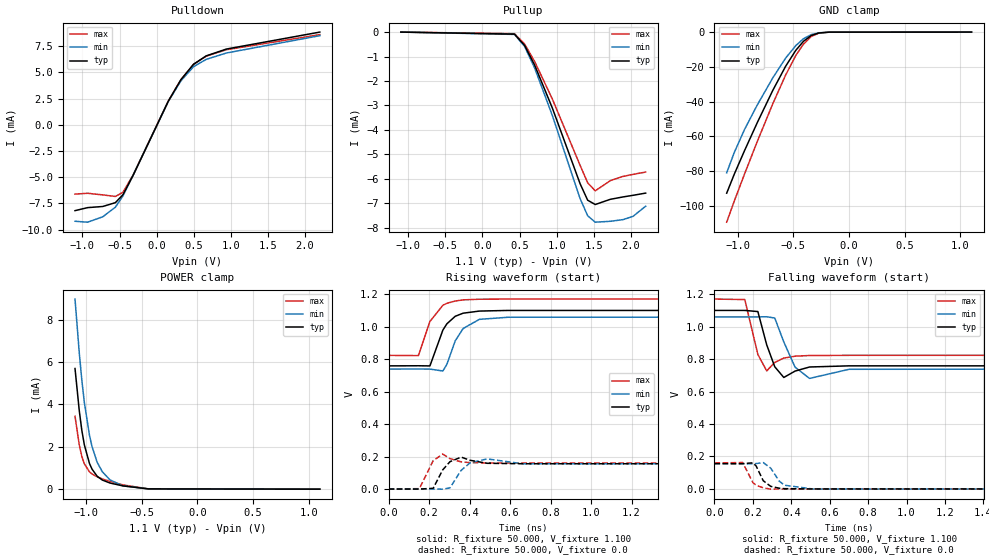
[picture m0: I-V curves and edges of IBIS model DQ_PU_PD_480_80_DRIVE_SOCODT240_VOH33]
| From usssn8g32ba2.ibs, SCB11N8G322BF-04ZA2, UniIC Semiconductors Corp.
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|   Model DQ_PU_PD_480_80_DRIVE_SOCODT240_VOH33
[Model] DQ_PU_PD_480_80_DRIVE_SOCODT240_VOH33
Model_type I/O
Polarity   Inverting
Vinl =  98.000mV
Vinh =  0.268V
Vmeas =  0.183V
Rref =  50.000
Vref =  0.183V
C_comp   1.020pF   1.010pF   1.030pF
[Model Spec]
Vinh   0.268V   0.262V   0.280V
Vinl   98.000mV   92.000mV   0.110V
Vmeas   0.183V   0.177V   0.195V
Vref   0.183V   0.177V   0.195V
Rref   50.000   NA   NA
[Temperature Range]   25.000   0.105k   -40.000
[Voltage Range]   1.100V   1.060V   1.170V
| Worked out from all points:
|   slope of the pulldown table from 0 to 0.165 V, typ, clamps not added: 70.2 ohm
|   GND clamp passes 1 mA (typ) near -0.30 V on its own axis
|   POWER clamp passes 1 mA (typ) near -0.95 V on its own axis
|   rising waveform, R_fixture 50.000, V_fixture 1.100: 20-80 % time 72.7ps typ, 76.2ps min, 70.1ps max; typ from 0.759 V to 1.1 V
|   rising waveform, R_fixture 50.000, V_fixture 0.0: 20-80 % time 36.6ps typ, 46.1ps min, 30.1ps max; typ from 0 V to 0.156 V
|   falling waveform, R_fixture 50.000, V_fixture 1.100: 20-80 % time 44.4ps typ, 57.6ps min, 35.3ps max; typ from 1.1 V to 0.759 V
|   falling waveform, R_fixture 50.000, V_fixture 0.0: 20-80 % time 45.9ps typ, 57.9ps min, 42.8ps max; typ from 0.156 V to 0 V
[Pulldown]
|Voltage   I(typ)   I(min)   I(max)
-1.1V     -8.193mA   -9.206mA   -6.618mA
-930mV    -7.906mA   -9.295mA   -6.537mA
-726mV    -7.797mA   -8.78mA    -6.691mA
-556mV    -7.432mA   -7.863mA   -6.841mA
-454mV    -6.673mA   -6.794mA   -6.44mA
-318mV    -4.841mA   -4.838mA   -4.804mA
158mV     2.257mA    2.219mA    2.267mA
328mV     4.302mA    4.194mA    4.305mA
498mV     5.77mA     5.539mA    5.759mA
668mV     6.567mA    6.233mA    6.54mA
940mV     7.217mA    6.841mA    7.152mA
2.2V      8.836mA    8.496mA    8.595mA
[Pullup]
|Voltage   I(typ)   I(min)   I(max)
-1.1V     500pA      5.412nA    0A
432mV     -84.42uA   -95.4uA    -65.89uA
568mV     -546.4uA   -585.3uA   -487.9uA
704mV     -1.354mA   -1.473mA   -1.207mA
942mV     -3.104mA   -3.412mA   -2.737mA
1.316V    -6.198mA   -6.807mA   -5.446mA
1.418V    -6.872mA   -7.507mA   -6.161mA
1.52V     -7.049mA   -7.771mA   -6.489mA
1.724V    -6.835mA   -7.734mA   -6.072mA
1.894V    -6.739mA   -7.667mA   -5.9mA
2.03V     -6.672mA   -7.532mA   -5.816mA
2.2V      -6.582mA   -7.117mA   -5.721mA
[GND_clamp]
|Voltage   I(typ)   I(min)   I(max)
-1.1V     -92.78mA   -81.05mA   -109.5mA
-1.031V   -81.73mA   -69.22mA   -97.17mA
-939mV    -68.18mA   -56.02mA   -81.64mA
-824mV    -52mA      -41.83mA   -62.83mA
-686mV    -33.62mA   -26.41mA   -41.32mA
-571mV    -19.76mA   -15.06mA   -24.85mA
-479mV    -10.5mA    -7.76mA    -13.5mA
-410mV    -5.313mA   -3.84mA    -6.916mA
-341mV    -2.007mA   -1.45mA    -2.59mA
-272mV    -506.9uA   -403.5uA   -609.8uA
-180mV    -45.65uA   -51.35uA   -43.55uA
1.1V      0A         0A         0A
[POWER_clamp]
|Voltage   I(typ)   I(min)   I(max)
-1.1V     5.691mA    8.967mA    3.44mA
-1.062V   3.709mA    6.444mA    2.092mA
-1.039V   2.781mA    5.152mA    1.546mA
-1.016V   2.086mA    4.085mA    1.193mA
-970mV    1.21mA     2.539mA    818.5uA
-947mV    943.7uA    2.005mA    716.7uA
-901mV    610.1uA    1.27mA     581.3uA
-855mV    430.7uA    824.1uA    484.6uA
-786mV    289.9uA    439.4uA    366uA
-671mV    155.9uA    155.9uA    203.6uA
-441mV    13.2uA     12.79uA    15.03uA
1.1V      0A         0A         0A
[Ramp]
| variable   typ   min   max
dV/dt_r   93.600m/36.664p   92.826m/46.242p   96.210m/30.186p
dV/dt_f   0.205/44.503p   0.193/57.728p   0.208/35.422p
R_load = 50.000
[Rising Waveform]
R_fixture= 50.000
V_fixture= 1.100
V_fixture_min= 1.060
V_fixture_max= 1.170
|time   V(typ)   V(min)   V(max)
0s        758.6mV    738.8mV    823.3mV
147ps     759.3mV    739.2mV    821.7mV
204ps     758.3mV    738.7mV    1.032V
268ps     978.9mV    727.2mV    1.132V
288ps     1.018V     769mV      1.144V
329ps     1.064V     912.8mV    1.158V
368ps     1.083V     988.6mV    1.165V
448ps     1.096V     1.045V     1.169V
590ps     1.1V       1.058V     1.17V
3ns       1.1V       1.06V      1.17V
[Rising Waveform]
R_fixture= 50.000
V_fixture= 0.0
V_fixture_min= 0.0
V_fixture_max= 0.0
|time   V(typ)   V(min)   V(max)
0s        3.732uV    13.63uV    882.6nV
152ps     103.7uV    19.99uV    2.587mV
220ps     4.697mV    261.8uV    174.6mV
267ps     117.8mV    -621.2uV   215.5mV
303ps     168.6mV    7.26mV     187.6mV
358ps     196.8mV    115.1mV    167.5mV
403ps     177.2mV    162.1mV    162.8mV
487ps     158.7mV    185.8mV    160.7mV
665ps     156mV      155.4mV    160.4mV
3ns       156mV      154.7mV    160.3mV
[Falling Waveform]
R_fixture= 50.000
V_fixture= 1.100
V_fixture_min= 1.060
V_fixture_max= 1.170
|time   V(typ)   V(min)   V(max)
0s        1.1V       1.06V      1.17V
158ps     1.1V       1.06V      1.167V
226ps     1.093V     1.06V      828.9mV
272ps     888.3mV    1.061V     727.4mV
314ps     752.8mV    1.053V     779.2mV
361ps     686.9mV    905.8mV    806.4mV
420ps     726.3mV    749.9mV    818.1mV
495ps     751.4mV    681mV      822.1mV
701ps     758.5mV    737.3mV    823.3mV
3ns       758.6mV    738.8mV    823.3mV
[Falling Waveform]
R_fixture= 50.000
V_fixture= 0.0
V_fixture_min= 0.0
V_fixture_max= 0.0
|time   V(typ)   V(min)   V(max)
0s        156mV      154.7mV    160.3mV
147ps     155.8mV    154.5mV    162.6mV
200ps     161mV      154.7mV    39.31mV
217ps     141.6mV    156.3mV    22.47mV
254ps     50.63mV    162.4mV    6.835mV
293ps     15.74mV    128.2mV    -1.397mV
337ps     4.558mV    48.58mV    -411.5uV
364ps     1.649mV    23.14mV    -171.8uV
516ps     -57.88uV   -831.8uV   -679.2nV
3ns       2.958uV    13.59uV    500.8nV
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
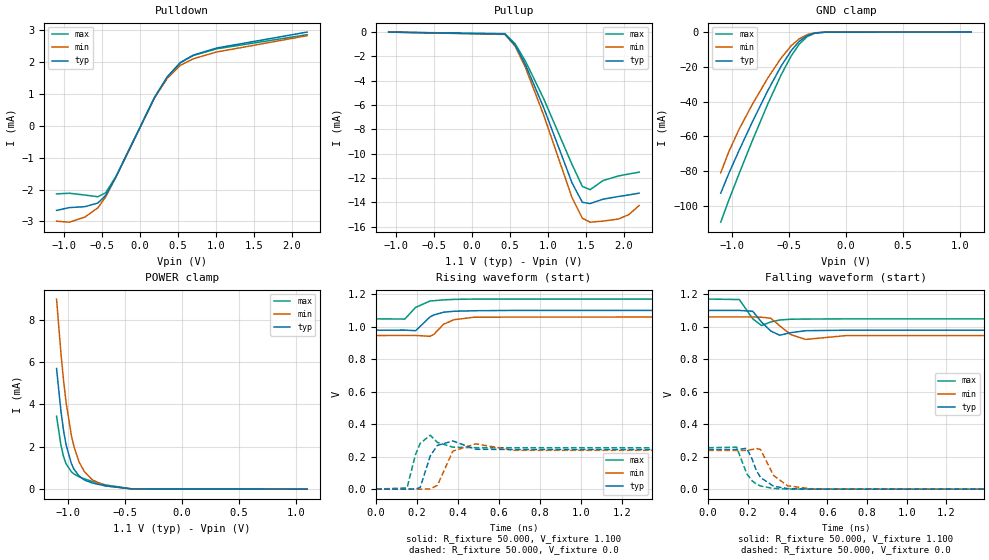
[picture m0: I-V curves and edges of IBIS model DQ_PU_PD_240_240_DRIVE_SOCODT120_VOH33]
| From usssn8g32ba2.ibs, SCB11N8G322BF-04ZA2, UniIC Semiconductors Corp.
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|   Model DQ_PU_PD_240_240_DRIVE_SOCODT120_VOH33
[Model] DQ_PU_PD_240_240_DRIVE_SOCODT120_VOH33
Model_type I/O
Polarity   Inverting
Vinl =  98.000mV
Vinh =  0.268V
Vmeas =  0.183V
Rref =  50.000
Vref =  0.183V
C_comp   1.020pF   1.010pF   1.030pF
[Model Spec]
Vinh   0.268V   0.262V   0.280V
Vinl   98.000mV   92.000mV   0.110V
Vmeas   0.183V   0.177V   0.195V
Vref   0.183V   0.177V   0.195V
Rref   50.000   NA   NA
[Temperature Range]   25.000   0.105k   -40.000
[Voltage Range]   1.100V   1.060V   1.170V
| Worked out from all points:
|   slope of the pulldown table from 0 to 0.165 V, typ, clamps not added: 211 ohm
|   GND clamp passes 1 mA (typ) near -0.30 V on its own axis
|   POWER clamp passes 1 mA (typ) near -0.95 V on its own axis
|   rising waveform, R_fixture 50.000, V_fixture 1.100: 20-80 % time 68.4ps typ, 69.4ps min, 67.2ps max; typ from 0.978 V to 1.1 V
|   rising waveform, R_fixture 50.000, V_fixture 0.0: 20-80 % time 33.2ps typ, 42.6ps min, 27.1ps max; typ from 0 V to 0.244 V
|   falling waveform, R_fixture 50.000, V_fixture 1.100: 20-80 % time 46.2ps typ, 60.6ps min, 36ps max; typ from 1.1 V to 0.978 V
|   falling waveform, R_fixture 50.000, V_fixture 0.0: 20-80 % time 63.3ps typ, 70.6ps min, 60.2ps max; typ from 0.244 V to 0 V
[Pulldown]
|Voltage   I(typ)   I(min)   I(max)
-1.1V     -2.652mA   -2.992mA   -2.134mA
-930mV    -2.565mA   -3.023mA   -2.114mA
-726mV    -2.535mA   -2.862mA   -2.171mA
-556mV    -2.422mA   -2.572mA   -2.223mA
-454mV    -2.185mA   -2.234mA   -2.101mA
-318mV    -1.604mA   -1.606mA   -1.589mA
192mV     900.6uA    884.3uA    903.8uA
362mV     1.549mA    1.507mA    1.549mA
532mV     1.993mA    1.907mA    1.988mA
702mV     2.225mA    2.111mA    2.215mA
1.008V    2.447mA    2.322mA    2.422mA
2.2V      2.948mA    2.835mA    2.866mA
[Pullup]
|Voltage   I(typ)   I(min)   I(max)
-1.1V     1nA        10.92nA    0A
432mV     -168.8uA   -190.8uA   -131.8uA
568mV     -1.092mA   -1.17mA    -975.3uA
704mV     -2.706mA   -2.942mA   -2.412mA
942mV     -6.202mA   -6.816mA   -5.469mA
1.316V    -12.39mA   -13.6mA    -10.88mA
1.452V    -13.99mA   -15.3mA    -12.68mA
1.554V    -14.09mA   -15.62mA   -12.95mA
1.724V    -13.73mA   -15.53mA   -12.2mA
1.928V    -13.51mA   -15.36mA   -11.82mA
2.064V    -13.38mA   -15mA      -11.66mA
2.2V      -13.23mA   -14.25mA   -11.51mA
[GND_clamp]
|Voltage   I(typ)   I(min)   I(max)
-1.1V     -92.78mA   -81.05mA   -109.5mA
-1.031V   -81.73mA   -69.22mA   -97.17mA
-939mV    -68.18mA   -56.02mA   -81.64mA
-824mV    -52mA      -41.83mA   -62.83mA
-686mV    -33.62mA   -26.41mA   -41.32mA
-571mV    -19.76mA   -15.06mA   -24.85mA
-479mV    -10.5mA    -7.76mA    -13.5mA
-410mV    -5.313mA   -3.84mA    -6.916mA
-341mV    -2.007mA   -1.45mA    -2.59mA
-272mV    -506.9uA   -403.5uA   -609.8uA
-180mV    -45.65uA   -51.35uA   -43.55uA
1.1V      0A         0A         0A
[POWER_clamp]
|Voltage   I(typ)   I(min)   I(max)
-1.1V     5.691mA    8.967mA    3.44mA
-1.062V   3.709mA    6.444mA    2.092mA
-1.039V   2.781mA    5.152mA    1.546mA
-1.016V   2.086mA    4.085mA    1.193mA
-970mV    1.21mA     2.539mA    818.5uA
-947mV    943.7uA    2.005mA    716.7uA
-901mV    610.1uA    1.27mA     581.3uA
-855mV    430.7uA    824.1uA    484.6uA
-786mV    289.9uA    439.4uA    366uA
-671mV    155.9uA    155.9uA    203.6uA
-441mV    13.2uA     12.79uA    15.03uA
1.1V      0A         0A         0A
[Ramp]
| variable   typ   min   max
dV/dt_r   0.146/33.433p   0.143/42.829p   0.153/27.195p
dV/dt_f   72.903m/46.226p   68.572m/60.684p   73.268m/36.035p
R_load = 50.000
[Rising Waveform]
R_fixture= 50.000
V_fixture= 1.100
V_fixture_min= 1.060
V_fixture_max= 1.170
|time   V(typ)   V(min)   V(max)
0s        978.5mV    945.7mV    1.048V
140ps     978.8mV    945.9mV    1.047V
193ps     975.5mV    946mV      1.119V
263ps     1.06V      940.7mV    1.158V
281ps     1.072V     951.9mV    1.16V
329ps     1.089V     1.015V     1.165V
380ps     1.095V     1.043V     1.168V
476ps     1.098V     1.058V     1.17V
657ps     1.1V       1.059V     1.17V
3ns       1.1V       1.06V      1.17V
[Rising Waveform]
R_fixture= 50.000
V_fixture= 0.0
V_fixture_min= 0.0
V_fixture_max= 0.0
|time   V(typ)   V(min)   V(max)
0s        5.235uV    19.06uV    1.24uV
151ps     -127.8uV   55.87uV    7.711mV
192ps     848.9uV    -48.02uV   212.6mV
215ps     10.21mV    -154.5uV   281.6mV
264ps     204.2mV    1.24mV     331.9mV
299ps     269.3mV    23.32mV    287.7mV
374ps     296.6mV    233.6mV    258.3mV
486ps     245.4mV    278.9mV    255.2mV
672ps     243.9mV    238.9mV    255mV
3ns       243.9mV    238.7mV    255mV
[Falling Waveform]
R_fixture= 50.000
V_fixture= 1.100
V_fixture_min= 1.060
V_fixture_max= 1.170
|time   V(typ)   V(min)   V(max)
0s        1.1V       1.06V      1.17V
157ps     1.1V       1.06V      1.167V
224ps     1.095V     1.06V      1.049V
269ps     1.028V     1.058V     1.007V
315ps     973.5mV    1.052V     1.029V
360ps     947.5mV    1.006V     1.041V
417ps     963.5mV    950.8mV    1.046V
491ps     975.2mV    921.6mV    1.047V
694ps     978.4mV    945.1mV    1.048V
3ns       978.5mV    945.7mV    1.048V
[Falling Waveform]
R_fixture= 50.000
V_fixture= 0.0
V_fixture_min= 0.0
V_fixture_max= 0.0
|time   V(typ)   V(min)   V(max)
0s        243.9mV    238.7mV    255mV
143ps     243.7mV    238.4mV    258.3mV
194ps     251.5mV    238.7mV    95.54mV
222ps     183mV      244.4mV    50.66mV
242ps     116.4mV    251.1mV    32.33mV
264ps     71.49mV    243.8mV    19.47mV
329ps     18.12mV    85.28mV    4.209mV
400ps     3.231mV    20.64mV    922.4uV
524ps     270.3uV    1.317mV    64.67uV
3ns       5.289uV    19.12uV    1.062uV
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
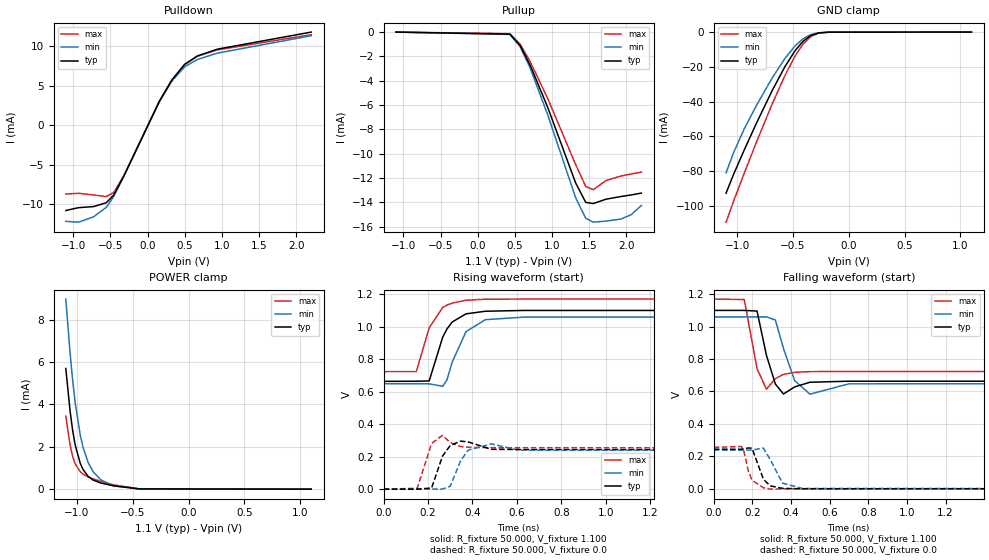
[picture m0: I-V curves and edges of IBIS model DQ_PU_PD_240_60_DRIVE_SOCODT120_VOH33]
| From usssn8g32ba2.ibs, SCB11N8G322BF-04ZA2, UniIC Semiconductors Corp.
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|   Model DQ_PU_PD_240_60_DRIVE_SOCODT120_VOH33
[Model] DQ_PU_PD_240_60_DRIVE_SOCODT120_VOH33
Model_type I/O
Polarity   Inverting
Vinl =  98.000mV
Vinh =  0.268V
Vmeas =  0.183V
Rref =  50.000
Vref =  0.183V
C_comp   1.020pF   1.010pF   1.030pF
[Model Spec]
Vinh   0.268V   0.262V   0.280V
Vinl   98.000mV   92.000mV   0.110V
Vmeas   0.183V   0.177V   0.195V
Vref   0.183V   0.177V   0.195V
Rref   50.000   NA   NA
[Temperature Range]   25.000   0.105k   -40.000
[Voltage Range]   1.100V   1.060V   1.170V
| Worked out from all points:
|   slope of the pulldown table from 0 to 0.165 V, typ, clamps not added: 52.7 ohm
|   GND clamp passes 1 mA (typ) near -0.30 V on its own axis
|   POWER clamp passes 1 mA (typ) near -0.95 V on its own axis
|   rising waveform, R_fixture 50.000, V_fixture 1.100: 20-80 % time 74.1ps typ, 77.7ps min, 71.4ps max; typ from 0.663 V to 1.1 V
|   rising waveform, R_fixture 50.000, V_fixture 0.0: 20-80 % time 33ps typ, 42ps min, 27.1ps max; typ from 0 V to 0.244 V
|   falling waveform, R_fixture 50.000, V_fixture 1.100: 20-80 % time 43.8ps typ, 57.2ps min, 35.1ps max; typ from 1.1 V to 0.663 V
|   falling waveform, R_fixture 50.000, V_fixture 0.0: 20-80 % time 41.9ps typ, 57.5ps min, 37.5ps max; typ from 0.244 V to 0 V
[Pulldown]
|Voltage   I(typ)   I(min)   I(max)
-1.1V     -10.83mA   -12.2mA    -8.746mA
-930mV    -10.47mA   -12.31mA   -8.649mA
-726mV    -10.33mA   -11.63mA   -8.863mA
-556mV    -9.849mA   -10.43mA   -9.063mA
-454mV    -8.849mA   -9.016mA   -8.534mA
-318mV    -6.436mA   -6.433mA   -6.383mA
158mV     3.005mA    2.954mA    3.019mA
328mV     5.729mA    5.586mA    5.734mA
498mV     7.686mA    7.379mA    7.672mA
668mV     8.751mA    8.306mA    8.715mA
940mV     9.618mA    9.116mA    9.532mA
2.2V      11.78mA    11.32mA    11.45mA
[Pullup]
|Voltage   I(typ)   I(min)   I(max)
-1.1V     1nA        10.92nA    0A
432mV     -168.8uA   -190.8uA   -131.8uA
568mV     -1.092mA   -1.17mA    -975.3uA
704mV     -2.706mA   -2.942mA   -2.412mA
942mV     -6.202mA   -6.816mA   -5.469mA
1.316V    -12.39mA   -13.6mA    -10.88mA
1.452V    -13.99mA   -15.3mA    -12.68mA
1.554V    -14.09mA   -15.62mA   -12.95mA
1.724V    -13.73mA   -15.53mA   -12.2mA
1.928V    -13.51mA   -15.36mA   -11.82mA
2.064V    -13.38mA   -15mA      -11.66mA
2.2V      -13.23mA   -14.25mA   -11.51mA
[GND_clamp]
|Voltage   I(typ)   I(min)   I(max)
-1.1V     -92.78mA   -81.05mA   -109.5mA
-1.031V   -81.73mA   -69.22mA   -97.17mA
-939mV    -68.18mA   -56.02mA   -81.64mA
-824mV    -52mA      -41.83mA   -62.83mA
-686mV    -33.62mA   -26.41mA   -41.32mA
-571mV    -19.76mA   -15.06mA   -24.85mA
-479mV    -10.5mA    -7.76mA    -13.5mA
-410mV    -5.313mA   -3.84mA    -6.916mA
-341mV    -2.007mA   -1.45mA    -2.59mA
-272mV    -506.9uA   -403.5uA   -609.8uA
-180mV    -45.65uA   -51.35uA   -43.55uA
1.1V      0A         0A         0A
[POWER_clamp]
|Voltage   I(typ)   I(min)   I(max)
-1.1V     5.691mA    8.967mA    3.44mA
-1.062V   3.709mA    6.444mA    2.092mA
-1.039V   2.781mA    5.152mA    1.546mA
-1.016V   2.086mA    4.085mA    1.193mA
-970mV    1.21mA     2.539mA    818.5uA
-947mV    943.7uA    2.005mA    716.7uA
-901mV    610.1uA    1.27mA     581.3uA
-855mV    430.7uA    824.1uA    484.6uA
-786mV    289.9uA    439.4uA    366uA
-671mV    155.9uA    155.9uA    203.6uA
-441mV    13.2uA     12.79uA    15.03uA
1.1V      0A         0A         0A
[Ramp]
| variable   typ   min   max
dV/dt_r   0.146/33.122p   0.143/42.094p   0.153/27.213p
dV/dt_f   0.262/43.898p   0.247/57.215p   0.268/35.061p
R_load = 50.000
[Rising Waveform]
R_fixture= 50.000
V_fixture= 1.100
V_fixture_min= 1.060
V_fixture_max= 1.170
|time   V(typ)   V(min)   V(max)
0s        663.5mV    648.6mV    723.5mV
147ps     664.3mV    649.2mV    723.2mV
205ps     665.9mV    648.4mV    993mV
266ps     935.4mV    633.2mV    1.118V
285ps     985.6mV    672.4mV    1.133V
309ps     1.029V     783.3mV    1.145V
371ps     1.079V     969.6mV    1.163V
458ps     1.095V     1.043V     1.169V
632ps     1.1V       1.059V     1.17V
3ns       1.1V       1.06V      1.17V
[Rising Waveform]
R_fixture= 50.000
V_fixture= 0.0
V_fixture_min= 0.0
V_fixture_max= 0.0
|time   V(typ)   V(min)   V(max)
0s        3.262uV    11.92uV    771.1nV
151ps     63.3uV     27.96uV    5.378mV
216ps     7.193mV    209.4uV    281.4mV
265ps     203.2mV    363.8uV    331.7mV
300ps     269mV      18.28mV    286.4mV
347ps     295.8mV    175.9mV    262.3mV
381ps     290.4mV    240.3mV    257.7mV
485ps     245.4mV    278.8mV    255.2mV
608ps     244mV      239.7mV    255mV
3ns       243.9mV    238.7mV    255mV
[Falling Waveform]
R_fixture= 50.000
V_fixture= 1.100
V_fixture_min= 1.060
V_fixture_max= 1.170
|time   V(typ)   V(min)   V(max)
0s        1.1V       1.06V      1.17V
158ps     1.1V       1.06V      1.167V
224ps     1.096V     1.06V      740.6mV
273ps     821.6mV    1.06V      613.7mV
319ps     645.9mV    1.041V     679.5mV
361ps     584.5mV    864.8mV    705.6mV
419ps     628.2mV    666.7mV    718.1mV
498ps     656.9mV    583.3mV    722.5mV
699ps     663.4mV    647.1mV    723.5mV
3ns       663.5mV    648.6mV    723.5mV
[Falling Waveform]
R_fixture= 50.000
V_fixture= 0.0
V_fixture_min= 0.0
V_fixture_max= 0.0
|time   V(typ)   V(min)   V(max)
0s        243.9mV    238.7mV    255mV
143ps     243.5mV    238.4mV    260.4mV
155ps     245mV      238.2mV    234.6mV
179ps     251.8mV    238mV      110.3mV
198ps     250mV      239.1mV    52.96mV
257ps     58.64mV    250.3mV    5.822mV
292ps     17.83mV    181.2mV    -2.637mV
356ps     2.328mV    34.69mV    -326.2uV
458ps     -411.7uV   2.202mV    -8.098uV
3ns       2.909uV    11.9uV     495.6nV
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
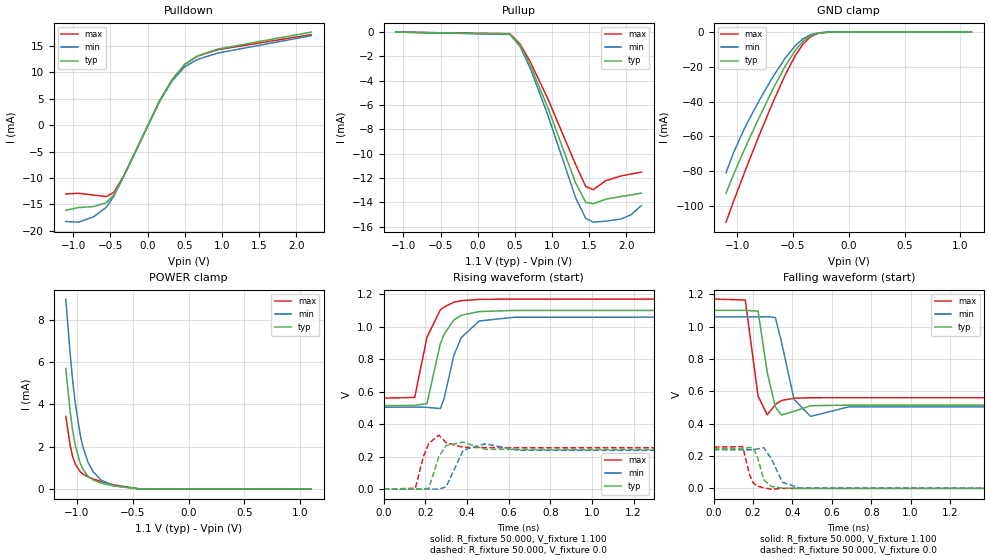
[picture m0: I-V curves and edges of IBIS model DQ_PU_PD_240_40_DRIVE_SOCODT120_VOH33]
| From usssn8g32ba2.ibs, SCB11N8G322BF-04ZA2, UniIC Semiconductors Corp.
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|   Model DQ_PU_PD_240_40_DRIVE_SOCODT120_VOH33
[Model] DQ_PU_PD_240_40_DRIVE_SOCODT120_VOH33
Model_type I/O
Polarity   Inverting
Vinl =  98.000mV
Vinh =  0.268V
Vmeas =  0.183V
Rref =  50.000
Vref =  0.183V
C_comp   1.020pF   1.010pF   1.030pF
[Model Spec]
Vinh   0.268V   0.262V   0.280V
Vinl   98.000mV   92.000mV   0.110V
Vmeas   0.183V   0.177V   0.195V
Vref   0.183V   0.177V   0.195V
Rref   50.000   NA   NA
[Temperature Range]   25.000   0.105k   -40.000
[Voltage Range]   1.100V   1.060V   1.170V
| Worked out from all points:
|   slope of the pulldown table from 0 to 0.165 V, typ, clamps not added: 35.3 ohm
|   GND clamp passes 1 mA (typ) near -0.30 V on its own axis
|   POWER clamp passes 1 mA (typ) near -0.95 V on its own axis
|   rising waveform, R_fixture 50.000, V_fixture 1.100: 20-80 % time 76.3ps typ, 80ps min, 73.4ps max; typ from 0.514 V to 1.1 V
|   rising waveform, R_fixture 50.000, V_fixture 0.0: 20-80 % time 32.8ps typ, 41.8ps min, 27ps max; typ from 0 V to 0.244 V
|   falling waveform, R_fixture 50.000, V_fixture 1.100: 20-80 % time 40.6ps typ, 53.5ps min, 33.3ps max; typ from 1.1 V to 0.514 V
|   falling waveform, R_fixture 50.000, V_fixture 0.0: 20-80 % time 34.9ps typ, 53.1ps min, 30.4ps max; typ from 0.244 V to 0 V
[Pulldown]
|Voltage   I(typ)   I(min)   I(max)
-1.1V     -16.13mA   -18.25mA   -13.03mA
-930mV    -15.61mA   -18.38mA   -12.9mA
-726mV    -15.42mA   -17.36mA   -13.24mA
-556mV    -14.7mA    -15.55mA   -13.53mA
-454mV    -13.2mA    -13.45mA   -12.73mA
-318mV    -9.609mA   -9.606mA   -9.529mA
158mV     4.492mA    4.415mA    4.512mA
328mV     8.568mA    8.352mA    8.576mA
498mV     11.5mA     11.04mA    11.48mA
668mV     13.1mA     12.43mA    13.05mA
940mV     14.4mA     13.65mA    14.28mA
2.2V      17.63mA    16.95mA    17.16mA
[Pullup]
|Voltage   I(typ)   I(min)   I(max)
-1.1V     1nA        10.92nA    0A
432mV     -168.8uA   -190.8uA   -131.8uA
568mV     -1.092mA   -1.17mA    -975.3uA
704mV     -2.706mA   -2.942mA   -2.412mA
942mV     -6.202mA   -6.816mA   -5.469mA
1.316V    -12.39mA   -13.6mA    -10.88mA
1.452V    -13.99mA   -15.3mA    -12.68mA
1.554V    -14.09mA   -15.62mA   -12.95mA
1.724V    -13.73mA   -15.53mA   -12.2mA
1.928V    -13.51mA   -15.36mA   -11.82mA
2.064V    -13.38mA   -15mA      -11.66mA
2.2V      -13.23mA   -14.25mA   -11.51mA
[GND_clamp]
|Voltage   I(typ)   I(min)   I(max)
-1.1V     -92.78mA   -81.05mA   -109.5mA
-1.031V   -81.73mA   -69.22mA   -97.17mA
-939mV    -68.18mA   -56.02mA   -81.64mA
-824mV    -52mA      -41.83mA   -62.83mA
-686mV    -33.62mA   -26.41mA   -41.32mA
-571mV    -19.76mA   -15.06mA   -24.85mA
-479mV    -10.5mA    -7.76mA    -13.5mA
-410mV    -5.313mA   -3.84mA    -6.916mA
-341mV    -2.007mA   -1.45mA    -2.59mA
-272mV    -506.9uA   -403.5uA   -609.8uA
-180mV    -45.65uA   -51.35uA   -43.55uA
1.1V      0A         0A         0A
[POWER_clamp]
|Voltage   I(typ)   I(min)   I(max)
-1.1V     5.691mA    8.967mA    3.44mA
-1.062V   3.709mA    6.444mA    2.092mA
-1.039V   2.781mA    5.152mA    1.546mA
-1.016V   2.086mA    4.085mA    1.193mA
-970mV    1.21mA     2.539mA    818.5uA
-947mV    943.7uA    2.005mA    716.7uA
-901mV    610.1uA    1.27mA     581.3uA
-855mV    430.7uA    824.1uA    484.6uA
-786mV    289.9uA    439.4uA    366uA
-671mV    155.9uA    155.9uA    203.6uA
-441mV    13.2uA     12.79uA    15.03uA
1.1V      0A         0A         0A
[Ramp]
| variable   typ   min   max
dV/dt_r   0.146/32.899p   0.143/41.821p   0.153/27.065p
dV/dt_f   0.351/40.740p   0.333/53.677p   0.366/33.372p
R_load = 50.000
[Rising Waveform]
R_fixture= 50.000
V_fixture= 1.100
V_fixture_min= 1.060
V_fixture_max= 1.170
|time   V(typ)   V(min)   V(max)
0s        514.4mV    504.3mV    560.3mV
149ps     515.1mV    504.9mV    564.6mV
208ps     526.6mV    503.5mV    935.4mV
272ps     894.5mV    496.2mV    1.103V
290ps     952.3mV    555.6mV    1.121V
336ps     1.04V      819.3mV    1.15V
372ps     1.07V      931.5mV    1.16V
458ps     1.093V     1.035V     1.168V
627ps     1.1V       1.058V     1.17V
3ns       1.1V       1.06V      1.17V
[Rising Waveform]
R_fixture= 50.000
V_fixture= 0.0
V_fixture_min= 0.0
V_fixture_max= 0.0
|time   V(typ)   V(min)   V(max)
0s        2.608uV    9.548uV    616.3nV
152ps     220.9uV    25.11uV    5.14mV
192ps     375.9uV    109.4uV    204.8mV
217ps     5.989mV    424.4uV    282.2mV
265ps     200.4mV    -185.9uV   331.6mV
300ps     268.2mV    14.38mV    286.2mV
382ps     289.3mV    240.2mV    257.6mV
487ps     245.4mV    278.9mV    255.2mV
648ps     243.9mV    239.1mV    255mV
3ns       243.9mV    238.7mV    255mV
[Falling Waveform]
R_fixture= 50.000
V_fixture= 1.100
V_fixture_min= 1.060
V_fixture_max= 1.170
|time   V(typ)   V(min)   V(max)
0s        1.1V       1.06V      1.17V
160ps     1.1V       1.06V      1.164V
225ps     1.096V     1.06V      570.3mV
272ps     713.9mV    1.061V     454.6mV
313ps     503.7mV    1.056V     518.8mV
344ps     453.6mV    904.5mV    542.9mV
408ps     476.2mV    549.7mV    557mV
492ps     510.8mV    444.4mV    559.9mV
686ps     514.4mV    503.4mV    560.3mV
3ns       514.4mV    504.3mV    560.3mV
[Falling Waveform]
R_fixture= 50.000
V_fixture= 0.0
V_fixture_min= 0.0
V_fixture_max= 0.0
|time   V(typ)   V(min)   V(max)
0s        243.9mV    238.7mV    255mV
147ps     243.8mV    238.4mV    257.5mV
182ps     252.6mV    238mV      83.29mV
199ps     250.4mV    239.1mV    36.52mV
220ps     200.8mV    243.4mV    13.77mV
254ps     53.6mV     251.2mV    3.217mV
292ps     11.46mV    184.5mV    -5.144mV
349ps     1.652mV    37.28mV    -536.1uV
436ps     -1.279mV   2.388mV    -11.73uV
3ns       898.7nV    9.501uV    178.5nV
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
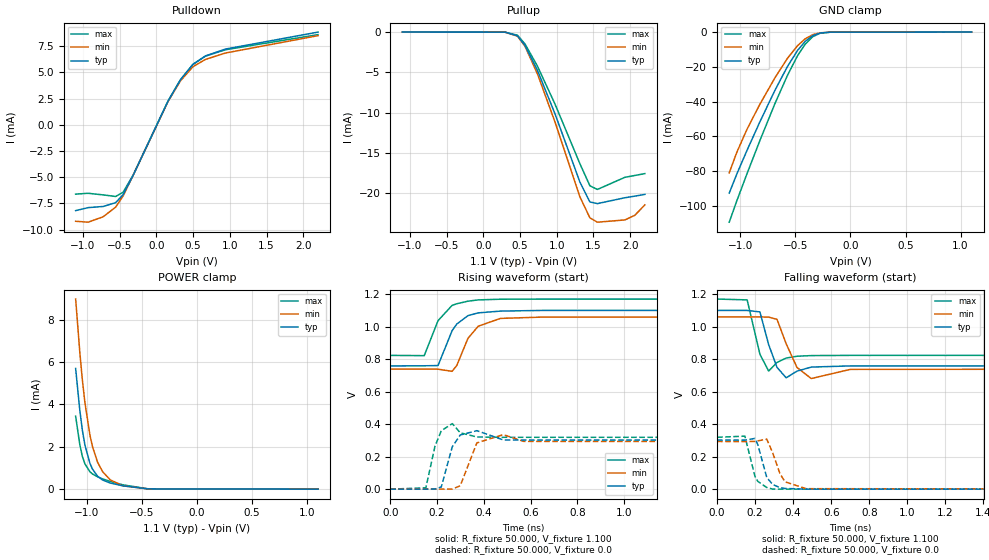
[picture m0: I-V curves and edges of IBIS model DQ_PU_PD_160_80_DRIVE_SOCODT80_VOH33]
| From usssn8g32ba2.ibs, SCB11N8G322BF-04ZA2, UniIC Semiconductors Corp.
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|   Model DQ_PU_PD_160_80_DRIVE_SOCODT80_VOH33
[Model] DQ_PU_PD_160_80_DRIVE_SOCODT80_VOH33
Model_type I/O
Polarity   Inverting
Vinl =  98.000mV
Vinh =  0.268V
Vmeas =  0.183V
Rref =  50.000
Vref =  0.183V
C_comp   1.020pF   1.010pF   1.030pF
[Model Spec]
Vinh   0.268V   0.262V   0.280V
Vinl   98.000mV   92.000mV   0.110V
Vmeas   0.183V   0.177V   0.195V
Vref   0.183V   0.177V   0.195V
Rref   50.000   NA   NA
[Temperature Range]   25.000   0.105k   -40.000
[Voltage Range]   1.100V   1.060V   1.170V
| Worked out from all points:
|   slope of the pulldown table from 0 to 0.165 V, typ, clamps not added: 70.2 ohm
|   GND clamp passes 1 mA (typ) near -0.30 V on its own axis
|   POWER clamp passes 1 mA (typ) near -0.95 V on its own axis
|   rising waveform, R_fixture 50.000, V_fixture 1.100: 20-80 % time 71.7ps typ, 74.1ps min, 69.6ps max; typ from 0.759 V to 1.1 V
|   rising waveform, R_fixture 50.000, V_fixture 0.0: 20-80 % time 30.6ps typ, 39.4ps min, 25.1ps max; typ from 0 V to 0.302 V
|   falling waveform, R_fixture 50.000, V_fixture 1.100: 20-80 % time 44.9ps typ, 58.7ps min, 35.6ps max; typ from 1.1 V to 0.759 V
|   falling waveform, R_fixture 50.000, V_fixture 0.0: 20-80 % time 45.6ps typ, 58.4ps min, 42ps max; typ from 0.302 V to 0 V
[Pulldown]
|Voltage   I(typ)   I(min)   I(max)
-1.1V     -8.193mA   -9.206mA   -6.618mA
-930mV    -7.906mA   -9.295mA   -6.537mA
-726mV    -7.797mA   -8.78mA    -6.691mA
-556mV    -7.432mA   -7.863mA   -6.841mA
-454mV    -6.673mA   -6.794mA   -6.44mA
-318mV    -4.841mA   -4.838mA   -4.804mA
158mV     2.257mA    2.219mA    2.267mA
328mV     4.302mA    4.194mA    4.305mA
498mV     5.77mA     5.539mA    5.759mA
668mV     6.567mA    6.233mA    6.54mA
940mV     7.217mA    6.841mA    7.152mA
2.2V      8.836mA    8.496mA    8.595mA
[Pullup]
|Voltage   I(typ)   I(min)   I(max)
-1.1V     1.606nA    16.44nA    0A
296mV     -8.845uA   -14.64uA   -4.922uA
466mV     -464.7uA   -507.7uA   -387.5uA
568mV     -1.641mA   -1.758mA   -1.466mA
738mV     -4.764mA   -5.196mA   -4.236mA
976mV     -10.14mA   -11.16mA   -8.932mA
1.316V    -18.65mA   -20.49mA   -16.37mA
1.452V    -21.12mA   -23.1mA    -19.11mA
1.554V    -21.33mA   -23.64mA   -19.57mA
1.928V    -20.6mA    -23.36mA   -18.06mA
2.064V    -20.4mA    -22.78mA   -17.83mA
2.2V      -20.18mA   -21.49mA   -17.6mA
[GND_clamp]
|Voltage   I(typ)   I(min)   I(max)
-1.1V     -92.78mA   -81.05mA   -109.5mA
-1.031V   -81.73mA   -69.22mA   -97.17mA
-939mV    -68.18mA   -56.02mA   -81.64mA
-824mV    -52mA      -41.83mA   -62.83mA
-686mV    -33.62mA   -26.41mA   -41.32mA
-571mV    -19.76mA   -15.06mA   -24.85mA
-479mV    -10.5mA    -7.76mA    -13.5mA
-410mV    -5.313mA   -3.84mA    -6.916mA
-341mV    -2.007mA   -1.45mA    -2.59mA
-272mV    -506.9uA   -403.5uA   -609.8uA
-180mV    -45.65uA   -51.35uA   -43.55uA
1.1V      0A         0A         0A
[POWER_clamp]
|Voltage   I(typ)   I(min)   I(max)
-1.1V     5.691mA    8.967mA    3.44mA
-1.062V   3.709mA    6.444mA    2.092mA
-1.039V   2.781mA    5.152mA    1.546mA
-1.016V   2.086mA    4.085mA    1.193mA
-970mV    1.21mA     2.539mA    818.5uA
-947mV    943.7uA    2.005mA    716.7uA
-901mV    610.1uA    1.27mA     581.3uA
-855mV    430.7uA    824.1uA    484.6uA
-786mV    289.9uA    439.4uA    366uA
-671mV    155.9uA    155.9uA    203.6uA
-441mV    13.2uA     12.79uA    15.03uA
1.1V      0A         0A         0A
[Ramp]
| variable   typ   min   max
dV/dt_r   0.181/30.714p   0.176/39.225p   0.192/25.170p
dV/dt_f   0.205/44.979p   0.193/58.681p   0.208/35.640p
R_load = 50.000
[Rising Waveform]
R_fixture= 50.000
V_fixture= 1.100
V_fixture_min= 1.060
V_fixture_max= 1.170
|time   V(typ)   V(min)   V(max)
0s        758.6mV    738.8mV    823.3mV
145ps     759.3mV    739.2mV    821.8mV
204ps     760.8mV    738.5mV    1.037V
264ps     975mV      725.2mV    1.131V
284ps     1.016V     761mV      1.141V
332ps     1.068V     928.4mV    1.157V
376ps     1.085V     1.003V     1.165V
471ps     1.096V     1.051V     1.169V
649ps     1.1V       1.059V     1.17V
3ns       1.1V       1.06V      1.17V
[Rising Waveform]
R_fixture= 50.000
V_fixture= 0.0
V_fixture_min= 0.0
V_fixture_max= 0.0
|time   V(typ)   V(min)   V(max)
0s        3.732uV    13.63uV    882.6nV
152ps     -66.16uV   39.04uV    8.423mV
191ps     580.7uV    -2.967uV   264.6mV
218ps     13.56mV    4.858uV    359.6mV
265ps     261.3mV    726.2uV    403.3mV
299ps     333.2mV    20.86mV    346.9mV
370ps     360mV      284.8mV    321.1mV
483ps     302.8mV    335.7mV    319.2mV
570ps     302.1mV    294mV      319.2mV
3ns       302.1mV    293.3mV    319.2mV
[Falling Waveform]
R_fixture= 50.000
V_fixture= 1.100
V_fixture_min= 1.060
V_fixture_max= 1.170
|time   V(typ)   V(min)   V(max)
0s        1.1V       1.06V      1.17V
158ps     1.1V       1.06V      1.165V
225ps     1.091V     1.06V      830.6mV
271ps     889.7mV    1.059V     727mV
315ps     749.6mV    1.045V     779.9mV
363ps     685.4mV    895.2mV    806.9mV
420ps     726.3mV    749mV      818mV
495ps     751.4mV    680.8mV    822.1mV
701ps     758.5mV    737.3mV    823.3mV
3ns       758.6mV    738.8mV    823.3mV
[Falling Waveform]
R_fixture= 50.000
V_fixture= 0.0
V_fixture_min= 0.0
V_fixture_max= 0.0
|time   V(typ)   V(min)   V(max)
0s        302.1mV    293.3mV    319.2mV
146ps     301.6mV    292.8mV    326.2mV
199ps     312.1mV    293.6mV    78.48mV
214ps     274.2mV    297.2mV    47.69mV
261ps     72.62mV    307.7mV    9.958mV
292ps     28.59mV    224.5mV    497.4uV
330ps     9.557mV    96.68mV    80.23uV
357ps     4.317mV    44.96mV    55.5uV
468ps     -149uV     2.827mV    3.474uV
3ns       849.1nV    13.55uV    641.7nV
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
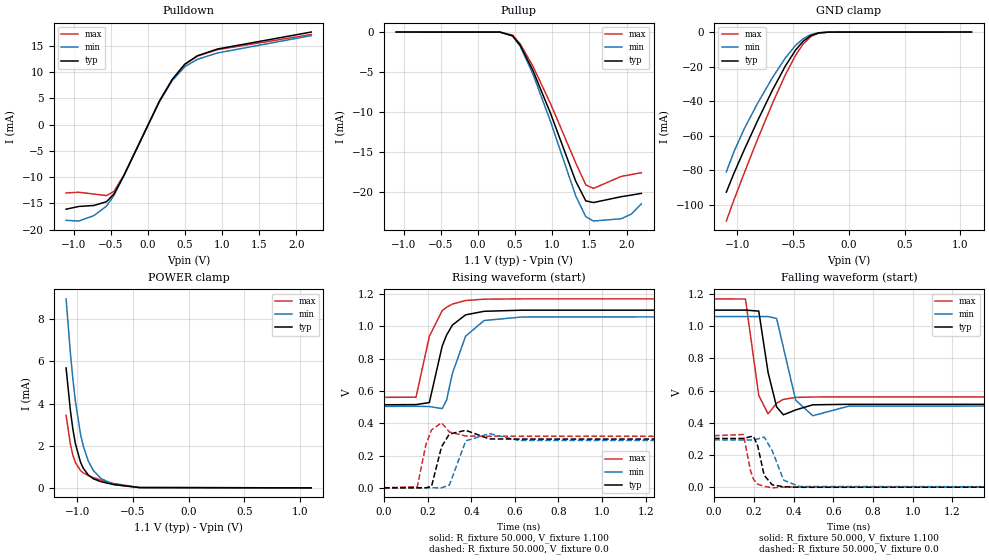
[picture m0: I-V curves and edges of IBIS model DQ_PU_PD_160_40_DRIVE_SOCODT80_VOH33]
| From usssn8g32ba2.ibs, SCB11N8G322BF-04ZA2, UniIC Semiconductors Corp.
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|   Model DQ_PU_PD_160_40_DRIVE_SOCODT80_VOH33
[Model] DQ_PU_PD_160_40_DRIVE_SOCODT80_VOH33
Model_type I/O
Polarity   Inverting
Vinl =  98.000mV
Vinh =  0.268V
Vmeas =  0.183V
Rref =  50.000
Vref =  0.183V
C_comp   1.020pF   1.010pF   1.030pF
[Model Spec]
Vinh   0.268V   0.262V   0.280V
Vinl   98.000mV   92.000mV   0.110V
Vmeas   0.183V   0.177V   0.195V
Vref   0.183V   0.177V   0.195V
Rref   50.000   NA   NA
[Temperature Range]   25.000   0.105k   -40.000
[Voltage Range]   1.100V   1.060V   1.170V
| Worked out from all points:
|   slope of the pulldown table from 0 to 0.165 V, typ, clamps not added: 35.3 ohm
|   GND clamp passes 1 mA (typ) near -0.30 V on its own axis
|   POWER clamp passes 1 mA (typ) near -0.95 V on its own axis
|   rising waveform, R_fixture 50.000, V_fixture 1.100: 20-80 % time 75.9ps typ, 79.4ps min, 73.3ps max; typ from 0.514 V to 1.1 V
|   rising waveform, R_fixture 50.000, V_fixture 0.0: 20-80 % time 30.4ps typ, 38.8ps min, 25ps max; typ from 0 V to 0.302 V
|   falling waveform, R_fixture 50.000, V_fixture 1.100: 20-80 % time 40.6ps typ, 53.8ps min, 33.4ps max; typ from 1.1 V to 0.514 V
|   falling waveform, R_fixture 50.000, V_fixture 0.0: 20-80 % time 33.9ps typ, 51.8ps min, 29.5ps max; typ from 0.302 V to 0 V
[Pulldown]
|Voltage   I(typ)   I(min)   I(max)
-1.1V     -16.13mA   -18.25mA   -13.03mA
-930mV    -15.61mA   -18.38mA   -12.9mA
-726mV    -15.42mA   -17.36mA   -13.24mA
-556mV    -14.7mA    -15.55mA   -13.53mA
-454mV    -13.2mA    -13.45mA   -12.73mA
-318mV    -9.609mA   -9.606mA   -9.529mA
158mV     4.492mA    4.415mA    4.512mA
328mV     8.568mA    8.352mA    8.576mA
498mV     11.5mA     11.04mA    11.48mA
668mV     13.1mA     12.43mA    13.05mA
940mV     14.4mA     13.65mA    14.28mA
2.2V      17.63mA    16.95mA    17.16mA
[Pullup]
|Voltage   I(typ)   I(min)   I(max)
-1.1V     1.606nA    16.44nA    0A
296mV     -8.845uA   -14.64uA   -4.922uA
466mV     -464.7uA   -507.7uA   -387.5uA
568mV     -1.641mA   -1.758mA   -1.466mA
738mV     -4.764mA   -5.196mA   -4.236mA
976mV     -10.14mA   -11.16mA   -8.932mA
1.316V    -18.65mA   -20.49mA   -16.37mA
1.452V    -21.12mA   -23.1mA    -19.11mA
1.554V    -21.33mA   -23.64mA   -19.57mA
1.928V    -20.6mA    -23.36mA   -18.06mA
2.064V    -20.4mA    -22.78mA   -17.83mA
2.2V      -20.18mA   -21.49mA   -17.6mA
[GND_clamp]
|Voltage   I(typ)   I(min)   I(max)
-1.1V     -92.78mA   -81.05mA   -109.5mA
-1.031V   -81.73mA   -69.22mA   -97.17mA
-939mV    -68.18mA   -56.02mA   -81.64mA
-824mV    -52mA      -41.83mA   -62.83mA
-686mV    -33.62mA   -26.41mA   -41.32mA
-571mV    -19.76mA   -15.06mA   -24.85mA
-479mV    -10.5mA    -7.76mA    -13.5mA
-410mV    -5.313mA   -3.84mA    -6.916mA
-341mV    -2.007mA   -1.45mA    -2.59mA
-272mV    -506.9uA   -403.5uA   -609.8uA
-180mV    -45.65uA   -51.35uA   -43.55uA
1.1V      0A         0A         0A
[POWER_clamp]
|Voltage   I(typ)   I(min)   I(max)
-1.1V     5.691mA    8.967mA    3.44mA
-1.062V   3.709mA    6.444mA    2.092mA
-1.039V   2.781mA    5.152mA    1.546mA
-1.016V   2.086mA    4.085mA    1.193mA
-970mV    1.21mA     2.539mA    818.5uA
-947mV    943.7uA    2.005mA    716.7uA
-901mV    610.1uA    1.27mA     581.3uA
-855mV    430.7uA    824.1uA    484.6uA
-786mV    289.9uA    439.4uA    366uA
-671mV    155.9uA    155.9uA    203.6uA
-441mV    13.2uA     12.79uA    15.03uA
1.1V      0A         0A         0A
[Ramp]
| variable   typ   min   max
dV/dt_r   0.181/30.400p   0.176/38.940p   0.192/24.893p
dV/dt_f   0.351/40.888p   0.333/53.901p   0.366/33.436p
R_load = 50.000
[Rising Waveform]
R_fixture= 50.000
V_fixture= 1.100
V_fixture_min= 1.060
V_fixture_max= 1.170
|time   V(typ)   V(min)   V(max)
0s        514.4mV    504.3mV    560.3mV
147ps     515.3mV    504.9mV    561.2mV
208ps     528mV      503.5mV    937.8mV
267ps     877.9mV    490.7mV    1.097V
287ps     945.8mV    543.2mV    1.118V
314ps     1.008V     710.1mV    1.138V
374ps     1.071V     938.4mV    1.16V
459ps     1.093V     1.036V     1.168V
634ps     1.1V       1.058V     1.17V
3ns       1.1V       1.06V      1.17V
[Rising Waveform]
R_fixture= 50.000
V_fixture= 0.0
V_fixture_min= 0.0
V_fixture_max= 0.0
|time   V(typ)   V(min)   V(max)
0s        2.608uV    9.548uV    616.3nV
153ps     168.2uV    32.57uV    7.34mV
192ps     406.1uV    83.85uV    266.5mV
218ps     8.968mV    340.6uV    358.7mV
264ps     254.4mV    76.15uV    403.2mV
300ps     333.4mV    17.56mV    345.6mV
375ps     356.2mV    290.7mV    320.8mV
483ps     302.8mV    335.7mV    319.2mV
618ps     302.1mV    293.5mV    319.2mV
3ns       302.1mV    293.3mV    319.2mV
[Falling Waveform]
R_fixture= 50.000
V_fixture= 1.100
V_fixture_min= 1.060
V_fixture_max= 1.170
|time   V(typ)   V(min)   V(max)
0s        1.1V       1.06V      1.17V
158ps     1.1V       1.06V      1.169V
225ps     1.094V     1.06V      569.6mV
272ps     712.1mV    1.06V      454.6mV
315ps     498.3mV    1.048V     521.2mV
349ps     449mV      867.7mV    545.1mV
411ps     479.5mV    540mV      557.3mV
497ps     511.2mV    443.3mV    559.9mV
679ps     514.4mV    503.3mV    560.3mV
3ns       514.4mV    504.3mV    560.3mV
[Falling Waveform]
R_fixture= 50.000
V_fixture= 0.0
V_fixture_min= 0.0
V_fixture_max= 0.0
|time   V(typ)   V(min)   V(max)
0s        302.1mV    293.3mV    319.2mV
148ps     301.8mV    292.8mV    326.5mV
183ps     313.5mV    292.3mV    103.6mV
199ps     314mV      293.5mV    47.09mV
220ps     254.6mV    298.9mV    17.55mV
252ps     73.62mV    311.2mV    4.372mV
293ps     13.45mV    225.8mV    -5.086mV
350ps     1.888mV    42.72mV    -494.4uV
430ps     -1.675mV   3.252mV    -14.59uV
3ns       2.536uV    9.497uV    296.2nV
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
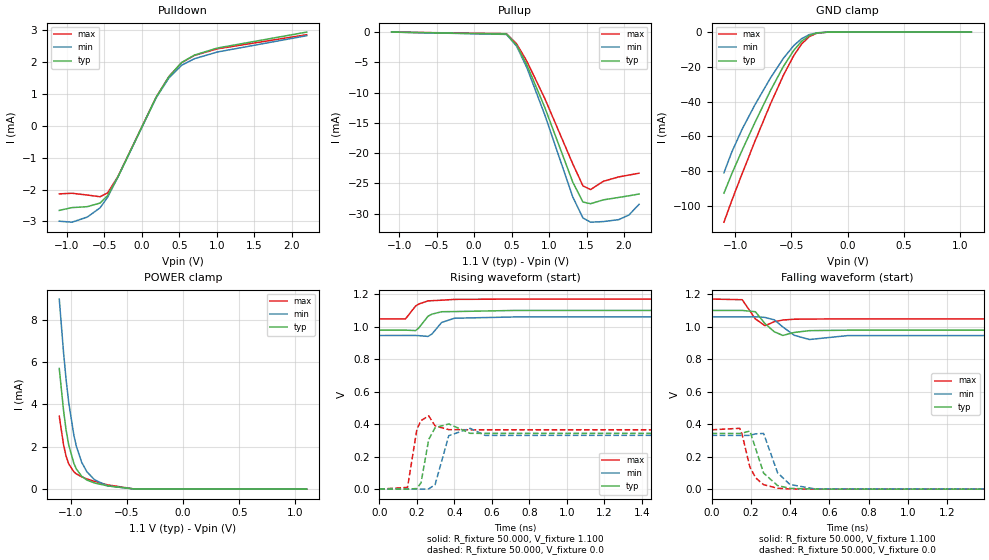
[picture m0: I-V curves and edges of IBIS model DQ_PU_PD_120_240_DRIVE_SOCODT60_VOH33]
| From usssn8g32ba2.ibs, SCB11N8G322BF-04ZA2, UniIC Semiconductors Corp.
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|   Model DQ_PU_PD_120_240_DRIVE_SOCODT60_VOH33
[Model] DQ_PU_PD_120_240_DRIVE_SOCODT60_VOH33
Model_type I/O
Polarity   Inverting
Vinl =  98.000mV
Vinh =  0.268V
Vmeas =  0.183V
Rref =  50.000
Vref =  0.183V
C_comp   1.020pF   1.010pF   1.030pF
[Model Spec]
Vinh   0.268V   0.262V   0.280V
Vinl   98.000mV   92.000mV   0.110V
Vmeas   0.183V   0.177V   0.195V
Vref   0.183V   0.177V   0.195V
Rref   50.000   NA   NA
[Temperature Range]   25.000   0.105k   -40.000
[Voltage Range]   1.100V   1.060V   1.170V
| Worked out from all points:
|   slope of the pulldown table from 0 to 0.165 V, typ, clamps not added: 211 ohm
|   GND clamp passes 1 mA (typ) near -0.30 V on its own axis
|   POWER clamp passes 1 mA (typ) near -0.95 V on its own axis
|   rising waveform, R_fixture 50.000, V_fixture 1.100: 20-80 % time 62ps typ, 59.1ps min, 63.2ps max; typ from 0.978 V to 1.1 V
|   rising waveform, R_fixture 50.000, V_fixture 0.0: 20-80 % time 29.3ps typ, 38.1ps min, 23.8ps max; typ from 0 V to 0.343 V
|   falling waveform, R_fixture 50.000, V_fixture 1.100: 20-80 % time 47.3ps typ, 64.8ps min, 36.3ps max; typ from 1.1 V to 0.978 V
|   falling waveform, R_fixture 50.000, V_fixture 0.0: 20-80 % time 62ps typ, 68.3ps min, 59.5ps max; typ from 0.343 V to 0 V
[Pulldown]
|Voltage   I(typ)   I(min)   I(max)
-1.1V     -2.652mA   -2.992mA   -2.134mA
-930mV    -2.565mA   -3.023mA   -2.114mA
-726mV    -2.535mA   -2.862mA   -2.171mA
-556mV    -2.422mA   -2.572mA   -2.223mA
-454mV    -2.185mA   -2.234mA   -2.101mA
-318mV    -1.604mA   -1.606mA   -1.589mA
192mV     900.6uA    884.3uA    903.8uA
362mV     1.549mA    1.507mA    1.549mA
532mV     1.993mA    1.907mA    1.988mA
702mV     2.225mA    2.111mA    2.215mA
1.008V    2.447mA    2.322mA    2.422mA
2.2V      2.948mA    2.835mA    2.866mA
[Pullup]
|Voltage   I(typ)   I(min)   I(max)
-1.1V     2.1nA      21.95nA    0A
432mV     -337.7uA   -381.6uA   -263.6uA
568mV     -2.186mA   -2.341mA   -1.952mA
704mV     -5.417mA   -5.891mA   -4.827mA
942mV     -12.42mA   -13.65mA   -10.95mA
1.316V    -24.8mA    -27.25mA   -21.78mA
1.452V    -28.09mA   -30.72mA   -25.42mA
1.554V    -28.36mA   -31.42mA   -26.03mA
1.724V    -27.73mA   -31.32mA   -24.66mA
1.928V    -27.33mA   -31mA      -23.94mA
2.064V    -27.06mA   -30.24mA   -23.63mA
2.2V      -26.76mA   -28.47mA   -23.32mA
[GND_clamp]
|Voltage   I(typ)   I(min)   I(max)
-1.1V     -92.78mA   -81.05mA   -109.5mA
-1.031V   -81.73mA   -69.22mA   -97.17mA
-939mV    -68.18mA   -56.02mA   -81.64mA
-824mV    -52mA      -41.83mA   -62.83mA
-686mV    -33.62mA   -26.41mA   -41.32mA
-571mV    -19.76mA   -15.06mA   -24.85mA
-479mV    -10.5mA    -7.76mA    -13.5mA
-410mV    -5.313mA   -3.84mA    -6.916mA
-341mV    -2.007mA   -1.45mA    -2.59mA
-272mV    -506.9uA   -403.5uA   -609.8uA
-180mV    -45.65uA   -51.35uA   -43.55uA
1.1V      0A         0A         0A
[POWER_clamp]
|Voltage   I(typ)   I(min)   I(max)
-1.1V     5.691mA    8.967mA    3.44mA
-1.062V   3.709mA    6.444mA    2.092mA
-1.039V   2.781mA    5.152mA    1.546mA
-1.016V   2.086mA    4.085mA    1.193mA
-970mV    1.21mA     2.539mA    818.5uA
-947mV    943.7uA    2.005mA    716.7uA
-901mV    610.1uA    1.27mA     581.3uA
-855mV    430.7uA    824.1uA    484.6uA
-786mV    289.9uA    439.4uA    366uA
-671mV    155.9uA    155.9uA    203.6uA
-441mV    13.2uA     12.79uA    15.03uA
1.1V      0A         0A         0A
[Ramp]
| variable   typ   min   max
dV/dt_r   0.206/29.379p   0.199/38.232p   0.219/24.028p
dV/dt_f   72.904m/47.402p   68.572m/64.862p   73.268m/36.318p
R_load = 50.000
[Rising Waveform]
R_fixture= 50.000
V_fixture= 1.100
V_fixture_min= 1.060
V_fixture_max= 1.170
|time   V(typ)   V(min)   V(max)
0s        978.5mV    945.7mV    1.048V
140ps     978.8mV    945.9mV    1.048V
194ps     976mV      945.9mV    1.127V
210ps     990.9mV    944.9mV    1.139V
260ps     1.064V     940mV      1.159V
281ps     1.077V     954.6mV    1.16V
333ps     1.092V     1.026V     1.163V
401ps     1.093V     1.052V     1.168V
726ps     1.1V       1.06V      1.17V
3ns       1.1V       1.06V      1.17V
[Rising Waveform]
R_fixture= 50.000
V_fixture= 0.0
V_fixture_min= 0.0
V_fixture_max= 0.0
|time   V(typ)   V(min)   V(max)
0s        5.235uV    19.06uV    1.24uV
151ps     -258.7uV   75.17uV    10.64mV
201ps     3.499mV    -227.9uV   369.5mV
223ps     39.28mV    -442.1uV   421.7mV
264ps     305.5mV    1.543mV    451.1mV
298ps     377.9mV    27.19mV    389.2mV
371ps     401.1mV    329mV      366.1mV
485ps     343.4mV    374mV      365.2mV
565ps     343.2mV    330.8mV    365.2mV
3ns       343.2mV    331.4mV    365.2mV
[Falling Waveform]
R_fixture= 50.000
V_fixture= 1.100
V_fixture_min= 1.060
V_fixture_max= 1.170
|time   V(typ)   V(min)   V(max)
0s        1.1V       1.06V      1.17V
156ps     1.1V       1.06V      1.166V
223ps     1.092V     1.061V     1.048V
272ps     1.019V     1.057V     1.006V
320ps     968.3mV    1.042V     1.031V
363ps     946.2mV    998.1mV    1.041V
421ps     964.5mV    947.1mV    1.046V
498ps     975.7mV    921.1mV    1.047V
693ps     978.4mV    945.1mV    1.048V
3ns       978.5mV    945.7mV    1.048V
[Falling Waveform]
R_fixture= 50.000
V_fixture= 0.0
V_fixture_min= 0.0
V_fixture_max= 0.0
|time   V(typ)   V(min)   V(max)
0s        343.2mV    331.4mV    365.2mV
143ps     342.5mV    330.9mV    374.6mV
154ps     344.4mV    330.6mV    344.2mV
195ps     357.6mV    331.2mV    136.1mV
225ps     247.7mV    340.7mV    68.93mV
265ps     98.77mV    342.9mV    27.68mV
336ps     22.08mV    101.3mV    5.526mV
399ps     5.044mV    28.64mV    1.424mV
524ps     409.7uV    2.027mV    97.36uV
3ns       5.223uV    19.12uV    1.279uV
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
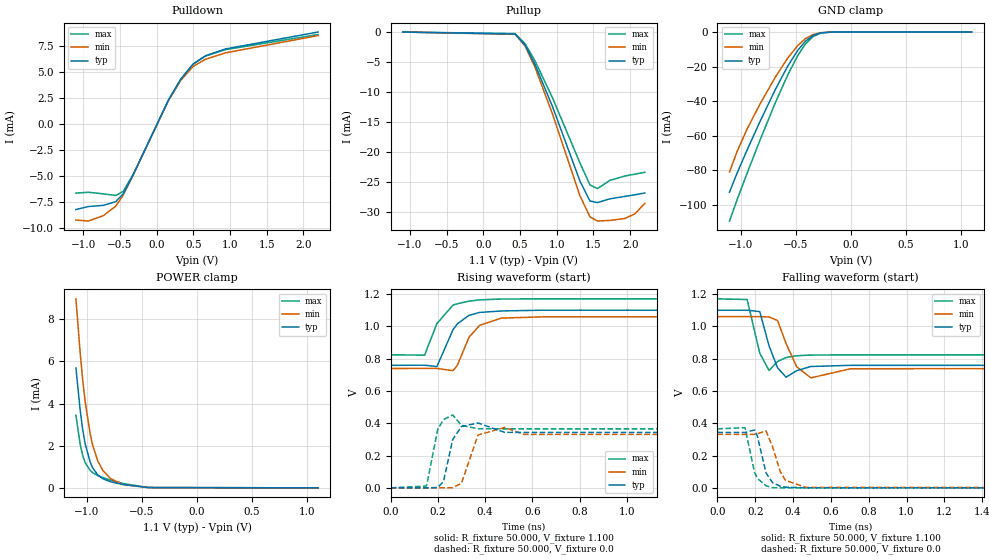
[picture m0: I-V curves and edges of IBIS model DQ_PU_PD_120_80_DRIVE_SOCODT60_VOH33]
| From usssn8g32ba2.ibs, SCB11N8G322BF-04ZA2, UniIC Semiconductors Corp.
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|   Model DQ_PU_PD_120_80_DRIVE_SOCODT60_VOH33
[Model] DQ_PU_PD_120_80_DRIVE_SOCODT60_VOH33
Model_type I/O
Polarity   Inverting
Vinl =  98.000mV
Vinh =  0.268V
Vmeas =  0.183V
Rref =  50.000
Vref =  0.183V
C_comp   1.020pF   1.010pF   1.030pF
[Model Spec]
Vinh   0.268V   0.262V   0.280V
Vinl   98.000mV   92.000mV   0.110V
Vmeas   0.183V   0.177V   0.195V
Vref   0.183V   0.177V   0.195V
Rref   50.000   NA   NA
[Temperature Range]   25.000   0.105k   -40.000
[Voltage Range]   1.100V   1.060V   1.170V
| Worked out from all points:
|   slope of the pulldown table from 0 to 0.165 V, typ, clamps not added: 70.2 ohm
|   GND clamp passes 1 mA (typ) near -0.30 V on its own axis
|   POWER clamp passes 1 mA (typ) near -0.95 V on its own axis
|   rising waveform, R_fixture 50.000, V_fixture 1.100: 20-80 % time 70.9ps typ, 72.6ps min, 69.3ps max; typ from 0.759 V to 1.1 V
|   rising waveform, R_fixture 50.000, V_fixture 0.0: 20-80 % time 29ps typ, 37.4ps min, 23.7ps max; typ from 0 V to 0.343 V
|   falling waveform, R_fixture 50.000, V_fixture 1.100: 20-80 % time 45ps typ, 59.3ps min, 35.7ps max; typ from 1.1 V to 0.759 V
|   falling waveform, R_fixture 50.000, V_fixture 0.0: 20-80 % time 45.7ps typ, 57.9ps min, 42.2ps max; typ from 0.343 V to 0 V
[Pulldown]
|Voltage   I(typ)   I(min)   I(max)
-1.1V     -8.193mA   -9.206mA   -6.618mA
-930mV    -7.906mA   -9.295mA   -6.537mA
-726mV    -7.797mA   -8.78mA    -6.691mA
-556mV    -7.432mA   -7.863mA   -6.841mA
-454mV    -6.673mA   -6.794mA   -6.44mA
-318mV    -4.841mA   -4.838mA   -4.804mA
158mV     2.257mA    2.219mA    2.267mA
328mV     4.302mA    4.194mA    4.305mA
498mV     5.77mA     5.539mA    5.759mA
668mV     6.567mA    6.233mA    6.54mA
940mV     7.217mA    6.841mA    7.152mA
2.2V      8.836mA    8.496mA    8.595mA
[Pullup]
|Voltage   I(typ)   I(min)   I(max)
-1.1V     2.1nA      21.95nA    0A
432mV     -337.7uA   -381.6uA   -263.6uA
568mV     -2.186mA   -2.341mA   -1.952mA
704mV     -5.417mA   -5.891mA   -4.827mA
942mV     -12.42mA   -13.65mA   -10.95mA
1.316V    -24.8mA    -27.25mA   -21.78mA
1.452V    -28.09mA   -30.72mA   -25.42mA
1.554V    -28.36mA   -31.42mA   -26.03mA
1.724V    -27.73mA   -31.32mA   -24.66mA
1.928V    -27.33mA   -31mA      -23.94mA
2.064V    -27.06mA   -30.24mA   -23.63mA
2.2V      -26.76mA   -28.47mA   -23.32mA
[GND_clamp]
|Voltage   I(typ)   I(min)   I(max)
-1.1V     -92.78mA   -81.05mA   -109.5mA
-1.031V   -81.73mA   -69.22mA   -97.17mA
-939mV    -68.18mA   -56.02mA   -81.64mA
-824mV    -52mA      -41.83mA   -62.83mA
-686mV    -33.62mA   -26.41mA   -41.32mA
-571mV    -19.76mA   -15.06mA   -24.85mA
-479mV    -10.5mA    -7.76mA    -13.5mA
-410mV    -5.313mA   -3.84mA    -6.916mA
-341mV    -2.007mA   -1.45mA    -2.59mA
-272mV    -506.9uA   -403.5uA   -609.8uA
-180mV    -45.65uA   -51.35uA   -43.55uA
1.1V      0A         0A         0A
[POWER_clamp]
|Voltage   I(typ)   I(min)   I(max)
-1.1V     5.691mA    8.967mA    3.44mA
-1.062V   3.709mA    6.444mA    2.092mA
-1.039V   2.781mA    5.152mA    1.546mA
-1.016V   2.086mA    4.085mA    1.193mA
-970mV    1.21mA     2.539mA    818.5uA
-947mV    943.7uA    2.005mA    716.7uA
-901mV    610.1uA    1.27mA     581.3uA
-855mV    430.7uA    824.1uA    484.6uA
-786mV    289.9uA    439.4uA    366uA
-671mV    155.9uA    155.9uA    203.6uA
-441mV    13.2uA     12.79uA    15.03uA
1.1V      0A         0A         0A
[Ramp]
| variable   typ   min   max
dV/dt_r   0.206/29.169p   0.199/37.568p   0.219/23.888p
dV/dt_f   0.205/45.182p   0.193/59.296p   0.208/35.744p
R_load = 50.000
[Rising Waveform]
R_fixture= 50.000
V_fixture= 1.100
V_fixture_min= 1.060
V_fixture_max= 1.170
|time   V(typ)   V(min)   V(max)
0s        758.6mV    738.8mV    823.3mV
144ps     759.4mV    739.2mV    821.8mV
196ps     750.9mV    739.5mV    1.017V
264ps     978.1mV    725.4mV    1.131V
283ps     1.016V     759.5mV    1.14V
332ps     1.068V     932.5mV    1.156V
377ps     1.086V     1.006V     1.164V
469ps     1.095V     1.051V     1.169V
654ps     1.1V       1.059V     1.17V
3ns       1.1V       1.06V      1.17V
[Rising Waveform]
R_fixture= 50.000
V_fixture= 0.0
V_fixture_min= 0.0
V_fixture_max= 0.0
|time   V(typ)   V(min)   V(max)
0s        3.732uV    13.63uV    882.6nV
152ps     -136.6uV   47.54uV    10.85mV
200ps     2.117mV    -78.95uV   364.1mV
224ps     39.68mV    -107.9uV   422.5mV
263ps     299.5mV    732.7uV    451.1mV
300ps     379.5mV    27.96mV    386.5mV
370ps     401.6mV    326.8mV    366.1mV
483ps     343.5mV    373.8mV    365.2mV
564ps     343.2mV    330.8mV    365.2mV
3ns       343.2mV    331.4mV    365.2mV
[Falling Waveform]
R_fixture= 50.000
V_fixture= 1.100
V_fixture_min= 1.060
V_fixture_max= 1.170
|time   V(typ)   V(min)   V(max)
0s        1.1V       1.06V      1.17V
157ps     1.1V       1.06V      1.166V
224ps     1.091V     1.06V      833.6mV
273ps     879mV      1.058V     726.6mV
318ps     743.1mV    1.036V     782.5mV
363ps     685.1mV    893.4mV    806.9mV
419ps     725.4mV    750mV      817.9mV
494ps     751.2mV    680.8mV    822.1mV
704ps     758.5mV    737.4mV    823.3mV
3ns       758.6mV    738.8mV    823.3mV
[Falling Waveform]
R_fixture= 50.000
V_fixture= 0.0
V_fixture_min= 0.0
V_fixture_max= 0.0
|time   V(typ)   V(min)   V(max)
0s        343.2mV    331.4mV    365.2mV
146ps     342.8mV    330.8mV    372.4mV
196ps     358.1mV    331.3mV    97.18mV
211ps     321.5mV    334.9mV    58.93mV
257ps     91.69mV    352.3mV    13mV
292ps     31.65mV    252.4mV    937uV
332ps     10.02mV    101.5mV    220.6uV
359ps     4.456mV    46.89mV    116uV
466ps     -135.2uV   3.242mV    6.223uV
3ns       3.393uV    13.51uV    769.7nV
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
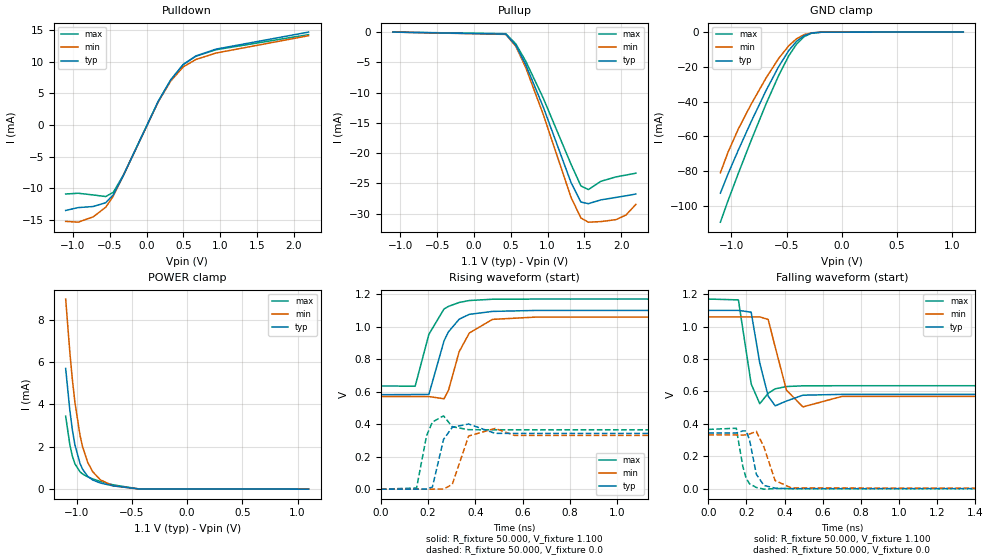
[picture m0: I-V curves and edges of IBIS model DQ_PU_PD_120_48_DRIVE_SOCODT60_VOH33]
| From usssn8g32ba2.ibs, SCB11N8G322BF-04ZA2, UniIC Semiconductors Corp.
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|   Model DQ_PU_PD_120_48_DRIVE_SOCODT60_VOH33
[Model] DQ_PU_PD_120_48_DRIVE_SOCODT60_VOH33
Model_type I/O
Polarity   Inverting
Vinl =  98.000mV
Vinh =  0.268V
Vmeas =  0.183V
Rref =  50.000
Vref =  0.183V
C_comp   1.020pF   1.010pF   1.030pF
[Model Spec]
Vinh   0.268V   0.262V   0.280V
Vinl   98.000mV   92.000mV   0.110V
Vmeas   0.183V   0.177V   0.195V
Vref   0.183V   0.177V   0.195V
Rref   50.000   NA   NA
[Temperature Range]   25.000   0.105k   -40.000
[Voltage Range]   1.100V   1.060V   1.170V
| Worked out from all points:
|   slope of the pulldown table from 0 to 0.165 V, typ, clamps not added: 42.3 ohm
|   GND clamp passes 1 mA (typ) near -0.30 V on its own axis
|   POWER clamp passes 1 mA (typ) near -0.95 V on its own axis
|   rising waveform, R_fixture 50.000, V_fixture 1.100: 20-80 % time 74.5ps typ, 77.3ps min, 72.2ps max; typ from 0.582 V to 1.1 V
|   rising waveform, R_fixture 50.000, V_fixture 0.0: 20-80 % time 28.7ps typ, 37.2ps min, 23.5ps max; typ from 0 V to 0.343 V
|   falling waveform, R_fixture 50.000, V_fixture 1.100: 20-80 % time 42.7ps typ, 56.2ps min, 34.6ps max; typ from 1.1 V to 0.582 V
|   falling waveform, R_fixture 50.000, V_fixture 0.0: 20-80 % time 37ps typ, 52.5ps min, 32.8ps max; typ from 0.343 V to 0 V
[Pulldown]
|Voltage   I(typ)   I(min)   I(max)
-1.1V     -13.51mA   -15.24mA   -10.91mA
-930mV    -13.06mA   -15.37mA   -10.79mA
-726mV    -12.89mA   -14.52mA   -11.06mA
-556mV    -12.29mA   -13.01mA   -11.31mA
-454mV    -11.04mA   -11.25mA   -10.65mA
-318mV    -8.03mA    -8.027mA   -7.964mA
158mV     3.751mA    3.687mA    3.768mA
328mV     7.153mA    6.973mA    7.158mA
498mV     9.598mA    9.214mA    9.581mA
668mV     10.93mA    10.37mA    10.89mA
940mV     12.01mA    11.39mA    11.91mA
2.2V      14.71mA    14.14mA    14.31mA
[Pullup]
|Voltage   I(typ)   I(min)   I(max)
-1.1V     2.1nA      21.95nA    0A
432mV     -337.7uA   -381.6uA   -263.6uA
568mV     -2.186mA   -2.341mA   -1.952mA
704mV     -5.417mA   -5.891mA   -4.827mA
942mV     -12.42mA   -13.65mA   -10.95mA
1.316V    -24.8mA    -27.25mA   -21.78mA
1.452V    -28.09mA   -30.72mA   -25.42mA
1.554V    -28.36mA   -31.42mA   -26.03mA
1.724V    -27.73mA   -31.32mA   -24.66mA
1.928V    -27.33mA   -31mA      -23.94mA
2.064V    -27.06mA   -30.24mA   -23.63mA
2.2V      -26.76mA   -28.47mA   -23.32mA
[GND_clamp]
|Voltage   I(typ)   I(min)   I(max)
-1.1V     -92.78mA   -81.05mA   -109.5mA
-1.031V   -81.73mA   -69.22mA   -97.17mA
-939mV    -68.18mA   -56.02mA   -81.64mA
-824mV    -52mA      -41.83mA   -62.83mA
-686mV    -33.62mA   -26.41mA   -41.32mA
-571mV    -19.76mA   -15.06mA   -24.85mA
-479mV    -10.5mA    -7.76mA    -13.5mA
-410mV    -5.313mA   -3.84mA    -6.916mA
-341mV    -2.007mA   -1.45mA    -2.59mA
-272mV    -506.9uA   -403.5uA   -609.8uA
-180mV    -45.65uA   -51.35uA   -43.55uA
1.1V      0A         0A         0A
[POWER_clamp]
|Voltage   I(typ)   I(min)   I(max)
-1.1V     5.691mA    8.967mA    3.44mA
-1.062V   3.709mA    6.444mA    2.092mA
-1.039V   2.781mA    5.152mA    1.546mA
-1.016V   2.086mA    4.085mA    1.193mA
-970mV    1.21mA     2.539mA    818.5uA
-947mV    943.7uA    2.005mA    716.7uA
-901mV    610.1uA    1.27mA     581.3uA
-855mV    430.7uA    824.1uA    484.6uA
-786mV    289.9uA    439.4uA    366uA
-671mV    155.9uA    155.9uA    203.6uA
-441mV    13.2uA     12.79uA    15.03uA
1.1V      0A         0A         0A
[Ramp]
| variable   typ   min   max
dV/dt_r   0.206/28.866p   0.199/37.182p   0.219/23.794p
dV/dt_f   0.311/42.802p   0.294/56.255p   0.321/34.634p
R_load = 50.000
[Rising Waveform]
R_fixture= 50.000
V_fixture= 1.100
V_fixture_min= 1.060
V_fixture_max= 1.170
|time   V(typ)   V(min)   V(max)
0s        581.6mV    569.9mV    635mV
145ps     582.5mV    570.5mV    633.8mV
203ps     583.2mV    569.8mV    953mV
267ps     912.5mV    556.3mV    1.109V
286ps     968.6mV    608.6mV    1.125V
331ps     1.046V     845.8mV    1.149V
374ps     1.076V     961.1mV    1.161V
472ps     1.094V     1.045V     1.169V
655ps     1.1V       1.059V     1.17V
3ns       1.1V       1.06V      1.17V
[Rising Waveform]
R_fixture= 50.000
V_fixture= 0.0
V_fixture_min= 0.0
V_fixture_max= 0.0
|time   V(typ)   V(min)   V(max)
0s        2.898uV    10.6uV     685nV
151ps     18.65uV    38.96uV    7.153mV
193ps     600.2uV    40.07uV    328.3mV
218ps     13.39mV    154.7uV    413.3mV
265ps     306.2mV    373.9uV    451.1mV
302ps     380.7mV    29.64mV    384mV
371ps     401mV      327.2mV    366.1mV
483ps     343.5mV    373.8mV    365.2mV
565ps     343.2mV    330.8mV    365.2mV
3ns       343.2mV    331.4mV    365.2mV
[Falling Waveform]
R_fixture= 50.000
V_fixture= 1.100
V_fixture_min= 1.060
V_fixture_max= 1.170
|time   V(typ)   V(min)   V(max)
0s        1.1V       1.06V      1.17V
158ps     1.1V       1.06V      1.165V
225ps     1.089V     1.06V      645.6mV
270ps     775.3mV    1.06V      524mV
314ps     570.7mV    1.044V     588.2mV
351ps     510.9mV    872.9mV    615.8mV
410ps     540.7mV    607.4mV    630mV
496ps     576.4mV    504.2mV    634.3mV
700ps     581.5mV    568.8mV    635mV
3ns       581.6mV    569.9mV    635mV
[Falling Waveform]
R_fixture= 50.000
V_fixture= 0.0
V_fixture_min= 0.0
V_fixture_max= 0.0
|time   V(typ)   V(min)   V(max)
0s        343.2mV    331.4mV    365.2mV
147ps     342.8mV    330.8mV    372.4mV
181ps     356.1mV    330.2mV    137.7mV
199ps     356.1mV    331.7mV    61.72mV
217ps     297.4mV    336.9mV    28.59mV
252ps     88.29mV    352.9mV    6.827mV
292ps     19.08mV    255.8mV    -3.755mV
350ps     2.734mV    49.79mV    -458uV
436ps     -1.09mV    3.672mV    -14.38uV
3ns       -732.6nV   10.56uV    284.7nV
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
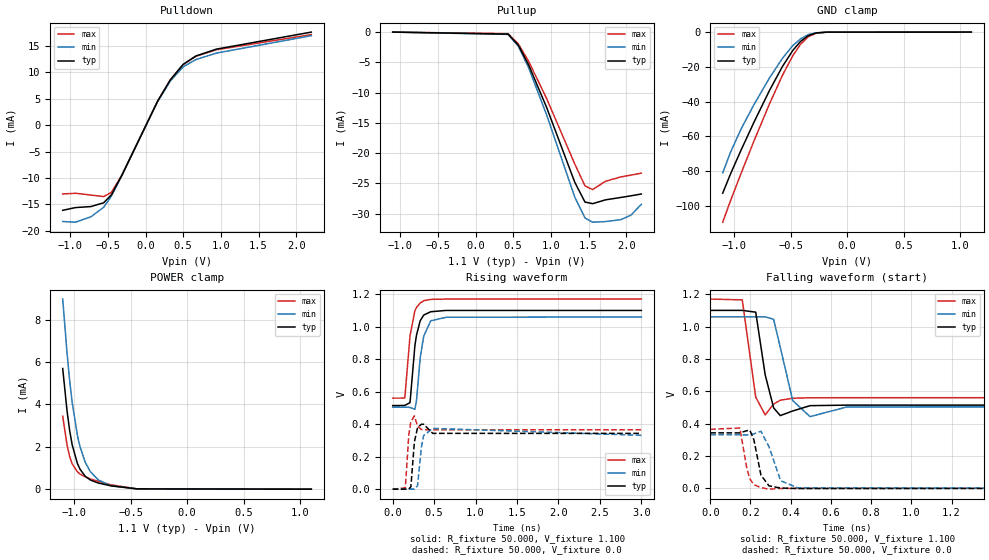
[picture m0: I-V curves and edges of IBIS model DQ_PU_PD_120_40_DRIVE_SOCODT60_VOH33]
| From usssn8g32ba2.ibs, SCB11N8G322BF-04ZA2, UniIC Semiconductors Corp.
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|   Model DQ_PU_PD_120_40_DRIVE_SOCODT60_VOH33
[Model] DQ_PU_PD_120_40_DRIVE_SOCODT60_VOH33
Model_type I/O
Polarity   Inverting
Vinl =  98.000mV
Vinh =  0.268V
Vmeas =  0.183V
Rref =  50.000
Vref =  0.183V
C_comp   1.020pF   1.010pF   1.030pF
[Model Spec]
Vinh   0.268V   0.262V   0.280V
Vinl   98.000mV   92.000mV   0.110V
Vmeas   0.183V   0.177V   0.195V
Vref   0.183V   0.177V   0.195V
Rref   50.000   NA   NA
[Temperature Range]   25.000   0.105k   -40.000
[Voltage Range]   1.100V   1.060V   1.170V
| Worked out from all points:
|   slope of the pulldown table from 0 to 0.165 V, typ, clamps not added: 35.3 ohm
|   GND clamp passes 1 mA (typ) near -0.30 V on its own axis
|   POWER clamp passes 1 mA (typ) near -0.95 V on its own axis
|   rising waveform, R_fixture 50.000, V_fixture 1.100: 20-80 % time 75.6ps typ, 78.8ps min, 73.1ps max; typ from 0.514 V to 1.1 V
|   rising waveform, R_fixture 50.000, V_fixture 0.0: 20-80 % time 28.6ps typ, 37ps min, 23.5ps max; typ from 0 V to 0.343 V
|   falling waveform, R_fixture 50.000, V_fixture 1.100: 20-80 % time 40.9ps typ, 54ps min, 33.5ps max; typ from 1.1 V to 0.514 V
|   falling waveform, R_fixture 50.000, V_fixture 0.0: 20-80 % time 34.3ps typ, 51.6ps min, 29.8ps max; typ from 0.343 V to 0 V
[Pulldown]
|Voltage   I(typ)   I(min)   I(max)
-1.1V     -16.13mA   -18.25mA   -13.03mA
-930mV    -15.61mA   -18.38mA   -12.9mA
-726mV    -15.42mA   -17.36mA   -13.24mA
-556mV    -14.7mA    -15.55mA   -13.53mA
-454mV    -13.2mA    -13.45mA   -12.73mA
-318mV    -9.609mA   -9.606mA   -9.529mA
158mV     4.492mA    4.415mA    4.512mA
328mV     8.568mA    8.352mA    8.576mA
498mV     11.5mA     11.04mA    11.48mA
668mV     13.1mA     12.43mA    13.05mA
940mV     14.4mA     13.65mA    14.28mA
2.2V      17.63mA    16.95mA    17.16mA
[Pullup]
|Voltage   I(typ)   I(min)   I(max)
-1.1V     2.1nA      21.95nA    0A
432mV     -337.7uA   -381.6uA   -263.6uA
568mV     -2.186mA   -2.341mA   -1.952mA
704mV     -5.417mA   -5.891mA   -4.827mA
942mV     -12.42mA   -13.65mA   -10.95mA
1.316V    -24.8mA    -27.25mA   -21.78mA
1.452V    -28.09mA   -30.72mA   -25.42mA
1.554V    -28.36mA   -31.42mA   -26.03mA
1.724V    -27.73mA   -31.32mA   -24.66mA
1.928V    -27.33mA   -31mA      -23.94mA
2.064V    -27.06mA   -30.24mA   -23.63mA
2.2V      -26.76mA   -28.47mA   -23.32mA
[GND_clamp]
|Voltage   I(typ)   I(min)   I(max)
-1.1V     -92.78mA   -81.05mA   -109.5mA
-1.031V   -81.73mA   -69.22mA   -97.17mA
-939mV    -68.18mA   -56.02mA   -81.64mA
-824mV    -52mA      -41.83mA   -62.83mA
-686mV    -33.62mA   -26.41mA   -41.32mA
-571mV    -19.76mA   -15.06mA   -24.85mA
-479mV    -10.5mA    -7.76mA    -13.5mA
-410mV    -5.313mA   -3.84mA    -6.916mA
-341mV    -2.007mA   -1.45mA    -2.59mA
-272mV    -506.9uA   -403.5uA   -609.8uA
-180mV    -45.65uA   -51.35uA   -43.55uA
1.1V      0A         0A         0A
[POWER_clamp]
|Voltage   I(typ)   I(min)   I(max)
-1.1V     5.691mA    8.967mA    3.44mA
-1.062V   3.709mA    6.444mA    2.092mA
-1.039V   2.781mA    5.152mA    1.546mA
-1.016V   2.086mA    4.085mA    1.193mA
-970mV    1.21mA     2.539mA    818.5uA
-947mV    943.7uA    2.005mA    716.7uA
-901mV    610.1uA    1.27mA     581.3uA
-855mV    430.7uA    824.1uA    484.6uA
-786mV    289.9uA    439.4uA    366uA
-671mV    155.9uA    155.9uA    203.6uA
-441mV    13.2uA     12.79uA    15.03uA
1.1V      0A         0A         0A
[Ramp]
| variable   typ   min   max
dV/dt_r   0.206/28.662p   0.199/37.093p   0.219/23.735p
dV/dt_f   0.351/40.993p   0.333/54.014p   0.366/33.500p
R_load = 50.000
[Rising Waveform]
R_fixture= 50.000
V_fixture= 1.100
V_fixture_min= 1.060
V_fixture_max= 1.170
|time   V(typ)   V(min)   V(max)
0s        514.4mV    504.3mV    560.3mV
146ps     515.3mV    504.9mV    560.5mV
209ps     532.7mV    503.2mV    944.3mV
268ps     884.6mV    491.9mV    1.099V
287ps     947.8mV    544.8mV    1.118V
332ps     1.037V     810.1mV    1.146V
375ps     1.072V     942.9mV    1.16V
459ps     1.092V     1.036V     1.168V
644ps     1.1V       1.058V     1.17V
3ns       1.1V       1.06V      1.17V
[Rising Waveform]
R_fixture= 50.000
V_fixture= 0.0
V_fixture_min= 0.0
V_fixture_max= 0.0
|time   V(typ)   V(min)   V(max)
0s        2.608uV    9.548uV    616.3nV
152ps     89.21uV    40.42uV    8.194mV
194ps     632.6uV    65.08uV    332.9mV
219ps     14.69mV    261.1uV    414.7mV
262ps     292.2mV    294.4uV    450.8mV
300ps     379mV      21.7mV     386.4mV
346ps     399.5mV    258.1mV    367.7mV
373ps     399.6mV    329.8mV    366mV
484ps     343.4mV    374mV      365.2mV
3ns       343.2mV    331.4mV    365.2mV
[Falling Waveform]
R_fixture= 50.000
V_fixture= 1.100
V_fixture_min= 1.060
V_fixture_max= 1.170
|time   V(typ)   V(min)   V(max)
0s        1.1V       1.06V      1.17V
159ps     1.1V       1.06V      1.165V
226ps     1.089V     1.06V      563.8mV
273ps     702.4mV    1.06V      454.2mV
315ps     497.7mV    1.045V     521.2mV
348ps     449.7mV    872.3mV    544.7mV
410ps     478.3mV    542.5mV    557.2mV
496ps     511.1mV    443.4mV    559.9mV
680ps     514.4mV    503.3mV    560.3mV
3ns       514.4mV    504.3mV    560.3mV
[Falling Waveform]
R_fixture= 50.000
V_fixture= 0.0
V_fixture_min= 0.0
V_fixture_max= 0.0
|time   V(typ)   V(min)   V(max)
0s        343.2mV    331.4mV    365.2mV
147ps     342.8mV    330.8mV    373mV
182ps     356.6mV    330.2mV    122.6mV
197ps     358.9mV    331.4mV    58.12mV
217ps     299.7mV    336.9mV    22.51mV
252ps     81.86mV    352.8mV    4.826mV
292ps     15.4mV     257mV      -4.965mV
350ps     2.062mV    46.82mV    -497.4uV
436ps     -1.258mV   3.011mV    -11.11uV
3ns       2.476uV    9.495uV    177.9nV
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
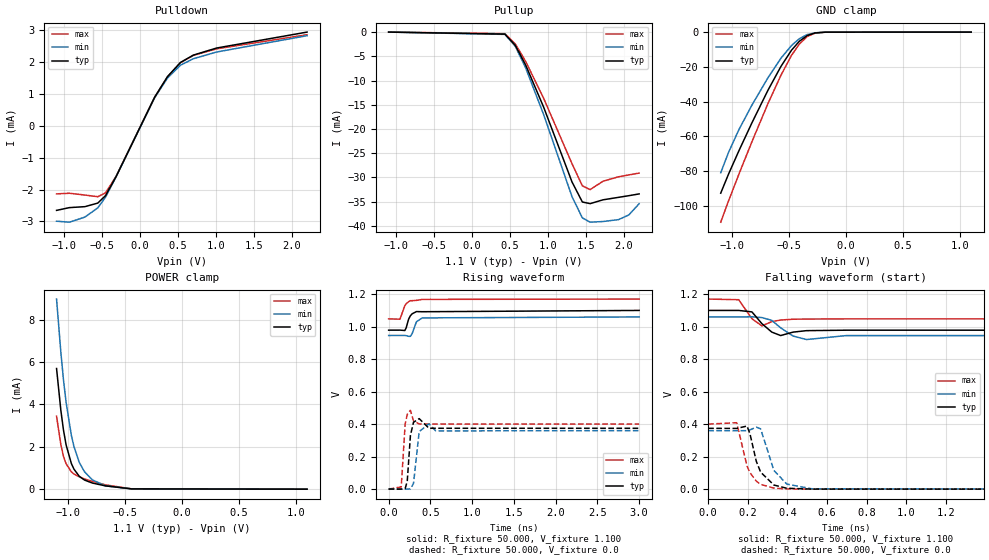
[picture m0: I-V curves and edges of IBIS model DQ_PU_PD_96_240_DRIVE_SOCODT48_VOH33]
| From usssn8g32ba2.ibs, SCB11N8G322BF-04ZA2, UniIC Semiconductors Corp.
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|   Model DQ_PU_PD_96_240_DRIVE_SOCODT48_VOH33
[Model] DQ_PU_PD_96_240_DRIVE_SOCODT48_VOH33
Model_type I/O
Polarity   Inverting
Vinl =  98.000mV
Vinh =  0.268V
Vmeas =  0.183V
Rref =  50.000
Vref =  0.183V
C_comp   1.020pF   1.010pF   1.030pF
[Model Spec]
Vinh   0.268V   0.262V   0.280V
Vinl   98.000mV   92.000mV   0.110V
Vmeas   0.183V   0.177V   0.195V
Vref   0.183V   0.177V   0.195V
Rref   50.000   NA   NA
[Temperature Range]   25.000   0.105k   -40.000
[Voltage Range]   1.100V   1.060V   1.170V
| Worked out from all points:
|   slope of the pulldown table from 0 to 0.165 V, typ, clamps not added: 211 ohm
|   GND clamp passes 1 mA (typ) near -0.30 V on its own axis
|   POWER clamp passes 1 mA (typ) near -0.95 V on its own axis
|   rising waveform, R_fixture 50.000, V_fixture 1.100: 20-80 % time 58.7ps typ, 54.4ps min, 60.8ps max; typ from 0.978 V to 1.1 V
|   rising waveform, R_fixture 50.000, V_fixture 0.0: 20-80 % time 28.1ps typ, 36.9ps min, 22.8ps max; typ from 0 V to 0.374 V
|   falling waveform, R_fixture 50.000, V_fixture 1.100: 20-80 % time 48.1ps typ, 67.5ps min, 36.6ps max; typ from 1.1 V to 0.978 V
|   falling waveform, R_fixture 50.000, V_fixture 0.0: 20-80 % time 61.8ps typ, 67.8ps min, 59.4ps max; typ from 0.374 V to 0 V
[Pulldown]
|Voltage   I(typ)   I(min)   I(max)
-1.1V     -2.652mA   -2.992mA   -2.134mA
-930mV    -2.565mA   -3.023mA   -2.114mA
-726mV    -2.535mA   -2.862mA   -2.171mA
-556mV    -2.422mA   -2.572mA   -2.223mA
-454mV    -2.185mA   -2.234mA   -2.101mA
-318mV    -1.604mA   -1.606mA   -1.589mA
192mV     900.6uA    884.3uA    903.8uA
362mV     1.549mA    1.507mA    1.549mA
532mV     1.993mA    1.907mA    1.988mA
702mV     2.225mA    2.111mA    2.215mA
1.008V    2.447mA    2.322mA    2.422mA
2.2V      2.948mA    2.835mA    2.866mA
[Pullup]
|Voltage   I(typ)   I(min)   I(max)
-1.1V     2.6nA      27.46nA    0A
432mV     -421.9uA   -476.8uA   -329.3uA
568mV     -2.729mA   -2.923mA   -2.437mA
704mV     -6.762mA   -7.352mA   -6.026mA
942mV     -15.5mA    -17.03mA   -13.67mA
1.316V    -30.95mA   -34mA      -27.19mA
1.452V    -35.08mA   -38.36mA   -31.74mA
1.554V    -35.42mA   -39.25mA   -32.53mA
1.724V    -34.63mA   -39.11mA   -30.79mA
1.928V    -34.12mA   -38.72mA   -29.88mA
2.064V    -33.78mA   -37.75mA   -29.49mA
2.2V      -33.41mA   -35.44mA   -29.11mA
[GND_clamp]
|Voltage   I(typ)   I(min)   I(max)
-1.1V     -92.78mA   -81.05mA   -109.5mA
-1.031V   -81.73mA   -69.22mA   -97.17mA
-939mV    -68.18mA   -56.02mA   -81.64mA
-824mV    -52mA      -41.83mA   -62.83mA
-686mV    -33.62mA   -26.41mA   -41.32mA
-571mV    -19.76mA   -15.06mA   -24.85mA
-479mV    -10.5mA    -7.76mA    -13.5mA
-410mV    -5.313mA   -3.84mA    -6.916mA
-341mV    -2.007mA   -1.45mA    -2.59mA
-272mV    -506.9uA   -403.5uA   -609.8uA
-180mV    -45.65uA   -51.35uA   -43.55uA
1.1V      0A         0A         0A
[POWER_clamp]
|Voltage   I(typ)   I(min)   I(max)
-1.1V     5.691mA    8.967mA    3.44mA
-1.062V   3.709mA    6.444mA    2.092mA
-1.039V   2.781mA    5.152mA    1.546mA
-1.016V   2.086mA    4.085mA    1.193mA
-970mV    1.21mA     2.539mA    818.5uA
-947mV    943.7uA    2.005mA    716.7uA
-901mV    610.1uA    1.27mA     581.3uA
-855mV    430.7uA    824.1uA    484.6uA
-786mV    289.9uA    439.4uA    366uA
-671mV    155.9uA    155.9uA    203.6uA
-441mV    13.2uA     12.79uA    15.03uA
1.1V      0A         0A         0A
[Ramp]
| variable   typ   min   max
dV/dt_r   0.225/28.092p   0.216/37.208p   0.240/22.871p
dV/dt_f   72.904m/48.130p   68.572m/67.487p   73.268m/36.590p
R_load = 50.000
[Rising Waveform]
R_fixture= 50.000
V_fixture= 1.100
V_fixture_min= 1.060
V_fixture_max= 1.170
|time   V(typ)   V(min)   V(max)
0s        978.5mV    945.7mV    1.048V
136ps     978.8mV    945.8mV    1.046V
194ps     976.4mV    945.8mV    1.13V
210ps     992.9mV    944.7mV    1.141V
239ps     1.046V     940.7mV    1.154V
260ps     1.067V     940.2mV    1.16V
281ps     1.079V     956.5mV    1.16V
333ps     1.093V     1.03V      1.162V
402ps     1.092V     1.054V     1.168V
3ns       1.1V       1.06V      1.17V
[Rising Waveform]
R_fixture= 50.000
V_fixture= 0.0
V_fixture_min= 0.0
V_fixture_max= 0.0
|time   V(typ)   V(min)   V(max)
0s        5.235uV    19.06uV    1.24uV
151ps     -344uV     85.89uV    13.24mV
198ps     3.233mV    -253.6uV   400.3mV
223ps     48.5mV     -597.7uV   460mV
261ps     330.5mV    1.26mV     485.2mV
298ps     411.2mV    34.95mV    419.3mV
366ps     433.7mV    353.8mV    400.8mV
483ps     374.4mV    401.9mV    400.4mV
565ps     374.4mV    358.2mV    400.4mV
3ns       374.4mV    360.1mV    400.4mV
[Falling Waveform]
R_fixture= 50.000
V_fixture= 1.100
V_fixture_min= 1.060
V_fixture_max= 1.170
|time   V(typ)   V(min)   V(max)
0s        1.1V       1.06V      1.17V
154ps     1.1V       1.06V      1.166V
221ps     1.091V     1.061V     1.049V
271ps     1.019V     1.056V     1.005V
321ps     966.9mV    1.039V     1.031V
366ps     945.4mV    993mV      1.041V
429ps     966.6mV    942.2mV    1.046V
497ps     975.6mV    920.9mV    1.047V
696ps     978.4mV    945.1mV    1.048V
3ns       978.5mV    945.7mV    1.048V
[Falling Waveform]
R_fixture= 50.000
V_fixture= 0.0
V_fixture_min= 0.0
V_fixture_max= 0.0
|time   V(typ)   V(min)   V(max)
0s        374.4mV    360.1mV    400.4mV
144ps     373.8mV    359.4mV    408.9mV
196ps     388.6mV    360.2mV    142.6mV
211ps     341mV      364.7mV    101.3mV
243ps     171.3mV    382.1mV    49.19mV
265ps     104.5mV    371mV      29.66mV
332ps     25.4mV     115.2mV    6.481mV
397ps     5.655mV    31.09mV    1.604mV
525ps     429.4uV    2.087mV    102.5uV
3ns       5.256uV    19.12uV    1.289uV
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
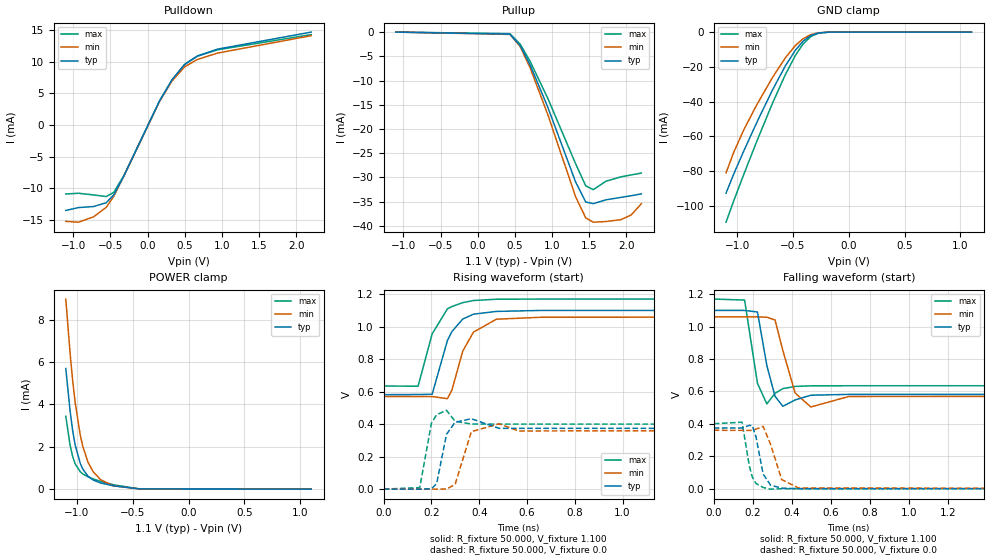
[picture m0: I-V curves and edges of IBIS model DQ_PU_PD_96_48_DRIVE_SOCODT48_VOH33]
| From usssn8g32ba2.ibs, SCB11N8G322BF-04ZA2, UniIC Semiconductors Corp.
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|   Model DQ_PU_PD_96_48_DRIVE_SOCODT48_VOH33
[Model] DQ_PU_PD_96_48_DRIVE_SOCODT48_VOH33
Model_type I/O
Polarity   Inverting
Vinl =  98.000mV
Vinh =  0.268V
Vmeas =  0.183V
Rref =  50.000
Vref =  0.183V
C_comp   1.020pF   1.010pF   1.030pF
[Model Spec]
Vinh   0.268V   0.262V   0.280V
Vinl   98.000mV   92.000mV   0.110V
Vmeas   0.183V   0.177V   0.195V
Vref   0.183V   0.177V   0.195V
Rref   50.000   NA   NA
[Temperature Range]   25.000   0.105k   -40.000
[Voltage Range]   1.100V   1.060V   1.170V
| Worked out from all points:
|   slope of the pulldown table from 0 to 0.165 V, typ, clamps not added: 42.3 ohm
|   GND clamp passes 1 mA (typ) near -0.30 V on its own axis
|   POWER clamp passes 1 mA (typ) near -0.95 V on its own axis
|   rising waveform, R_fixture 50.000, V_fixture 1.100: 20-80 % time 74.2ps typ, 76.7ps min, 72ps max; typ from 0.582 V to 1.1 V
|   rising waveform, R_fixture 50.000, V_fixture 0.0: 20-80 % time 27.6ps typ, 35.9ps min, 22.6ps max; typ from 0 V to 0.374 V
|   falling waveform, R_fixture 50.000, V_fixture 1.100: 20-80 % time 42.9ps typ, 56.4ps min, 34.6ps max; typ from 1.1 V to 0.582 V
|   falling waveform, R_fixture 50.000, V_fixture 0.0: 20-80 % time 37.5ps typ, 53.1ps min, 33.2ps max; typ from 0.374 V to 0 V
[Pulldown]
|Voltage   I(typ)   I(min)   I(max)
-1.1V     -13.51mA   -15.24mA   -10.91mA
-930mV    -13.06mA   -15.37mA   -10.79mA
-726mV    -12.89mA   -14.52mA   -11.06mA
-556mV    -12.29mA   -13.01mA   -11.31mA
-454mV    -11.04mA   -11.25mA   -10.65mA
-318mV    -8.03mA    -8.027mA   -7.964mA
158mV     3.751mA    3.687mA    3.768mA
328mV     7.153mA    6.973mA    7.158mA
498mV     9.598mA    9.214mA    9.581mA
668mV     10.93mA    10.37mA    10.89mA
940mV     12.01mA    11.39mA    11.91mA
2.2V      14.71mA    14.14mA    14.31mA
[Pullup]
|Voltage   I(typ)   I(min)   I(max)
-1.1V     2.6nA      27.46nA    0A
432mV     -421.9uA   -476.8uA   -329.3uA
568mV     -2.729mA   -2.923mA   -2.437mA
704mV     -6.762mA   -7.352mA   -6.026mA
942mV     -15.5mA    -17.03mA   -13.67mA
1.316V    -30.95mA   -34mA      -27.19mA
1.452V    -35.08mA   -38.36mA   -31.74mA
1.554V    -35.42mA   -39.25mA   -32.53mA
1.724V    -34.63mA   -39.11mA   -30.79mA
1.928V    -34.12mA   -38.72mA   -29.88mA
2.064V    -33.78mA   -37.75mA   -29.49mA
2.2V      -33.41mA   -35.44mA   -29.11mA
[GND_clamp]
|Voltage   I(typ)   I(min)   I(max)
-1.1V     -92.78mA   -81.05mA   -109.5mA
-1.031V   -81.73mA   -69.22mA   -97.17mA
-939mV    -68.18mA   -56.02mA   -81.64mA
-824mV    -52mA      -41.83mA   -62.83mA
-686mV    -33.62mA   -26.41mA   -41.32mA
-571mV    -19.76mA   -15.06mA   -24.85mA
-479mV    -10.5mA    -7.76mA    -13.5mA
-410mV    -5.313mA   -3.84mA    -6.916mA
-341mV    -2.007mA   -1.45mA    -2.59mA
-272mV    -506.9uA   -403.5uA   -609.8uA
-180mV    -45.65uA   -51.35uA   -43.55uA
1.1V      0A         0A         0A
[POWER_clamp]
|Voltage   I(typ)   I(min)   I(max)
-1.1V     5.691mA    8.967mA    3.44mA
-1.062V   3.709mA    6.444mA    2.092mA
-1.039V   2.781mA    5.152mA    1.546mA
-1.016V   2.086mA    4.085mA    1.193mA
-970mV    1.21mA     2.539mA    818.5uA
-947mV    943.7uA    2.005mA    716.7uA
-901mV    610.1uA    1.27mA     581.3uA
-855mV    430.7uA    824.1uA    484.6uA
-786mV    289.9uA    439.4uA    366uA
-671mV    155.9uA    155.9uA    203.6uA
-441mV    13.2uA     12.79uA    15.03uA
1.1V      0A         0A         0A
[Ramp]
| variable   typ   min   max
dV/dt_r   0.225/27.758p   0.216/36.206p   0.240/22.738p
dV/dt_f   0.311/42.858p   0.294/56.580p   0.321/34.656p
R_load = 50.000
[Rising Waveform]
R_fixture= 50.000
V_fixture= 1.100
V_fixture_min= 1.060
V_fixture_max= 1.170
|time   V(typ)   V(min)   V(max)
0s        581.6mV    569.9mV    635mV
144ps     582.5mV    570.4mV    633.4mV
203ps     584.3mV    569.8mV    955.7mV
267ps     915.3mV    556.9mV    1.11V
286ps     970.6mV    610.8mV    1.124V
331ps     1.047V     849.6mV    1.148V
376ps     1.077V     966.7mV    1.161V
472ps     1.094V     1.046V     1.169V
658ps     1.1V       1.058V     1.17V
3ns       1.1V       1.06V      1.17V
[Rising Waveform]
R_fixture= 50.000
V_fixture= 0.0
V_fixture_min= 0.0
V_fixture_max= 0.0
|time   V(typ)   V(min)   V(max)
0s        2.898uV    10.6uV     685nV
151ps     -60.59uV   48.04uV    9.646mV
200ps     1.978mV    -23.44uV   406.5mV
222ps     34.47mV    52.58uV    458.6mV
263ps     337.1mV    806.1uV    485.3mV
299ps     411.7mV    28.78mV    417.8mV
367ps     433.5mV    353.9mV    400.8mV
483ps     374.4mV    401.9mV    400.4mV
565ps     374.4mV    358.3mV    400.4mV
3ns       374.4mV    360.1mV    400.4mV
[Falling Waveform]
R_fixture= 50.000
V_fixture= 1.100
V_fixture_min= 1.060
V_fixture_max= 1.170
|time   V(typ)   V(min)   V(max)
0s        1.1V       1.06V      1.17V
158ps     1.1V       1.06V      1.164V
224ps     1.09V      1.06V      649.5mV
272ps     759.8mV    1.058V     522.9mV
314ps     570mV      1.041V     588.1mV
354ps     508mV      853.5mV    617mV
417ps     547.4mV    589.6mV    630.7mV
498ps     576.6mV    503.9mV    634.3mV
692ps     581.5mV    568.6mV    635mV
3ns       581.6mV    569.9mV    635mV
[Falling Waveform]
R_fixture= 50.000
V_fixture= 0.0
V_fixture_min= 0.0
V_fixture_max= 0.0
|time   V(typ)   V(min)   V(max)
0s        374.4mV    360.1mV    400.4mV
145ps     373.8mV    359.4mV    410mV
182ps     390.4mV    358.8mV    141.4mV
197ps     389.9mV    360.3mV    72.57mV
216ps     321.7mV    366.5mV    31.85mV
253ps     89.81mV    384.2mV    6.992mV
291ps     20.9mV     274mV      -3.476mV
348ps     3.076mV    55.77mV    -486.2uV
434ps     -1.192mV   4.031mV    -15.36uV
3ns       1.179uV    10.45uV    359.7nV
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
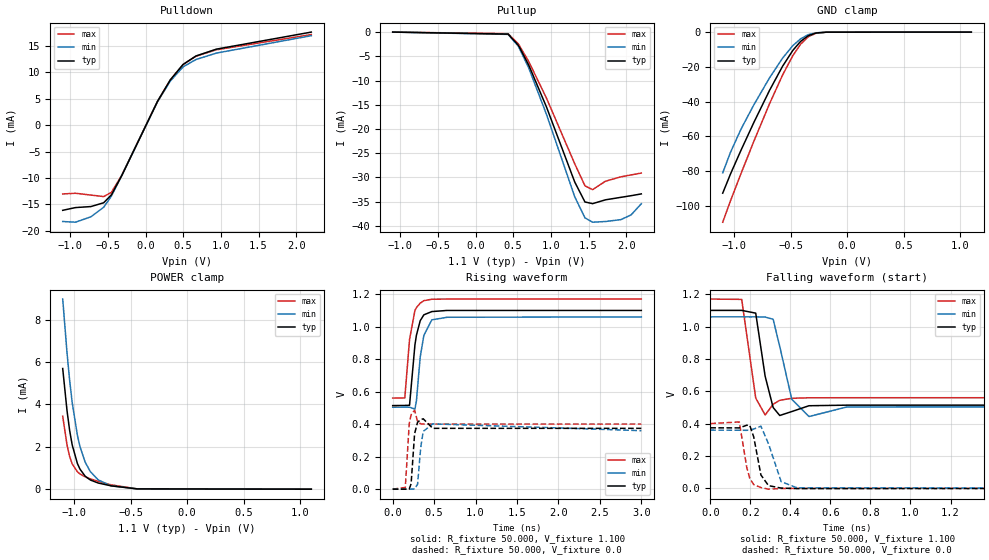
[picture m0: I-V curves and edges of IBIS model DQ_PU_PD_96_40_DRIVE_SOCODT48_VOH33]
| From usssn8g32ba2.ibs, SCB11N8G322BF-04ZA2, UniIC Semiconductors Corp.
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|   Model DQ_PU_PD_96_40_DRIVE_SOCODT48_VOH33
[Model] DQ_PU_PD_96_40_DRIVE_SOCODT48_VOH33
Model_type I/O
Polarity   Inverting
Vinl =  98.000mV
Vinh =  0.268V
Vmeas =  0.183V
Rref =  50.000
Vref =  0.183V
C_comp   1.020pF   1.010pF   1.030pF
[Model Spec]
Vinh   0.268V   0.262V   0.280V
Vinl   98.000mV   92.000mV   0.110V
Vmeas   0.183V   0.177V   0.195V
Vref   0.183V   0.177V   0.195V
Rref   50.000   NA   NA
[Temperature Range]   25.000   0.105k   -40.000
[Voltage Range]   1.100V   1.060V   1.170V
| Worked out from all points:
|   slope of the pulldown table from 0 to 0.165 V, typ, clamps not added: 35.3 ohm
|   GND clamp passes 1 mA (typ) near -0.30 V on its own axis
|   POWER clamp passes 1 mA (typ) near -0.95 V on its own axis
|   rising waveform, R_fixture 50.000, V_fixture 1.100: 20-80 % time 75.4ps typ, 78.2ps min, 73ps max; typ from 0.514 V to 1.1 V
|   rising waveform, R_fixture 50.000, V_fixture 0.0: 20-80 % time 27.5ps typ, 35.9ps min, 22.5ps max; typ from 0 V to 0.374 V
|   falling waveform, R_fixture 50.000, V_fixture 1.100: 20-80 % time 41ps typ, 54.2ps min, 33.5ps max; typ from 1.1 V to 0.514 V
|   falling waveform, R_fixture 50.000, V_fixture 0.0: 20-80 % time 35.1ps typ, 52.2ps min, 30.1ps max; typ from 0.374 V to 0 V
[Pulldown]
|Voltage   I(typ)   I(min)   I(max)
-1.1V     -16.13mA   -18.25mA   -13.03mA
-930mV    -15.61mA   -18.38mA   -12.9mA
-726mV    -15.42mA   -17.36mA   -13.24mA
-556mV    -14.7mA    -15.55mA   -13.53mA
-454mV    -13.2mA    -13.45mA   -12.73mA
-318mV    -9.609mA   -9.606mA   -9.529mA
158mV     4.492mA    4.415mA    4.512mA
328mV     8.568mA    8.352mA    8.576mA
498mV     11.5mA     11.04mA    11.48mA
668mV     13.1mA     12.43mA    13.05mA
940mV     14.4mA     13.65mA    14.28mA
2.2V      17.63mA    16.95mA    17.16mA
[Pullup]
|Voltage   I(typ)   I(min)   I(max)
-1.1V     2.6nA      27.46nA    0A
432mV     -421.9uA   -476.8uA   -329.3uA
568mV     -2.729mA   -2.923mA   -2.437mA
704mV     -6.762mA   -7.352mA   -6.026mA
942mV     -15.5mA    -17.03mA   -13.67mA
1.316V    -30.95mA   -34mA      -27.19mA
1.452V    -35.08mA   -38.36mA   -31.74mA
1.554V    -35.42mA   -39.25mA   -32.53mA
1.724V    -34.63mA   -39.11mA   -30.79mA
1.928V    -34.12mA   -38.72mA   -29.88mA
2.064V    -33.78mA   -37.75mA   -29.49mA
2.2V      -33.41mA   -35.44mA   -29.11mA
[GND_clamp]
|Voltage   I(typ)   I(min)   I(max)
-1.1V     -92.78mA   -81.05mA   -109.5mA
-1.031V   -81.73mA   -69.22mA   -97.17mA
-939mV    -68.18mA   -56.02mA   -81.64mA
-824mV    -52mA      -41.83mA   -62.83mA
-686mV    -33.62mA   -26.41mA   -41.32mA
-571mV    -19.76mA   -15.06mA   -24.85mA
-479mV    -10.5mA    -7.76mA    -13.5mA
-410mV    -5.313mA   -3.84mA    -6.916mA
-341mV    -2.007mA   -1.45mA    -2.59mA
-272mV    -506.9uA   -403.5uA   -609.8uA
-180mV    -45.65uA   -51.35uA   -43.55uA
1.1V      0A         0A         0A
[POWER_clamp]
|Voltage   I(typ)   I(min)   I(max)
-1.1V     5.691mA    8.967mA    3.44mA
-1.062V   3.709mA    6.444mA    2.092mA
-1.039V   2.781mA    5.152mA    1.546mA
-1.016V   2.086mA    4.085mA    1.193mA
-970mV    1.21mA     2.539mA    818.5uA
-947mV    943.7uA    2.005mA    716.7uA
-901mV    610.1uA    1.27mA     581.3uA
-855mV    430.7uA    824.1uA    484.6uA
-786mV    289.9uA    439.4uA    366uA
-671mV    155.9uA    155.9uA    203.6uA
-441mV    13.2uA     12.79uA    15.03uA
1.1V      0A         0A         0A
[Ramp]
| variable   typ   min   max
dV/dt_r   0.225/27.685p   0.216/35.968p   0.240/22.766p
dV/dt_f   0.351/41.131p   0.333/54.297p   0.366/33.592p
R_load = 50.000
[Rising Waveform]
R_fixture= 50.000
V_fixture= 1.100
V_fixture_min= 1.060
V_fixture_max= 1.170
|time   V(typ)   V(min)   V(max)
0s        514.4mV    504.3mV    560.3mV
146ps     515.3mV    504.9mV    561.8mV
203ps     516.3mV    504.3mV    920.5mV
268ps     887.3mV    492.9mV    1.1V
286ps     947mV      542.4mV    1.117V
332ps     1.037V     813.9mV    1.145V
376ps     1.073V     947mV      1.16V
472ps     1.093V     1.042V     1.169V
658ps     1.1V       1.058V     1.17V
3ns       1.1V       1.06V      1.17V
[Rising Waveform]
R_fixture= 50.000
V_fixture= 0.0
V_fixture_min= 0.0
V_fixture_max= 0.0
|time   V(typ)   V(min)   V(max)
0s        2.608uV    9.548uV    616.3nV
152ps     8.381uV    48.95uV    10.6mV
200ps     1.689mV    24.22uV    406.1mV
222ps     32.81mV    167.6uV    458.3mV
264ps     340.6mV    887.7uV    485.4mV
300ps     412.3mV    30.35mV    417mV
338ps     427.2mV    256.1mV    402.1mV
368ps     433.2mV    355.3mV    400.8mV
483ps     374.4mV    401.9mV    400.4mV
3ns       374.4mV    360.1mV    400.4mV
[Falling Waveform]
R_fixture= 50.000
V_fixture= 1.100
V_fixture_min= 1.060
V_fixture_max= 1.170
|time   V(typ)   V(min)   V(max)
0s        1.1V       1.06V      1.17V
157ps     1.1V       1.06V      1.168V
227ps     1.083V     1.06V      558.2mV
274ps     693.4mV    1.059V     453.9mV
314ps     499.9mV    1.045V     520mV
347ps     450.5mV    877.2mV    544.3mV
407ps     474.8mV    551mV      556.9mV
493ps     510.8mV    444mV      559.9mV
683ps     514.4mV    503.4mV    560.3mV
3ns       514.4mV    504.3mV    560.3mV
[Falling Waveform]
R_fixture= 50.000
V_fixture= 0.0
V_fixture_min= 0.0
V_fixture_max= 0.0
|time   V(typ)   V(min)   V(max)
0s        374.4mV    360.1mV    400.4mV
145ps     373.8mV    359.4mV    410.6mV
182ps     390.3mV    358.9mV    131.7mV
197ps     390.1mV    360.3mV    62.2mV
217ps     318.3mV    366.9mV    24.04mV
253ps     82.92mV    384.1mV    4.922mV
291ps     16.95mV    275.2mV    -4.775mV
354ps     1.858mV    41.78mV    -410.9uV
434ps     -1.369mV   3.302mV    -12.05uV
3ns       2.473uV    9.526uV    -1.526uV
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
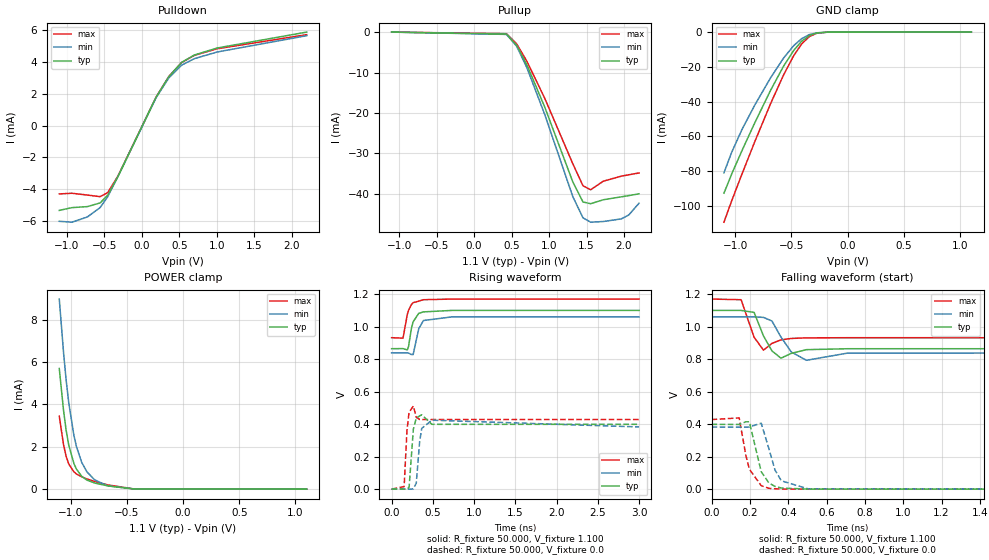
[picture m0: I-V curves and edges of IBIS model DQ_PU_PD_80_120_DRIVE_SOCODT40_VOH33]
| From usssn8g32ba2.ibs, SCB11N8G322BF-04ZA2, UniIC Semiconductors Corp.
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|   Model DQ_PU_PD_80_120_DRIVE_SOCODT40_VOH33
[Model] DQ_PU_PD_80_120_DRIVE_SOCODT40_VOH33
Model_type I/O
Polarity   Inverting
Vinl =  98.000mV
Vinh =  0.268V
Vmeas =  0.183V
Rref =  50.000
Vref =  0.183V
C_comp   1.020pF   1.010pF   1.030pF
[Model Spec]
Vinh   0.268V   0.262V   0.280V
Vinl   98.000mV   92.000mV   0.110V
Vmeas   0.183V   0.177V   0.195V
Vref   0.183V   0.177V   0.195V
Rref   50.000   NA   NA
[Temperature Range]   25.000   0.105k   -40.000
[Voltage Range]   1.100V   1.060V   1.170V
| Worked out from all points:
|   slope of the pulldown table from 0 to 0.165 V, typ, clamps not added: 105 ohm
|   GND clamp passes 1 mA (typ) near -0.30 V on its own axis
|   POWER clamp passes 1 mA (typ) near -0.95 V on its own axis
|   rising waveform, R_fixture 50.000, V_fixture 1.100: 20-80 % time 63.9ps typ, 61.9ps min, 64.7ps max; typ from 0.864 V to 1.1 V
|   rising waveform, R_fixture 50.000, V_fixture 0.0: 20-80 % time 26.9ps typ, 35.8ps min, 21.9ps max; typ from 0 V to 0.399 V
|   falling waveform, R_fixture 50.000, V_fixture 1.100: 20-80 % time 46.1ps typ, 62.1ps min, 35.9ps max; typ from 1.1 V to 0.864 V
|   falling waveform, R_fixture 50.000, V_fixture 0.0: 20-80 % time 51.5ps typ, 60.4ps min, 48.7ps max; typ from 0.399 V to 0 V
[Pulldown]
|Voltage   I(typ)   I(min)   I(max)
-1.1V     -5.34mA    -6.026mA   -4.302mA
-930mV    -5.164mA   -6.082mA   -4.26mA
-726mV    -5.101mA   -5.754mA   -4.373mA
-556mV    -4.87mA    -5.165mA   -4.475mA
-454mV    -4.386mA   -4.479mA   -4.222mA
-318mV    -3.209mA   -3.211mA   -3.18mA
192mV     1.799mA    1.766mA    1.806mA
362mV     3.096mA    3.011mA    3.096mA
532mV     3.983mA    3.811mA    3.973mA
702mV     4.448mA    4.219mA    4.427mA
1.008V    4.891mA    4.64mA     4.842mA
2.2V      5.891mA    5.665mA    5.73mA
[Pullup]
|Voltage   I(typ)   I(min)   I(max)
-1.1V     3.1nA      32.98nA    0A
432mV     -506.1uA   -571.8uA   -395uA
568mV     -3.269mA   -3.501mA   -2.92mA
704mV     -8.095mA   -8.8mA     -7.217mA
942mV     -18.54mA   -20.37mA   -16.36mA
1.316V    -37.03mA   -40.67mA   -32.54mA
1.452V    -42.01mA   -45.93mA   -38mA
1.554V    -42.45mA   -47.02mA   -39mA
1.724V    -41.47mA   -46.85mA   -36.88mA
1.962V    -40.75mA   -46.21mA   -35.64mA
2.064V    -40.44mA   -45.22mA   -35.29mA
2.2V      -40mA      -42.32mA   -34.84mA
[GND_clamp]
|Voltage   I(typ)   I(min)   I(max)
-1.1V     -92.78mA   -81.05mA   -109.5mA
-1.031V   -81.73mA   -69.22mA   -97.17mA
-939mV    -68.18mA   -56.02mA   -81.64mA
-824mV    -52mA      -41.83mA   -62.83mA
-686mV    -33.62mA   -26.41mA   -41.32mA
-571mV    -19.76mA   -15.06mA   -24.85mA
-479mV    -10.5mA    -7.76mA    -13.5mA
-410mV    -5.313mA   -3.84mA    -6.916mA
-341mV    -2.007mA   -1.45mA    -2.59mA
-272mV    -506.9uA   -403.5uA   -609.8uA
-180mV    -45.65uA   -51.35uA   -43.55uA
1.1V      0A         0A         0A
[POWER_clamp]
|Voltage   I(typ)   I(min)   I(max)
-1.1V     5.691mA    8.967mA    3.44mA
-1.062V   3.709mA    6.444mA    2.092mA
-1.039V   2.781mA    5.152mA    1.546mA
-1.016V   2.086mA    4.085mA    1.193mA
-970mV    1.21mA     2.539mA    818.5uA
-947mV    943.7uA    2.005mA    716.7uA
-901mV    610.1uA    1.27mA     581.3uA
-855mV    430.7uA    824.1uA    484.6uA
-786mV    289.9uA    439.4uA    366uA
-671mV    155.9uA    155.9uA    203.6uA
-441mV    13.2uA     12.79uA    15.03uA
1.1V      0A         0A         0A
[Ramp]
| variable   typ   min   max
dV/dt_r   0.239/27.172p   0.230/36.060p   0.257/22.063p
dV/dt_f   0.141/46.256p   0.133/62.076p   0.143/35.919p
R_load = 50.000
[Rising Waveform]
R_fixture= 50.000
V_fixture= 1.100
V_fixture_min= 1.060
V_fixture_max= 1.170
|time   V(typ)   V(min)   V(max)
0s        864.4mV    838.5mV    932.1mV
138ps     865mV      838.7mV    929.4mV
190ps     857.1mV    839.1mV    1.074V
205ps     876.6mV    837.5mV    1.1V
239ps     986.4mV    828.7mV    1.135V
261ps     1.03V      828.4mV    1.148V
329ps     1.082V     987.3mV    1.157V
386ps     1.091V     1.038V     1.166V
727ps     1.1V       1.06V      1.17V
3ns       1.1V       1.06V      1.17V
[Rising Waveform]
R_fixture= 50.000
V_fixture= 0.0
V_fixture_min= 0.0
V_fixture_max= 0.0
|time   V(typ)   V(min)   V(max)
0s        4.356uV    15.89uV    1.031uV
152ps     -322.8uV   82.71uV    15.33mV
186ps     -231.3uV   12.87uV    359.4mV
212ps     11.4mV     -399.7uV   473.8mV
264ps     370.1mV    1.423mV    511.5mV
299ps     436.6mV    36.74mV    441.9mV
340ps     450.8mV    291.7mV    428.7mV
365ps     457.4mV    374mV      428.3mV
489ps     398.9mV    424.2mV    428.3mV
3ns       398.9mV    382.6mV    428.3mV
[Falling Waveform]
R_fixture= 50.000
V_fixture= 1.100
V_fixture_min= 1.060
V_fixture_max= 1.170
|time   V(typ)   V(min)   V(max)
0s        1.1V       1.06V      1.17V
154ps     1.1V       1.06V      1.166V
222ps     1.088V     1.061V     934.7mV
271ps     942.7mV    1.057V     855.6mV
315ps     851mV      1.035V     897.3mV
362ps     806.1mV    936.2mV    918.7mV
416ps     836mV      844.2mV    927.6mV
495ps     858.6mV    793.2mV    931.2mV
710ps     864.3mV    837.5mV    932.1mV
3ns       864.4mV    838.5mV    932.1mV
[Falling Waveform]
R_fixture= 50.000
V_fixture= 0.0
V_fixture_min= 0.0
V_fixture_max= 0.0
|time   V(typ)   V(min)   V(max)
0s        398.9mV    382.6mV    428.3mV
144ps     398.2mV    381.9mV    438.7mV
179ps     414.6mV    381.2mV    207.6mV
197ps     414.8mV    382.8mV    123.6mV
259ps     107.7mV    406.2mV    21.79mV
299ps     38.22mV    249.2mV    5.391mV
331ps     17.16mV    117.7mV    2.41mV
364ps     7.174mV    51.52mV    1.042mV
506ps     126.5uV    1.473mV    27.57uV
3ns       4.331uV    15.92uV    1.118uV
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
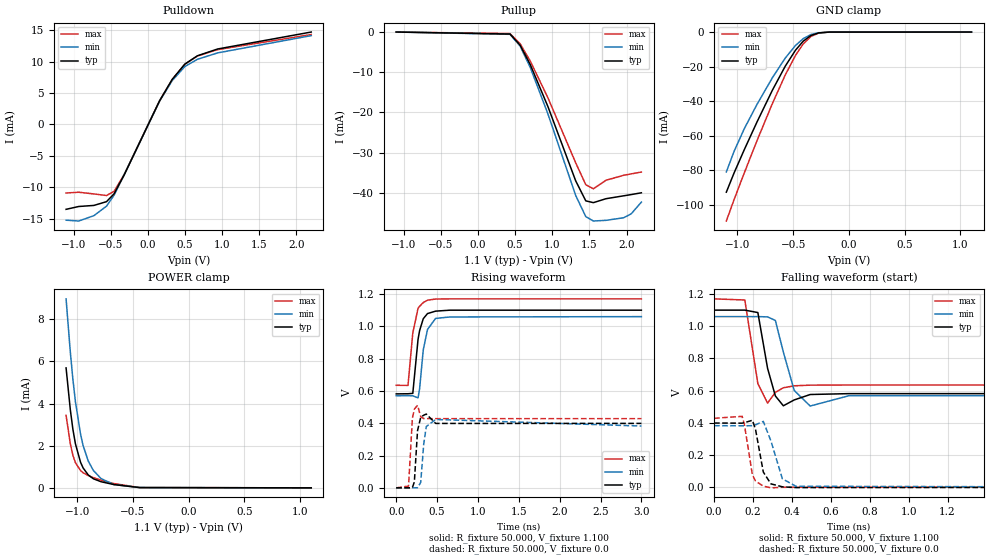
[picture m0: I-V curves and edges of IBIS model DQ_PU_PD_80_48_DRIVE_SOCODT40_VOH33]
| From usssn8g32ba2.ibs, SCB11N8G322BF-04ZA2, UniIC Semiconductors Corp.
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|   Model DQ_PU_PD_80_48_DRIVE_SOCODT40_VOH33
[Model] DQ_PU_PD_80_48_DRIVE_SOCODT40_VOH33
Model_type I/O
Polarity   Inverting
Vinl =  98.000mV
Vinh =  0.268V
Vmeas =  0.183V
Rref =  50.000
Vref =  0.183V
C_comp   1.020pF   1.010pF   1.030pF
[Model Spec]
Vinh   0.268V   0.262V   0.280V
Vinl   98.000mV   92.000mV   0.110V
Vmeas   0.183V   0.177V   0.195V
Vref   0.183V   0.177V   0.195V
Rref   50.000   NA   NA
[Temperature Range]   25.000   0.105k   -40.000
[Voltage Range]   1.100V   1.060V   1.170V
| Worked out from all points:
|   slope of the pulldown table from 0 to 0.165 V, typ, clamps not added: 42.3 ohm
|   GND clamp passes 1 mA (typ) near -0.30 V on its own axis
|   POWER clamp passes 1 mA (typ) near -0.95 V on its own axis
|   rising waveform, R_fixture 50.000, V_fixture 1.100: 20-80 % time 73.7ps typ, 75.6ps min, 71.8ps max; typ from 0.582 V to 1.1 V
|   rising waveform, R_fixture 50.000, V_fixture 0.0: 20-80 % time 26.6ps typ, 35.2ps min, 21.7ps max; typ from 0 V to 0.399 V
|   falling waveform, R_fixture 50.000, V_fixture 1.100: 20-80 % time 43.1ps typ, 56.9ps min, 34.6ps max; typ from 1.1 V to 0.582 V
|   falling waveform, R_fixture 50.000, V_fixture 0.0: 20-80 % time 37.4ps typ, 52.6ps min, 33.2ps max; typ from 0.399 V to 0 V
[Pulldown]
|Voltage   I(typ)   I(min)   I(max)
-1.1V     -13.51mA   -15.24mA   -10.91mA
-930mV    -13.06mA   -15.37mA   -10.79mA
-726mV    -12.89mA   -14.52mA   -11.06mA
-556mV    -12.29mA   -13.01mA   -11.31mA
-454mV    -11.04mA   -11.25mA   -10.65mA
-318mV    -8.03mA    -8.027mA   -7.964mA
158mV     3.751mA    3.687mA    3.768mA
328mV     7.153mA    6.973mA    7.158mA
498mV     9.598mA    9.214mA    9.581mA
668mV     10.93mA    10.37mA    10.89mA
940mV     12.01mA    11.39mA    11.91mA
2.2V      14.71mA    14.14mA    14.31mA
[Pullup]
|Voltage   I(typ)   I(min)   I(max)
-1.1V     3.1nA      32.98nA    0A
432mV     -506.1uA   -571.8uA   -395uA
568mV     -3.269mA   -3.501mA   -2.92mA
704mV     -8.095mA   -8.8mA     -7.217mA
942mV     -18.54mA   -20.37mA   -16.36mA
1.316V    -37.03mA   -40.67mA   -32.54mA
1.452V    -42.01mA   -45.93mA   -38mA
1.554V    -42.45mA   -47.02mA   -39mA
1.724V    -41.47mA   -46.85mA   -36.88mA
1.962V    -40.75mA   -46.21mA   -35.64mA
2.064V    -40.44mA   -45.22mA   -35.29mA
2.2V      -40mA      -42.32mA   -34.84mA
[GND_clamp]
|Voltage   I(typ)   I(min)   I(max)
-1.1V     -92.78mA   -81.05mA   -109.5mA
-1.031V   -81.73mA   -69.22mA   -97.17mA
-939mV    -68.18mA   -56.02mA   -81.64mA
-824mV    -52mA      -41.83mA   -62.83mA
-686mV    -33.62mA   -26.41mA   -41.32mA
-571mV    -19.76mA   -15.06mA   -24.85mA
-479mV    -10.5mA    -7.76mA    -13.5mA
-410mV    -5.313mA   -3.84mA    -6.916mA
-341mV    -2.007mA   -1.45mA    -2.59mA
-272mV    -506.9uA   -403.5uA   -609.8uA
-180mV    -45.65uA   -51.35uA   -43.55uA
1.1V      0A         0A         0A
[POWER_clamp]
|Voltage   I(typ)   I(min)   I(max)
-1.1V     5.691mA    8.967mA    3.44mA
-1.062V   3.709mA    6.444mA    2.092mA
-1.039V   2.781mA    5.152mA    1.546mA
-1.016V   2.086mA    4.085mA    1.193mA
-970mV    1.21mA     2.539mA    818.5uA
-947mV    943.7uA    2.005mA    716.7uA
-901mV    610.1uA    1.27mA     581.3uA
-855mV    430.7uA    824.1uA    484.6uA
-786mV    289.9uA    439.4uA    366uA
-671mV    155.9uA    155.9uA    203.6uA
-441mV    13.2uA     12.79uA    15.03uA
1.1V      0A         0A         0A
[Ramp]
| variable   typ   min   max
dV/dt_r   0.239/26.790p   0.230/35.391p   0.257/21.900p
dV/dt_f   0.311/43.082p   0.294/56.972p   0.321/34.791p
R_load = 50.000
[Rising Waveform]
R_fixture= 50.000
V_fixture= 1.100
V_fixture_min= 1.060
V_fixture_max= 1.170
|time   V(typ)   V(min)   V(max)
0s        581.6mV    569.9mV    635mV
144ps     582.5mV    570.4mV    634mV
203ps     584.8mV    569.7mV    958.4mV
267ps     918.3mV    557mV      1.111V
286ps     972.8mV    612mV      1.124V
331ps     1.047V     853.9mV    1.147V
383ps     1.079V     980.5mV    1.162V
482ps     1.094V     1.049V     1.169V
658ps     1.1V       1.058V     1.17V
3ns       1.1V       1.06V      1.17V
[Rising Waveform]
R_fixture= 50.000
V_fixture= 0.0
V_fixture_min= 0.0
V_fixture_max= 0.0
|time   V(typ)   V(min)   V(max)
0s        2.898uV    10.6uV     685nV
151ps     -112.2uV   55.78uV    10.82mV
198ps     1.939mV    -49.65uV   430.8mV
222ps     36.23mV    -37.52uV   487.5mV
261ps     354mV      511uV      511mV
300ps     437.2mV    33.73mV    440.6mV
337ps     449.8mV    271.9mV    428.8mV
368ps     456.8mV    379.2mV    428.3mV
483ps     398.8mV    423.3mV    428.3mV
3ns       398.9mV    382.6mV    428.3mV
[Falling Waveform]
R_fixture= 50.000
V_fixture= 1.100
V_fixture_min= 1.060
V_fixture_max= 1.170
|time   V(typ)   V(min)   V(max)
0s        1.1V       1.06V      1.17V
158ps     1.1V       1.06V      1.163V
225ps     1.085V     1.06V      644mV
275ps     738.5mV    1.058V     522.8mV
315ps     567.1mV    1.036V     589.3mV
356ps     506.1mV    839.7mV    617.8mV
412ps     542.5mV    601mV      630.1mV
494ps     576.1mV    504.5mV    634.2mV
693ps     581.5mV    568.6mV    635mV
3ns       581.6mV    569.9mV    635mV
[Falling Waveform]
R_fixture= 50.000
V_fixture= 0.0
V_fixture_min= 0.0
V_fixture_max= 0.0
|time   V(typ)   V(min)   V(max)
0s        398.9mV    382.6mV    428.3mV
144ps     398.1mV    381.9mV    440.6mV
155ps     400.8mV    381.5mV    395.2mV
197ps     416.2mV    382.7mV    76.92mV
213ps     359.4mV    387.9mV    38.48mV
253ps     94.8mV     409mV      7.39mV
292ps     21.21mV    288.3mV    -3.572mV
351ps     2.921mV    52.57mV    -412.7uV
421ps     -2.027mV   5.988mV    -25.26uV
3ns       1.366uV    10.55uV    -1.197uV
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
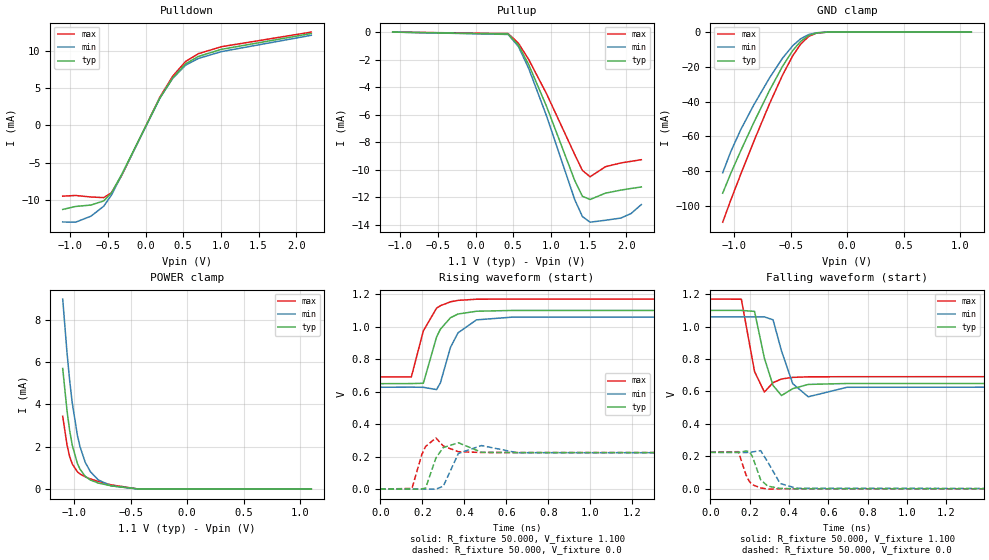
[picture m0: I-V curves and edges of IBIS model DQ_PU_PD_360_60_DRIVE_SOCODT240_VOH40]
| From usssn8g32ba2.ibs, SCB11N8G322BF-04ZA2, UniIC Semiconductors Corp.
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|   Model DQ_PU_PD_360_60_DRIVE_SOCODT240_VOH40
[Model] DQ_PU_PD_360_60_DRIVE_SOCODT240_VOH40
Model_type I/O
Polarity   Inverting
Vinl =  0.135V
Vinh =  0.305V
Vmeas =  0.220V
Rref =  50.000
Vref =  0.220V
C_comp   1.020pF   1.010pF   1.030pF
[Model Spec]
Vinh   0.305V   0.297V   0.319V
Vinl   0.135V   0.127V   0.149V
Vmeas   0.220V   0.212V   0.234V
Vref   0.220V   0.212V   0.234V
Rref   50.000   NA   NA
[Temperature Range]   25.000   0.105k   -40.000
[Voltage Range]   1.100V   1.060V   1.170V
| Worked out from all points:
|   slope of the pulldown table from 0 to 0.165 V, typ, clamps not added: 51.2 ohm
|   GND clamp passes 1 mA (typ) near -0.30 V on its own axis
|   POWER clamp passes 1 mA (typ) near -0.95 V on its own axis
|   rising waveform, R_fixture 50.000, V_fixture 1.100: 20-80 % time 74.1ps typ, 77.7ps min, 72.1ps max; typ from 0.649 V to 1.1 V
|   rising waveform, R_fixture 50.000, V_fixture 0.0: 20-80 % time 32ps typ, 40.5ps min, 25.8ps max; typ from 0 V to 0.225 V
|   falling waveform, R_fixture 50.000, V_fixture 1.100: 20-80 % time 44.5ps typ, 56.6ps min, 36.5ps max; typ from 1.1 V to 0.649 V
|   falling waveform, R_fixture 50.000, V_fixture 0.0: 20-80 % time 41.6ps typ, 58.1ps min, 38.4ps max; typ from 0.225 V to 0 V
[Pulldown]
|Voltage   I(typ)   I(min)   I(max)
-1.1V     -11.28mA   -12.96mA   -9.498mA
-930mV    -10.88mA   -12.99mA   -9.404mA
-726mV    -10.69mA   -12.19mA   -9.609mA
-556mV    -10.14mA   -10.85mA   -9.692mA
-454mV    -9.086mA   -9.369mA   -9.054mA
-318mV    -6.606mA   -6.683mA   -6.751mA
192mV     3.708mA    3.693mA    3.839mA
362mV     6.401mA    6.335mA    6.628mA
532mV     8.266mA    8.084mA    8.585mA
702mV     9.259mA    8.986mA    9.627mA
1.008V    10.21mA    9.901mA    10.56mA
2.2V      12.33mA    12.09mA    12.52mA
[Pullup]
|Voltage   I(typ)   I(min)   I(max)
-1.1V     900pA      9.618nA    0A
432mV     -147.1uA   -170.1uA   -107.3uA
568mV     -948.7uA   -1.043mA   -800.9uA
704mV     -2.351mA   -2.626mA   -1.98mA
942mV     -5.394mA   -6.093mA   -4.481mA
1.316V    -10.78mA   -12.17mA   -8.894mA
1.418V    -11.93mA   -13.4mA    -10.05mA
1.52V     -12.16mA   -13.81mA   -10.51mA
1.724V    -11.7mA    -13.67mA   -9.778mA
1.928V    -11.48mA   -13.51mA   -9.507mA
2.064V    -11.36mA   -13.18mA   -9.389mA
2.2V      -11.25mA   -12.53mA   -9.27mA
[GND_clamp]
|Voltage   I(typ)   I(min)   I(max)
-1.1V     -92.78mA   -81.05mA   -109.5mA
-1.031V   -81.73mA   -69.22mA   -97.17mA
-939mV    -68.18mA   -56.02mA   -81.64mA
-824mV    -52mA      -41.83mA   -62.83mA
-686mV    -33.62mA   -26.41mA   -41.32mA
-571mV    -19.76mA   -15.06mA   -24.85mA
-479mV    -10.5mA    -7.76mA    -13.5mA
-410mV    -5.313mA   -3.84mA    -6.916mA
-341mV    -2.007mA   -1.45mA    -2.59mA
-272mV    -506.9uA   -403.5uA   -609.8uA
-180mV    -45.65uA   -51.35uA   -43.55uA
1.1V      0A         0A         0A
[POWER_clamp]
|Voltage   I(typ)   I(min)   I(max)
-1.1V     5.691mA    8.967mA    3.44mA
-1.062V   3.709mA    6.444mA    2.092mA
-1.039V   2.781mA    5.152mA    1.546mA
-1.016V   2.086mA    4.085mA    1.193mA
-970mV    1.21mA     2.539mA    818.5uA
-947mV    943.7uA    2.005mA    716.7uA
-901mV    610.1uA    1.27mA     581.3uA
-855mV    430.7uA    824.1uA    484.6uA
-786mV    289.9uA    439.4uA    366uA
-671mV    155.9uA    155.9uA    203.6uA
-441mV    13.2uA     12.79uA    15.03uA
1.1V      0A         0A         0A
[Ramp]
| variable   typ   min   max
dV/dt_r   0.135/32.127p   0.134/40.569p   0.135/25.864p
dV/dt_f   0.270/44.667p   0.260/56.699p   0.287/36.585p
R_load = 50.000
[Rising Waveform]
R_fixture= 50.000
V_fixture= 1.100
V_fixture_min= 1.060
V_fixture_max= 1.170
|time   V(typ)   V(min)   V(max)
0s        649.2mV    627.2mV    691mV
148ps     649.9mV    627.7mV    691.2mV
205ps     651.9mV    626.9mV    974.2mV
268ps     936.5mV    612.9mV    1.114V
286ps     984.1mV    653.6mV    1.129V
334ps     1.055V     872.1mV    1.153V
370ps     1.078V     962mV      1.162V
458ps     1.095V     1.042V     1.169V
631ps     1.1V       1.059V     1.17V
3ns       1.1V       1.06V      1.17V
[Rising Waveform]
R_fixture= 50.000
V_fixture= 0.0
V_fixture_min= 0.0
V_fixture_max= 0.0
|time   V(typ)   V(min)   V(max)
0s        3.217uV    11.69uV    749.7nV
151ps     58.15uV    31.16uV    4.849mV
197ps     648.9uV    79.2uV     210.9mV
216ps     7.45mV     224.2uV    263.2mV
265ps     192.3mV    392.5uV    314.9mV
300ps     256.2mV    18.01mV    265.6mV
372ps     285.6mV    220.2mV    230.6mV
482ps     227.1mV    268.3mV    225.7mV
651ps     224.7mV    224.5mV    225.5mV
3ns       224.7mV    224.1mV    225.5mV
[Falling Waveform]
R_fixture= 50.000
V_fixture= 1.100
V_fixture_min= 1.060
V_fixture_max= 1.170
|time   V(typ)   V(min)   V(max)
0s        1.1V       1.06V      1.17V
158ps     1.1V       1.06V      1.169V
225ps     1.094V     1.06V      723mV
275ps     805.5mV    1.06V      596.5mV
319ps     637.2mV    1.042V     654.2mV
362ps     575mV      850mV      677mV
419ps     617.2mV    648.1mV    686.9mV
498ps     643.5mV    567.2mV    690.3mV
695ps     649.1mV    625.8mV    691mV
3ns       649.2mV    627.2mV    691.1mV
[Falling Waveform]
R_fixture= 50.000
V_fixture= 0.0
V_fixture_min= 0.0
V_fixture_max= 0.0
|time   V(typ)   V(min)   V(max)
0s        224.7mV    224.1mV    225.5mV
143ps     224.4mV    223.8mV    228.5mV
182ps     232.3mV    223.4mV    84.29mV
198ps     229.8mV    224.4mV    45.78mV
214ps     199.6mV    227mV      24.72mV
256ps     55.28mV    234.9mV    5.178mV
292ps     16.02mV    165.1mV    -2.722mV
355ps     2.153mV    32.37mV    -327.4uV
438ps     -848.5uV   3.117mV    -16.16uV
3ns       -1.388uV   9.919uV    597.8nV
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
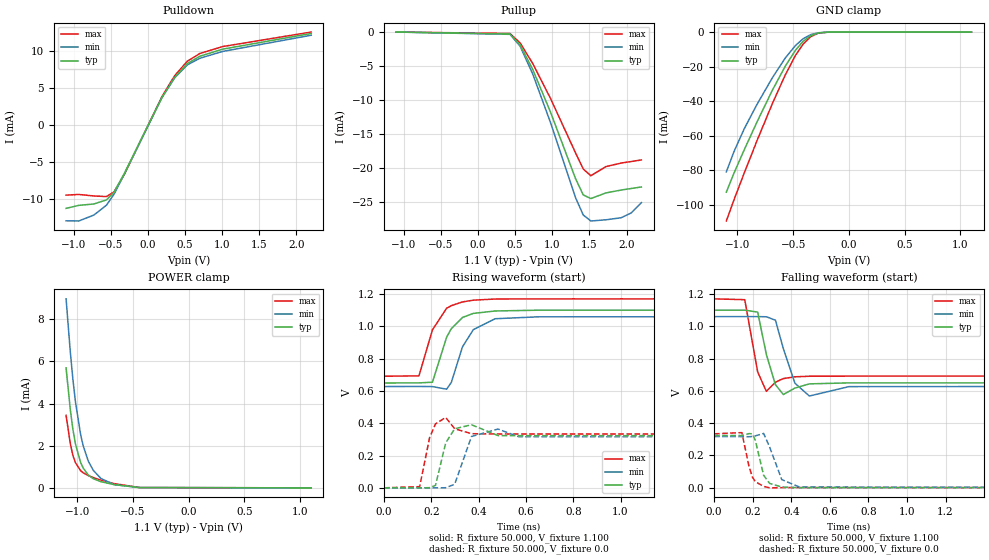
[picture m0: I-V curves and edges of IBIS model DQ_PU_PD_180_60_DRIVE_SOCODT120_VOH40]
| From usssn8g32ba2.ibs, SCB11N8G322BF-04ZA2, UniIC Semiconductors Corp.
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|   Model DQ_PU_PD_180_60_DRIVE_SOCODT120_VOH40
[Model] DQ_PU_PD_180_60_DRIVE_SOCODT120_VOH40
Model_type I/O
Polarity   Inverting
Vinl =  0.135V
Vinh =  0.305V
Vmeas =  0.220V
Rref =  50.000
Vref =  0.220V
C_comp   1.020pF   1.010pF   1.030pF
[Model Spec]
Vinh   0.305V   0.297V   0.319V
Vinl   0.135V   0.127V   0.149V
Vmeas   0.220V   0.212V   0.234V
Vref   0.220V   0.212V   0.234V
Rref   50.000   NA   NA
[Temperature Range]   25.000   0.105k   -40.000
[Voltage Range]   1.100V   1.060V   1.170V
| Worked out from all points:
|   slope of the pulldown table from 0 to 0.165 V, typ, clamps not added: 51.2 ohm
|   GND clamp passes 1 mA (typ) near -0.30 V on its own axis
|   POWER clamp passes 1 mA (typ) near -0.95 V on its own axis
|   rising waveform, R_fixture 50.000, V_fixture 1.100: 20-80 % time 73.2ps typ, 76.2ps min, 71.9ps max; typ from 0.649 V to 1.1 V
|   rising waveform, R_fixture 50.000, V_fixture 0.0: 20-80 % time 28.4ps typ, 35.9ps min, 22.8ps max; typ from 0 V to 0.323 V
|   falling waveform, R_fixture 50.000, V_fixture 1.100: 20-80 % time 44.9ps typ, 57.3ps min, 36.7ps max; typ from 1.1 V to 0.649 V
|   falling waveform, R_fixture 50.000, V_fixture 0.0: 20-80 % time 40.7ps typ, 55.8ps min, 37.6ps max; typ from 0.323 V to 0 V
[Pulldown]
|Voltage   I(typ)   I(min)   I(max)
-1.1V     -11.28mA   -12.96mA   -9.498mA
-930mV    -10.88mA   -12.99mA   -9.404mA
-726mV    -10.69mA   -12.19mA   -9.609mA
-556mV    -10.14mA   -10.85mA   -9.692mA
-454mV    -9.086mA   -9.369mA   -9.054mA
-318mV    -6.606mA   -6.683mA   -6.751mA
192mV     3.708mA    3.693mA    3.839mA
362mV     6.401mA    6.335mA    6.628mA
532mV     8.266mA    8.084mA    8.585mA
702mV     9.259mA    8.986mA    9.627mA
1.008V    10.21mA    9.901mA    10.56mA
2.2V      12.33mA    12.09mA    12.52mA
[Pullup]
|Voltage   I(typ)   I(min)   I(max)
-1.1V     1.8nA      19.34nA    0A
432mV     -294.2uA   -340.2uA   -214.5uA
568mV     -1.899mA   -2.087mA   -1.603mA
738mV     -5.508mA   -6.173mA   -4.628mA
976mV     -11.74mA   -13.27mA   -9.734mA
1.316V    -21.59mA   -24.38mA   -17.8mA
1.418V    -23.93mA   -26.88mA   -20.13mA
1.52V     -24.46mA   -27.76mA   -21.11mA
1.724V    -23.63mA   -27.58mA   -19.76mA
1.928V    -23.21mA   -27.28mA   -19.25mA
2.064V    -22.98mA   -26.57mA   -19.02mA
2.2V      -22.76mA   -25.06mA   -18.79mA
[GND_clamp]
|Voltage   I(typ)   I(min)   I(max)
-1.1V     -92.78mA   -81.05mA   -109.5mA
-1.031V   -81.73mA   -69.22mA   -97.17mA
-939mV    -68.18mA   -56.02mA   -81.64mA
-824mV    -52mA      -41.83mA   -62.83mA
-686mV    -33.62mA   -26.41mA   -41.32mA
-571mV    -19.76mA   -15.06mA   -24.85mA
-479mV    -10.5mA    -7.76mA    -13.5mA
-410mV    -5.313mA   -3.84mA    -6.916mA
-341mV    -2.007mA   -1.45mA    -2.59mA
-272mV    -506.9uA   -403.5uA   -609.8uA
-180mV    -45.65uA   -51.35uA   -43.55uA
1.1V      0A         0A         0A
[POWER_clamp]
|Voltage   I(typ)   I(min)   I(max)
-1.1V     5.691mA    8.967mA    3.44mA
-1.062V   3.709mA    6.444mA    2.092mA
-1.039V   2.781mA    5.152mA    1.546mA
-1.016V   2.086mA    4.085mA    1.193mA
-970mV    1.21mA     2.539mA    818.5uA
-947mV    943.7uA    2.005mA    716.7uA
-901mV    610.1uA    1.27mA     581.3uA
-855mV    430.7uA    824.1uA    484.6uA
-786mV    289.9uA    439.4uA    366uA
-671mV    155.9uA    155.9uA    203.6uA
-441mV    13.2uA     12.79uA    15.03uA
1.1V      0A         0A         0A
[Ramp]
| variable   typ   min   max
dV/dt_r   0.194/28.459p   0.190/35.919p   0.200/22.979p
dV/dt_f   0.270/44.961p   0.260/57.430p   0.287/36.799p
R_load = 50.000
[Rising Waveform]
R_fixture= 50.000
V_fixture= 1.100
V_fixture_min= 1.060
V_fixture_max= 1.170
|time   V(typ)   V(min)   V(max)
0s        649.2mV    627.2mV    691mV
148ps     649.8mV    627.8mV    693.3mV
205ps     654mV      626.8mV    978.2mV
265ps     932.9mV    610.8mV    1.112V
285ps     986.1mV    653.4mV    1.128V
332ps     1.055V     873.2mV    1.151V
378ps     1.08V      979.7mV    1.162V
470ps     1.095V     1.047V     1.169V
656ps     1.1V       1.059V     1.17V
3ns       1.1V       1.06V      1.17V
[Rising Waveform]
R_fixture= 50.000
V_fixture= 0.0
V_fixture_min= 0.0
V_fixture_max= 0.0
|time   V(typ)   V(min)   V(max)
0s        3.217uV    11.69uV    749.7nV
151ps     -64.77uV   47.44uV    7.434mV
193ps     938.5uV    6.253uV    311.2mV
218ps     15.59mV    47.31uV    396.2mV
261ps     278mV      598uV      435.8mV
299ps     365.7mV    22.22mV    365.8mV
370ps     390.6mV    317.8mV    335.2mV
482ps     323.6mV    364.1mV    333.3mV
570ps     323.1mV    316.2mV    333.3mV
3ns       323.1mV    316.4mV    333.3mV
[Falling Waveform]
R_fixture= 50.000
V_fixture= 1.100
V_fixture_min= 1.060
V_fixture_max= 1.170
|time   V(typ)   V(min)   V(max)
0s        1.1V       1.06V      1.17V
159ps     1.1V       1.06V      1.165V
226ps     1.088V     1.06V      717.2mV
271ps     825.7mV    1.059V     596.6mV
318ps     638.4mV    1.038V     653.3mV
359ps     576.9mV    861.7mV    675.8mV
419ps     616.9mV    647.3mV    686.8mV
494ps     643mV      567.7mV    690.2mV
699ps     649.1mV    625.9mV    691mV
3ns       649.2mV    627.2mV    691.1mV
[Falling Waveform]
R_fixture= 50.000
V_fixture= 0.0
V_fixture_min= 0.0
V_fixture_max= 0.0
|time   V(typ)   V(min)   V(max)
0s        323.1mV    316.4mV    333.3mV
144ps     322.4mV    315.9mV    340.8mV
181ps     334.5mV    315.3mV    131.3mV
199ps     333.5mV    316.7mV    65.01mV
214ps     291.2mV    320.5mV    36.61mV
257ps     75.85mV    335.6mV    7.189mV
288ps     25.88mV    251.4mV    -1.687mV
351ps     3.472mV    49.31mV    -296.5uV
442ps     -669.5uV   3.682mV    -10.15uV
3ns       -438nV     11.5uV     574.7nV
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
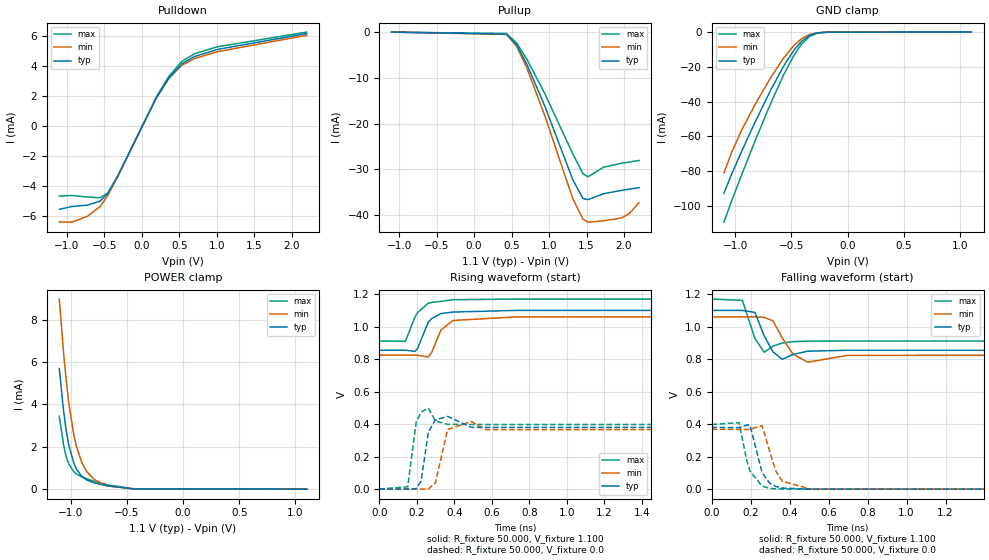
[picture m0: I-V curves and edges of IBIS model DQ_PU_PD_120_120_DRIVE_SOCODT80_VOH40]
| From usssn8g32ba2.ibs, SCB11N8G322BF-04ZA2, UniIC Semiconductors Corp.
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|   Model DQ_PU_PD_120_120_DRIVE_SOCODT80_VOH40
[Model] DQ_PU_PD_120_120_DRIVE_SOCODT80_VOH40
Model_type I/O
Polarity   Inverting
Vinl =  0.135V
Vinh =  0.305V
Vmeas =  0.220V
Rref =  50.000
Vref =  0.220V
C_comp   1.020pF   1.010pF   1.030pF
[Model Spec]
Vinh   0.305V   0.297V   0.319V
Vinl   0.135V   0.127V   0.149V
Vmeas   0.220V   0.212V   0.234V
Vref   0.220V   0.212V   0.234V
Rref   50.000   NA   NA
[Temperature Range]   25.000   0.105k   -40.000
[Voltage Range]   1.100V   1.060V   1.170V
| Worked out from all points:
|   slope of the pulldown table from 0 to 0.165 V, typ, clamps not added: 102 ohm
|   GND clamp passes 1 mA (typ) near -0.30 V on its own axis
|   POWER clamp passes 1 mA (typ) near -0.95 V on its own axis
|   rising waveform, R_fixture 50.000, V_fixture 1.100: 20-80 % time 64.5ps typ, 64.1ps min, 67ps max; typ from 0.855 V to 1.1 V
|   rising waveform, R_fixture 50.000, V_fixture 0.0: 20-80 % time 26.6ps typ, 34.4ps min, 21.1ps max; typ from 0 V to 0.38 V
|   falling waveform, R_fixture 50.000, V_fixture 1.100: 20-80 % time 47.2ps typ, 61.5ps min, 37.7ps max; typ from 1.1 V to 0.855 V
|   falling waveform, R_fixture 50.000, V_fixture 0.0: 20-80 % time 51.2ps typ, 60.2ps min, 49.3ps max; typ from 0.38 V to 0 V
[Pulldown]
|Voltage   I(typ)   I(min)   I(max)
-1.1V     -5.559mA   -6.398mA   -4.673mA
-930mV    -5.368mA   -6.416mA   -4.632mA
-726mV    -5.279mA   -6.025mA   -4.74mA
-556mV    -5.011mA   -5.376mA   -4.784mA
-454mV    -4.503mA   -4.653mA   -4.479mA
-318mV    -3.293mA   -3.335mA   -3.363mA
192mV     1.854mA    1.846mA    1.919mA
362mV     3.2mA      3.168mA    3.314mA
532mV     4.133mA    4.043mA    4.293mA
702mV     4.631mA    4.495mA    4.815mA
1.008V    5.105mA    4.953mA    5.282mA
2.2V      6.168mA    6.05mA     6.263mA
[Pullup]
|Voltage   I(typ)   I(min)   I(max)
-1.1V     2.7nA      29.07nA    0A
432mV     -441uA     -509.9uA   -321.6uA
568mV     -2.841mA   -3.122mA   -2.399mA
704mV     -7.035mA   -7.857mA   -5.928mA
942mV     -16.13mA   -18.22mA   -13.41mA
1.316V    -32.25mA   -36.4mA    -26.61mA
1.452V    -36.39mA   -40.9mA    -30.97mA
1.52V     -36.62mA   -41.55mA   -31.62mA
1.724V    -35.34mA   -41.25mA   -29.55mA
1.962V    -34.61mA   -40.64mA   -28.68mA
2.064V    -34.34mA   -39.74mA   -28.42mA
2.2V      -34.01mA   -37.29mA   -28.06mA
[GND_clamp]
|Voltage   I(typ)   I(min)   I(max)
-1.1V     -92.78mA   -81.05mA   -109.5mA
-1.031V   -81.73mA   -69.22mA   -97.17mA
-939mV    -68.18mA   -56.02mA   -81.64mA
-824mV    -52mA      -41.83mA   -62.83mA
-686mV    -33.62mA   -26.41mA   -41.32mA
-571mV    -19.76mA   -15.06mA   -24.85mA
-479mV    -10.5mA    -7.76mA    -13.5mA
-410mV    -5.313mA   -3.84mA    -6.916mA
-341mV    -2.007mA   -1.45mA    -2.59mA
-272mV    -506.9uA   -403.5uA   -609.8uA
-180mV    -45.65uA   -51.35uA   -43.55uA
1.1V      0A         0A         0A
[POWER_clamp]
|Voltage   I(typ)   I(min)   I(max)
-1.1V     5.691mA    8.967mA    3.44mA
-1.062V   3.709mA    6.444mA    2.092mA
-1.039V   2.781mA    5.152mA    1.546mA
-1.016V   2.086mA    4.085mA    1.193mA
-970mV    1.21mA     2.539mA    818.5uA
-947mV    943.7uA    2.005mA    716.7uA
-901mV    610.1uA    1.27mA     581.3uA
-855mV    430.7uA    824.1uA    484.6uA
-786mV    289.9uA    439.4uA    366uA
-671mV    155.9uA    155.9uA    203.6uA
-441mV    13.2uA     12.79uA    15.03uA
1.1V      0A         0A         0A
[Ramp]
| variable   typ   min   max
dV/dt_r   0.228/26.885p   0.221/34.589p   0.239/21.334p
dV/dt_f   0.147/47.188p   0.141/61.539p   0.155/37.771p
R_load = 50.000
[Rising Waveform]
R_fixture= 50.000
V_fixture= 1.100
V_fixture_min= 1.060
V_fixture_max= 1.170
|time   V(typ)   V(min)   V(max)
0s        855mV      824.7mV    911.8mV
140ps     855.6mV    825mV      910.1mV
190ps     847.4mV    825.4mV    1.058V
205ps     867.6mV    823.7mV    1.087V
261ps     1.026V     813.5mV    1.144V
280ps     1.05V      841.8mV    1.149V
329ps     1.081V     979.1mV    1.156V
393ps     1.09V      1.038V     1.166V
726ps     1.1V       1.06V      1.17V
3ns       1.1V       1.06V      1.17V
[Rising Waveform]
R_fixture= 50.000
V_fixture= 0.0
V_fixture_min= 0.0
V_fixture_max= 0.0
|time   V(typ)   V(min)   V(max)
0s        4.316uV    15.68uV    1.011uV
152ps     -314.2uV   82.51uV    14.43mV
197ps     2.529mV    -158.2uV   411.5mV
223ps     47.95mV    -453.2uV   474mV
262ps     349.5mV    958.3uV    498.7mV
299ps     425.3mV    36.07mV    420.1mV
365ps     447.6mV    367.5mV    398.3mV
491ps     379.9mV    415.8mV    397.7mV
568ps     379.9mV    365.9mV    397.7mV
3ns       379.9mV    368.5mV    397.7mV
[Falling Waveform]
R_fixture= 50.000
V_fixture= 1.100
V_fixture_min= 1.060
V_fixture_max= 1.170
|time   V(typ)   V(min)   V(max)
0s        1.1V       1.06V      1.17V
158ps     1.1V       1.06V      1.162V
222ps     1.088V     1.061V     928.5mV
270ps     943.5mV    1.057V     842.9mV
315ps     845.5mV    1.036V     880.3mV
362ps     799.1mV    931.2mV    899.7mV
418ps     828.9mV    830.9mV    907.9mV
493ps     849.2mV    781.3mV    911mV
698ps     854.9mV    823.6mV    911.8mV
3ns       855mV      824.7mV    911.8mV
[Falling Waveform]
R_fixture= 50.000
V_fixture= 0.0
V_fixture_min= 0.0
V_fixture_max= 0.0
|time   V(typ)   V(min)   V(max)
0s        379.9mV    368.5mV    397.7mV
141ps     378.9mV    367.9mV    409.4mV
180ps     394.6mV    367.2mV    179.3mV
197ps     393.7mV    368.7mV    110.3mV
259ps     101.7mV    390.5mV    19.16mV
299ps     35.83mV    228.7mV    4.485mV
330ps     16.4mV     110.3mV    2.025mV
363ps     6.847mV    48.54mV    867.1uV
506ps     107.4uV    1.267mV    22.29uV
3ns       4.28uV     15.62uV    1.062uV
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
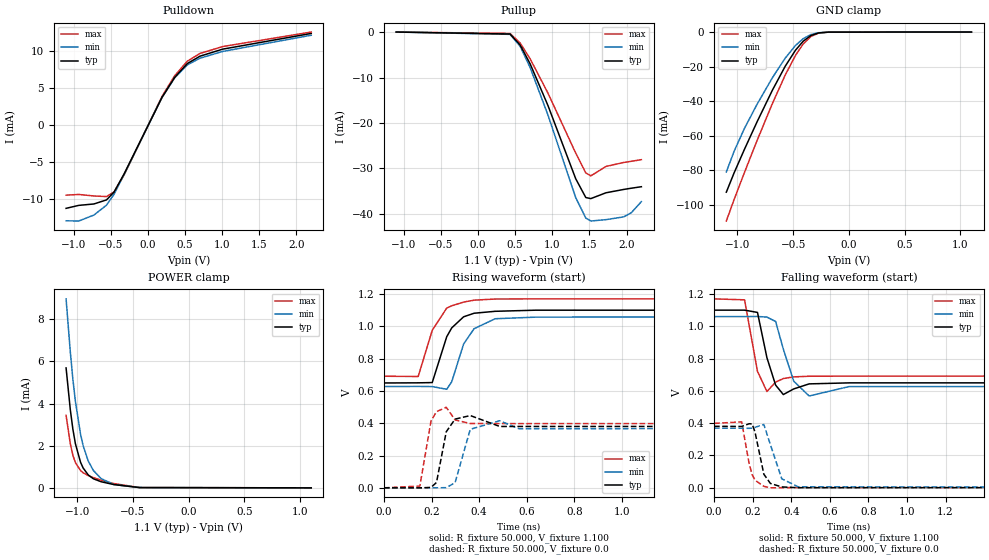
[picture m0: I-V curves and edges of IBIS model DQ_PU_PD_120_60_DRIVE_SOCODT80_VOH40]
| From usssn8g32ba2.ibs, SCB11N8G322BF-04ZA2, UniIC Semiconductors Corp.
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|   Model DQ_PU_PD_120_60_DRIVE_SOCODT80_VOH40
[Model] DQ_PU_PD_120_60_DRIVE_SOCODT80_VOH40
Model_type I/O
Polarity   Inverting
Vinl =  0.135V
Vinh =  0.305V
Vmeas =  0.220V
Rref =  50.000
Vref =  0.220V
C_comp   1.020pF   1.010pF   1.030pF
[Model Spec]
Vinh   0.305V   0.297V   0.319V
Vinl   0.135V   0.127V   0.149V
Vmeas   0.220V   0.212V   0.234V
Vref   0.220V   0.212V   0.234V
Rref   50.000   NA   NA
[Temperature Range]   25.000   0.105k   -40.000
[Voltage Range]   1.100V   1.060V   1.170V
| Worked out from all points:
|   slope of the pulldown table from 0 to 0.165 V, typ, clamps not added: 51.2 ohm
|   GND clamp passes 1 mA (typ) near -0.30 V on its own axis
|   POWER clamp passes 1 mA (typ) near -0.95 V on its own axis
|   rising waveform, R_fixture 50.000, V_fixture 1.100: 20-80 % time 72.2ps typ, 74.3ps min, 71.7ps max; typ from 0.649 V to 1.1 V
|   rising waveform, R_fixture 50.000, V_fixture 0.0: 20-80 % time 26.4ps typ, 34ps min, 21.2ps max; typ from 0 V to 0.38 V
|   falling waveform, R_fixture 50.000, V_fixture 1.100: 20-80 % time 45.1ps typ, 58ps min, 36.9ps max; typ from 1.1 V to 0.649 V
|   falling waveform, R_fixture 50.000, V_fixture 0.0: 20-80 % time 41.1ps typ, 55.6ps min, 38.1ps max; typ from 0.38 V to 0 V
[Pulldown]
|Voltage   I(typ)   I(min)   I(max)
-1.1V     -11.28mA   -12.96mA   -9.498mA
-930mV    -10.88mA   -12.99mA   -9.404mA
-726mV    -10.69mA   -12.19mA   -9.609mA
-556mV    -10.14mA   -10.85mA   -9.692mA
-454mV    -9.086mA   -9.369mA   -9.054mA
-318mV    -6.606mA   -6.683mA   -6.751mA
192mV     3.708mA    3.693mA    3.839mA
362mV     6.401mA    6.335mA    6.628mA
532mV     8.266mA    8.084mA    8.585mA
702mV     9.259mA    8.986mA    9.627mA
1.008V    10.21mA    9.901mA    10.56mA
2.2V      12.33mA    12.09mA    12.52mA
[Pullup]
|Voltage   I(typ)   I(min)   I(max)
-1.1V     2.7nA      29.07nA    0A
432mV     -441uA     -509.9uA   -321.6uA
568mV     -2.841mA   -3.122mA   -2.399mA
704mV     -7.035mA   -7.857mA   -5.928mA
942mV     -16.13mA   -18.22mA   -13.41mA
1.316V    -32.25mA   -36.4mA    -26.61mA
1.452V    -36.39mA   -40.9mA    -30.97mA
1.52V     -36.62mA   -41.55mA   -31.62mA
1.724V    -35.34mA   -41.25mA   -29.55mA
1.962V    -34.61mA   -40.64mA   -28.68mA
2.064V    -34.34mA   -39.74mA   -28.42mA
2.2V      -34.01mA   -37.29mA   -28.06mA
[GND_clamp]
|Voltage   I(typ)   I(min)   I(max)
-1.1V     -92.78mA   -81.05mA   -109.5mA
-1.031V   -81.73mA   -69.22mA   -97.17mA
-939mV    -68.18mA   -56.02mA   -81.64mA
-824mV    -52mA      -41.83mA   -62.83mA
-686mV    -33.62mA   -26.41mA   -41.32mA
-571mV    -19.76mA   -15.06mA   -24.85mA
-479mV    -10.5mA    -7.76mA    -13.5mA
-410mV    -5.313mA   -3.84mA    -6.916mA
-341mV    -2.007mA   -1.45mA    -2.59mA
-272mV    -506.9uA   -403.5uA   -609.8uA
-180mV    -45.65uA   -51.35uA   -43.55uA
1.1V      0A         0A         0A
[POWER_clamp]
|Voltage   I(typ)   I(min)   I(max)
-1.1V     5.691mA    8.967mA    3.44mA
-1.062V   3.709mA    6.444mA    2.092mA
-1.039V   2.781mA    5.152mA    1.546mA
-1.016V   2.086mA    4.085mA    1.193mA
-970mV    1.21mA     2.539mA    818.5uA
-947mV    943.7uA    2.005mA    716.7uA
-901mV    610.1uA    1.27mA     581.3uA
-855mV    430.7uA    824.1uA    484.6uA
-786mV    289.9uA    439.4uA    366uA
-671mV    155.9uA    155.9uA    203.6uA
-441mV    13.2uA     12.79uA    15.03uA
1.1V      0A         0A         0A
[Ramp]
| variable   typ   min   max
dV/dt_r   0.228/26.667p   0.221/34.171p   0.239/21.399p
dV/dt_f   0.270/45.355p   0.260/58.055p   0.287/36.958p
R_load = 50.000
[Rising Waveform]
R_fixture= 50.000
V_fixture= 1.100
V_fixture_min= 1.060
V_fixture_max= 1.170
|time   V(typ)   V(min)   V(max)
0s        649.2mV    627.2mV    691mV
144ps     650.1mV    627.7mV    689.3mV
203ps     651.7mV    627mV      975.2mV
264ps     935.6mV    610.3mV    1.113V
285ps     990.3mV    656.7mV    1.127V
335ps     1.059V     890.4mV    1.15V
379ps     1.081V     985.2mV    1.162V
468ps     1.093V     1.047V     1.169V
641ps     1.1V       1.057V     1.17V
3ns       1.1V       1.06V      1.17V
[Rising Waveform]
R_fixture= 50.000
V_fixture= 0.0
V_fixture_min= 0.0
V_fixture_max= 0.0
|time   V(typ)   V(min)   V(max)
0s        3.217uV    11.69uV    749.7nV
151ps     -192.4uV   64.26uV    11.05mV
198ps     2.61mV     -93.33uV   414.7mV
221ps     33.26mV    -150.6uV   471.6mV
262ps     347.1mV    1.048mV    498.7mV
299ps     425.4mV    31.47mV    420.2mV
363ps     447.5mV    362.4mV    398.3mV
487ps     379.9mV    415.4mV    397.7mV
567ps     379.9mV    365.9mV    397.7mV
3ns       379.9mV    368.5mV    397.7mV
[Falling Waveform]
R_fixture= 50.000
V_fixture= 1.100
V_fixture_min= 1.060
V_fixture_max= 1.170
|time   V(typ)   V(min)   V(max)
0s        1.1V       1.06V      1.17V
158ps     1.1V       1.06V      1.164V
225ps     1.086V     1.061V     720.8mV
274ps     805.1mV    1.057V     595.7mV
319ps     635.4mV    1.03V      654mV
359ps     576.6mV    858.3mV    675.8mV
413ps     611.7mV    659.4mV    686.3mV
493ps     642.9mV    567.8mV    690.2mV
699ps     649.1mV    625.9mV    691mV
3ns       649.2mV    627.2mV    691.1mV
[Falling Waveform]
R_fixture= 50.000
V_fixture= 0.0
V_fixture_min= 0.0
V_fixture_max= 0.0
|time   V(typ)   V(min)   V(max)
0s        379.9mV    368.5mV    397.7mV
143ps     379mV      367.9mV    407.3mV
182ps     395.7mV    367.2mV    146.9mV
197ps     394.6mV    368.6mV    81.75mV
212ps     345.3mV    373.2mV    45.82mV
258ps     82.8mV     391.4mV    7.927mV
292ps     25.47mV    265.9mV    -1.783mV
351ps     3.906mV    54.4mV     -256.8uV
436ps     -823.4uV   4.726mV    -10.79uV
3ns       2.41uV     11.62uV    462.5nV
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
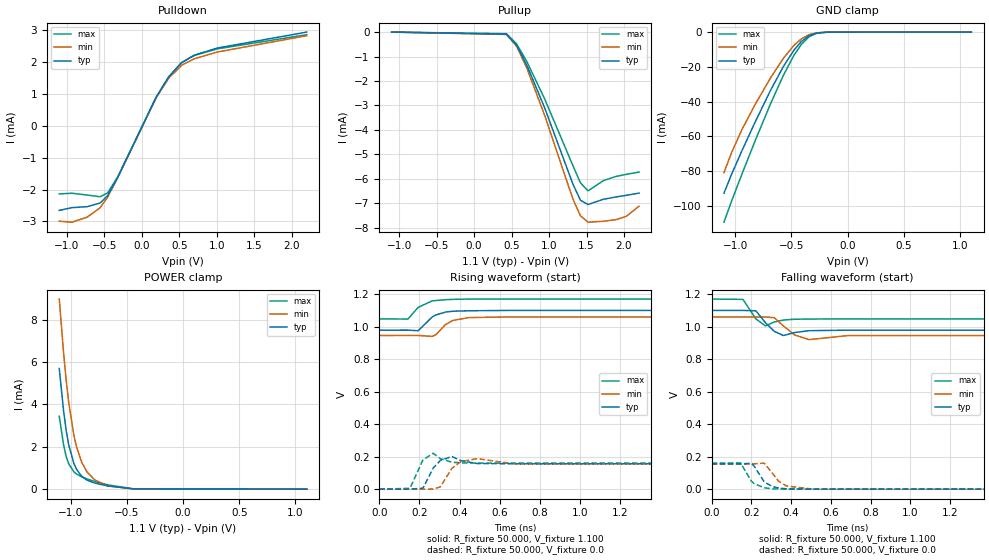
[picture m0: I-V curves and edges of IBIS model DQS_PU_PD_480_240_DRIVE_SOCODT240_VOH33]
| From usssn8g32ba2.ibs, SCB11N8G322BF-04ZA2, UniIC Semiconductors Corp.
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|   Model DQS_PU_PD_480_240_DRIVE_SOCODT240_VOH33
[Model] DQS_PU_PD_480_240_DRIVE_SOCODT240_VOH33
Model_type I/O
Polarity   Inverting
Vinl =  98.000mV
Vinh =  0.268V
Vmeas =  0.183V
Rref =  50.000
Vref =  0.183V
C_comp   1.020pF   1.010pF   1.030pF
[Model Spec]
Vinh   0.268V   0.262V   0.280V
Vinl   98.000mV   92.000mV   0.110V
Vmeas   0.183V   0.177V   0.195V
Vref   0.183V   0.177V   0.195V
Rref   50.000   NA   NA
[Temperature Range]   25.000   0.105k   -40.000
[Voltage Range]   1.100V   1.060V   1.170V
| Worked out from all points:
|   slope of the pulldown table from 0 to 0.165 V, typ, clamps not added: 211 ohm
|   GND clamp passes 1 mA (typ) near -0.30 V on its own axis
|   POWER clamp passes 1 mA (typ) near -0.95 V on its own axis
|   rising waveform, R_fixture 50.000, V_fixture 1.100: 20-80 % time 66.6ps typ, 68.8ps min, 64.9ps max; typ from 0.978 V to 1.1 V
|   rising waveform, R_fixture 50.000, V_fixture 0.0: 20-80 % time 35.1ps typ, 45ps min, 28.3ps max; typ from 0 V to 0.156 V
|   falling waveform, R_fixture 50.000, V_fixture 1.100: 20-80 % time 44.2ps typ, 57.6ps min, 34.5ps max; typ from 1.1 V to 0.978 V
|   falling waveform, R_fixture 50.000, V_fixture 0.0: 20-80 % time 56.7ps typ, 64.6ps min, 53.6ps max; typ from 0.156 V to 0 V
[Pulldown]
|Voltage   I(typ)   I(min)   I(max)
-1.1V     -2.652mA   -2.992mA   -2.134mA
-930mV    -2.565mA   -3.023mA   -2.114mA
-726mV    -2.535mA   -2.862mA   -2.171mA
-556mV    -2.422mA   -2.572mA   -2.223mA
-454mV    -2.185mA   -2.234mA   -2.101mA
-318mV    -1.604mA   -1.606mA   -1.589mA
192mV     900.6uA    884.3uA    903.8uA
362mV     1.549mA    1.507mA    1.549mA
532mV     1.993mA    1.907mA    1.988mA
702mV     2.225mA    2.111mA    2.215mA
1.008V    2.447mA    2.322mA    2.422mA
2.2V      2.948mA    2.835mA    2.866mA
[Pullup]
|Voltage   I(typ)   I(min)   I(max)
-1.1V     500pA      5.412nA    0A
432mV     -84.42uA   -95.4uA    -65.89uA
568mV     -546.4uA   -585.3uA   -487.9uA
704mV     -1.354mA   -1.473mA   -1.207mA
942mV     -3.104mA   -3.412mA   -2.737mA
1.316V    -6.198mA   -6.807mA   -5.446mA
1.418V    -6.872mA   -7.507mA   -6.161mA
1.52V     -7.049mA   -7.771mA   -6.489mA
1.724V    -6.835mA   -7.734mA   -6.072mA
1.894V    -6.739mA   -7.667mA   -5.9mA
2.03V     -6.672mA   -7.532mA   -5.816mA
2.2V      -6.582mA   -7.117mA   -5.721mA
[GND_clamp]
|Voltage   I(typ)   I(min)   I(max)
-1.1V     -92.78mA   -81.05mA   -109.5mA
-1.031V   -81.73mA   -69.22mA   -97.17mA
-939mV    -68.18mA   -56.02mA   -81.64mA
-824mV    -52mA      -41.83mA   -62.83mA
-686mV    -33.62mA   -26.41mA   -41.32mA
-571mV    -19.76mA   -15.06mA   -24.85mA
-479mV    -10.5mA    -7.76mA    -13.5mA
-410mV    -5.313mA   -3.84mA    -6.916mA
-341mV    -2.007mA   -1.45mA    -2.59mA
-272mV    -506.9uA   -403.5uA   -609.8uA
-180mV    -45.65uA   -51.35uA   -43.55uA
1.1V      0A         0A         0A
[POWER_clamp]
|Voltage   I(typ)   I(min)   I(max)
-1.1V     5.691mA    8.967mA    3.44mA
-1.062V   3.709mA    6.444mA    2.092mA
-1.039V   2.781mA    5.152mA    1.546mA
-1.016V   2.086mA    4.085mA    1.193mA
-970mV    1.21mA     2.539mA    818.5uA
-947mV    943.7uA    2.005mA    716.7uA
-901mV    610.1uA    1.27mA     581.3uA
-855mV    430.7uA    824.1uA    484.6uA
-786mV    289.9uA    439.4uA    366uA
-671mV    155.9uA    155.9uA    203.6uA
-441mV    13.2uA     12.79uA    15.03uA
1.1V      0A         0A         0A
[Ramp]
| variable   typ   min   max
dV/dt_r   93.599m/35.273p   92.823m/45.023p   96.210m/28.273p
dV/dt_f   72.904m/44.164p   68.572m/57.680p   73.268m/34.529p
R_load = 50.000
[Rising Waveform]
R_fixture= 50.000
V_fixture= 1.100
V_fixture_min= 1.060
V_fixture_max= 1.170
|time   V(typ)   V(min)   V(max)
0s        978.5mV    945.7mV    1.048V
143ps     978.8mV    945.9mV    1.047V
194ps     975mV      946mV      1.119V
264ps     1.06V      940mV      1.159V
282ps     1.072V     950.5mV    1.161V
330ps     1.09V      1.013V     1.166V
366ps     1.095V     1.038V     1.168V
446ps     1.098V     1.056V     1.17V
646ps     1.1V       1.06V      1.17V
3ns       1.1V       1.06V      1.17V
[Rising Waveform]
R_fixture= 50.000
V_fixture= 0.0
V_fixture_min= 0.0
V_fixture_max= 0.0
|time   V(typ)   V(min)   V(max)
0s        5.234uV    19.06uV    1.239uV
153ps     -29.96uV   44.47uV    5.035mV
218ps     6.214mV    -8.542uV   180.9mV
269ps     129.9mV    454.3uV    220.7mV
305ps     177.3mV    15.04mV    187.2mV
362ps     201mV      128.1mV    165.8mV
407ps     175.6mV    169.8mV    161.9mV
488ps     157.8mV    187.8mV    160.5mV
678ps     156mV      154.9mV    160.3mV
3ns       156mV      154.7mV    160.3mV
[Falling Waveform]
R_fixture= 50.000
V_fixture= 1.100
V_fixture_min= 1.060
V_fixture_max= 1.170
|time   V(typ)   V(min)   V(max)
0s        1.1V       1.06V      1.17V
158ps     1.1V       1.06V      1.168V
223ps     1.098V     1.06V      1.048V
271ps     1.025V     1.06V      1.005V
316ps     971.1mV    1.055V     1.029V
361ps     945.8mV    1.005V     1.041V
420ps     964.2mV    947.8mV    1.046V
491ps     975.5mV    920.5mV    1.047V
685ps     978.5mV    945.1mV    1.048V
3ns       978.5mV    945.7mV    1.048V
[Falling Waveform]
R_fixture= 50.000
V_fixture= 0.0
V_fixture_min= 0.0
V_fixture_max= 0.0
|time   V(typ)   V(min)   V(max)
0s        156mV      154.7mV    160.3mV
146ps     155.9mV    154.5mV    161.5mV
200ps     159.2mV    154.8mV    50.14mV
215ps     141.1mV    156.3mV    33.83mV
265ps     44.41mV    160mV      8.845mV
308ps     15.06mV    95.11mV    1.979mV
337ps     7.311mV    49.91mV    950.3uV
376ps     2.194mV    19.91mV    361.4uV
508ps     24.3uV     418.6uV    14.41uV
3ns       5.122uV    19.05uV    403.9nV
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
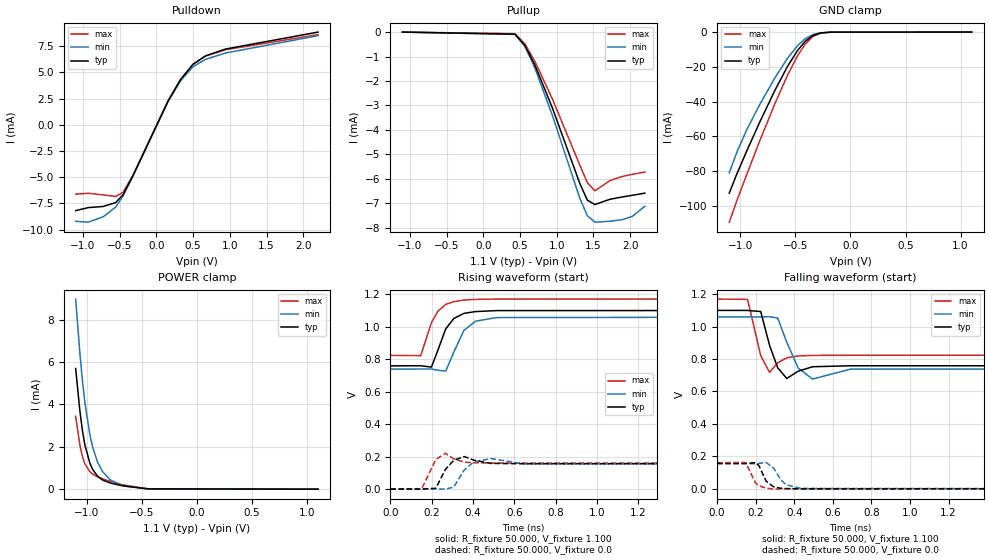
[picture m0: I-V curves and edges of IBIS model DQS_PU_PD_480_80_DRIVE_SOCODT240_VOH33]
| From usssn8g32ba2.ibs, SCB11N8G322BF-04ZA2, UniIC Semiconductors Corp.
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|   Model DQS_PU_PD_480_80_DRIVE_SOCODT240_VOH33
[Model] DQS_PU_PD_480_80_DRIVE_SOCODT240_VOH33
Model_type I/O
Polarity   Inverting
Vinl =  98.000mV
Vinh =  0.268V
Vmeas =  0.183V
Rref =  50.000
Vref =  0.183V
C_comp   1.020pF   1.010pF   1.030pF
[Model Spec]
Vinh   0.268V   0.262V   0.280V
Vinl   98.000mV   92.000mV   0.110V
Vmeas   0.183V   0.177V   0.195V
Vref   0.183V   0.177V   0.195V
Rref   50.000   NA   NA
[Temperature Range]   25.000   0.105k   -40.000
[Voltage Range]   1.100V   1.060V   1.170V
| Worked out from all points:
|   slope of the pulldown table from 0 to 0.165 V, typ, clamps not added: 70.2 ohm
|   GND clamp passes 1 mA (typ) near -0.30 V on its own axis
|   POWER clamp passes 1 mA (typ) near -0.95 V on its own axis
|   rising waveform, R_fixture 50.000, V_fixture 1.100: 20-80 % time 68.2ps typ, 71.4ps min, 65.9ps max; typ from 0.759 V to 1.1 V
|   rising waveform, R_fixture 50.000, V_fixture 0.0: 20-80 % time 34.8ps typ, 44.1ps min, 28.2ps max; typ from 0 V to 0.156 V
|   falling waveform, R_fixture 50.000, V_fixture 1.100: 20-80 % time 43.1ps typ, 56.2ps min, 34.3ps max; typ from 1.1 V to 0.759 V
|   falling waveform, R_fixture 50.000, V_fixture 0.0: 20-80 % time 41.7ps typ, 54.1ps min, 38.4ps max; typ from 0.156 V to 0 V
[Pulldown]
|Voltage   I(typ)   I(min)   I(max)
-1.1V     -8.193mA   -9.206mA   -6.618mA
-930mV    -7.906mA   -9.295mA   -6.537mA
-726mV    -7.797mA   -8.78mA    -6.691mA
-556mV    -7.432mA   -7.863mA   -6.841mA
-454mV    -6.673mA   -6.794mA   -6.44mA
-318mV    -4.841mA   -4.838mA   -4.804mA
158mV     2.257mA    2.219mA    2.267mA
328mV     4.302mA    4.194mA    4.305mA
498mV     5.77mA     5.539mA    5.759mA
668mV     6.567mA    6.233mA    6.54mA
940mV     7.217mA    6.841mA    7.152mA
2.2V      8.836mA    8.496mA    8.595mA
[Pullup]
|Voltage   I(typ)   I(min)   I(max)
-1.1V     500pA      5.412nA    0A
432mV     -84.42uA   -95.4uA    -65.89uA
568mV     -546.4uA   -585.3uA   -487.9uA
704mV     -1.354mA   -1.473mA   -1.207mA
942mV     -3.104mA   -3.412mA   -2.737mA
1.316V    -6.198mA   -6.807mA   -5.446mA
1.418V    -6.872mA   -7.507mA   -6.161mA
1.52V     -7.049mA   -7.771mA   -6.489mA
1.724V    -6.835mA   -7.734mA   -6.072mA
1.894V    -6.739mA   -7.667mA   -5.9mA
2.03V     -6.672mA   -7.532mA   -5.816mA
2.2V      -6.582mA   -7.117mA   -5.721mA
[GND_clamp]
|Voltage   I(typ)   I(min)   I(max)
-1.1V     -92.78mA   -81.05mA   -109.5mA
-1.031V   -81.73mA   -69.22mA   -97.17mA
-939mV    -68.18mA   -56.02mA   -81.64mA
-824mV    -52mA      -41.83mA   -62.83mA
-686mV    -33.62mA   -26.41mA   -41.32mA
-571mV    -19.76mA   -15.06mA   -24.85mA
-479mV    -10.5mA    -7.76mA    -13.5mA
-410mV    -5.313mA   -3.84mA    -6.916mA
-341mV    -2.007mA   -1.45mA    -2.59mA
-272mV    -506.9uA   -403.5uA   -609.8uA
-180mV    -45.65uA   -51.35uA   -43.55uA
1.1V      0A         0A         0A
[POWER_clamp]
|Voltage   I(typ)   I(min)   I(max)
-1.1V     5.691mA    8.967mA    3.44mA
-1.062V   3.709mA    6.444mA    2.092mA
-1.039V   2.781mA    5.152mA    1.546mA
-1.016V   2.086mA    4.085mA    1.193mA
-970mV    1.21mA     2.539mA    818.5uA
-947mV    943.7uA    2.005mA    716.7uA
-901mV    610.1uA    1.27mA     581.3uA
-855mV    430.7uA    824.1uA    484.6uA
-786mV    289.9uA    439.4uA    366uA
-671mV    155.9uA    155.9uA    203.6uA
-441mV    13.2uA     12.79uA    15.03uA
1.1V      0A         0A         0A
[Ramp]
| variable   typ   min   max
dV/dt_r   93.600m/34.776p   92.826m/44.174p   96.210m/28.346p
dV/dt_f   0.205/43.144p   0.193/56.289p   0.208/34.326p
R_load = 50.000
[Rising Waveform]
R_fixture= 50.000
V_fixture= 1.100
V_fixture_min= 1.060
V_fixture_max= 1.170
|time   V(typ)   V(min)   V(max)
0s        758.6mV    738.8mV    823.3mV
147ps     759.3mV    739.2mV    821.4mV
199ps     751.2mV    739.4mV    1.025V
230ps     854.5mV    731.6mV    1.095V
268ps     986.4mV    726.7mV    1.137V
307ps     1.05V      842.7mV    1.154V
356ps     1.082V     977.1mV    1.164V
413ps     1.093V     1.034V     1.168V
514ps     1.099V     1.056V     1.17V
3ns       1.1V       1.06V      1.17V
[Rising Waveform]
R_fixture= 50.000
V_fixture= 0.0
V_fixture_min= 0.0
V_fixture_max= 0.0
|time   V(typ)   V(min)   V(max)
0s        3.731uV    13.63uV    881.9nV
152ps     104.4uV    19.78uV    2.634mV
220ps     4.697mV    266.5uV    182.1mV
267ps     121.9mV    -622.6uV   220.4mV
307ps     177.6mV    12.41mV    185.5mV
358ps     200.2mV    118.2mV    166.4mV
403ps     178.2mV    166.7mV    162mV
487ps     157.9mV    187.8mV    160.5mV
645ps     156mV      155.2mV    160.3mV
3ns       156mV      154.7mV    160.3mV
[Falling Waveform]
R_fixture= 50.000
V_fixture= 1.100
V_fixture_min= 1.060
V_fixture_max= 1.170
|time   V(typ)   V(min)   V(max)
0s        1.1V       1.06V      1.17V
158ps     1.1V       1.06V      1.168V
226ps     1.093V     1.06V      820.7mV
272ps     884.1mV    1.061V     717.9mV
314ps     745.9mV    1.053V     777mV
361ps     680.4mV    903.4mV    807.8mV
420ps     725mV      744.7mV    819.2mV
495ps     752.6mV    676.6mV    822.6mV
691ps     758.5mV    737.6mV    823.3mV
3ns       758.6mV    738.8mV    823.3mV
[Falling Waveform]
R_fixture= 50.000
V_fixture= 0.0
V_fixture_min= 0.0
V_fixture_max= 0.0
|time   V(typ)   V(min)   V(max)
0s        156mV      154.7mV    160.3mV
147ps     155.8mV    154.5mV    162.8mV
200ps     161.2mV    154.7mV    34.08mV
217ps     141.6mV    156.4mV    17.51mV
254ps     47.04mV    162.6mV    4.199mV
293ps     11.6mV     128mV      -2.619mV
329ps     3.198mV    57.95mV    -982uV
356ps     1.156mV    25.04mV    -362.6uV
436ps     -970.6uV   1.922mV    -16.96uV
3ns       3.018uV    13.51uV    523nV
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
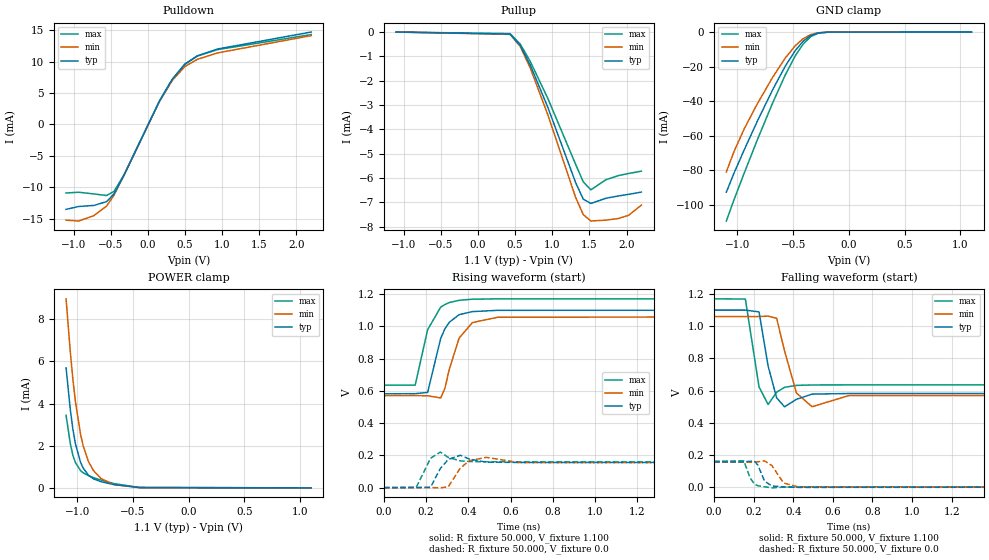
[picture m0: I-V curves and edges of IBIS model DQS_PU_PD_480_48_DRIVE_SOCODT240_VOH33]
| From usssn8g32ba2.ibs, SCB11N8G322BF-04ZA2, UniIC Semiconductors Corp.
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|   Model DQS_PU_PD_480_48_DRIVE_SOCODT240_VOH33
[Model] DQS_PU_PD_480_48_DRIVE_SOCODT240_VOH33
Model_type I/O
Polarity   Inverting
Vinl =  98.000mV
Vinh =  0.268V
Vmeas =  0.183V
Rref =  50.000
Vref =  0.183V
C_comp   1.020pF   1.010pF   1.030pF
[Model Spec]
Vinh   0.268V   0.262V   0.280V
Vinl   98.000mV   92.000mV   0.110V
Vmeas   0.183V   0.177V   0.195V
Vref   0.183V   0.177V   0.195V
Rref   50.000   NA   NA
[Temperature Range]   25.000   0.105k   -40.000
[Voltage Range]   1.100V   1.060V   1.170V
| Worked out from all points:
|   slope of the pulldown table from 0 to 0.165 V, typ, clamps not added: 42.3 ohm
|   GND clamp passes 1 mA (typ) near -0.30 V on its own axis
|   POWER clamp passes 1 mA (typ) near -0.95 V on its own axis
|   rising waveform, R_fixture 50.000, V_fixture 1.100: 20-80 % time 69.1ps typ, 72.7ps min, 66.6ps max; typ from 0.582 V to 1.1 V
|   rising waveform, R_fixture 50.000, V_fixture 0.0: 20-80 % time 34.3ps typ, 43.5ps min, 28.1ps max; typ from 0 V to 0.156 V
|   falling waveform, R_fixture 50.000, V_fixture 1.100: 20-80 % time 41ps typ, 53.8ps min, 33ps max; typ from 1.1 V to 0.582 V
|   falling waveform, R_fixture 50.000, V_fixture 0.0: 20-80 % time 33.6ps typ, 47.7ps min, 30.2ps max; typ from 0.156 V to 0 V
[Pulldown]
|Voltage   I(typ)   I(min)   I(max)
-1.1V     -13.51mA   -15.24mA   -10.91mA
-930mV    -13.06mA   -15.37mA   -10.79mA
-726mV    -12.89mA   -14.52mA   -11.06mA
-556mV    -12.29mA   -13.01mA   -11.31mA
-454mV    -11.04mA   -11.25mA   -10.65mA
-318mV    -8.03mA    -8.027mA   -7.964mA
158mV     3.751mA    3.687mA    3.768mA
328mV     7.153mA    6.973mA    7.158mA
498mV     9.598mA    9.214mA    9.581mA
668mV     10.93mA    10.37mA    10.89mA
940mV     12.01mA    11.39mA    11.91mA
2.2V      14.71mA    14.14mA    14.31mA
[Pullup]
|Voltage   I(typ)   I(min)   I(max)
-1.1V     500pA      5.412nA    0A
432mV     -84.42uA   -95.4uA    -65.89uA
568mV     -546.4uA   -585.3uA   -487.9uA
704mV     -1.354mA   -1.473mA   -1.207mA
942mV     -3.104mA   -3.412mA   -2.737mA
1.316V    -6.198mA   -6.807mA   -5.446mA
1.418V    -6.872mA   -7.507mA   -6.161mA
1.52V     -7.049mA   -7.771mA   -6.489mA
1.724V    -6.835mA   -7.734mA   -6.072mA
1.894V    -6.739mA   -7.667mA   -5.9mA
2.03V     -6.672mA   -7.532mA   -5.816mA
2.2V      -6.582mA   -7.117mA   -5.721mA
[GND_clamp]
|Voltage   I(typ)   I(min)   I(max)
-1.1V     -92.78mA   -81.05mA   -109.5mA
-1.031V   -81.73mA   -69.22mA   -97.17mA
-939mV    -68.18mA   -56.02mA   -81.64mA
-824mV    -52mA      -41.83mA   -62.83mA
-686mV    -33.62mA   -26.41mA   -41.32mA
-571mV    -19.76mA   -15.06mA   -24.85mA
-479mV    -10.5mA    -7.76mA    -13.5mA
-410mV    -5.313mA   -3.84mA    -6.916mA
-341mV    -2.007mA   -1.45mA    -2.59mA
-272mV    -506.9uA   -403.5uA   -609.8uA
-180mV    -45.65uA   -51.35uA   -43.55uA
1.1V      0A         0A         0A
[POWER_clamp]
|Voltage   I(typ)   I(min)   I(max)
-1.1V     5.691mA    8.967mA    3.44mA
-1.062V   3.709mA    6.444mA    2.092mA
-1.039V   2.781mA    5.152mA    1.546mA
-1.016V   2.086mA    4.085mA    1.193mA
-970mV    1.21mA     2.539mA    818.5uA
-947mV    943.7uA    2.005mA    716.7uA
-901mV    610.1uA    1.27mA     581.3uA
-855mV    430.7uA    824.1uA    484.6uA
-786mV    289.9uA    439.4uA    366uA
-671mV    155.9uA    155.9uA    203.6uA
-441mV    13.2uA     12.79uA    15.03uA
1.1V      0A         0A         0A
[Ramp]
| variable   typ   min   max
dV/dt_r   93.601m/34.336p   92.828m/43.416p   96.210m/28.199p
dV/dt_f   0.311/40.984p   0.294/53.761p   0.321/33.130p
R_load = 50.000
[Rising Waveform]
R_fixture= 50.000
V_fixture= 1.100
V_fixture_min= 1.060
V_fixture_max= 1.170
|time   V(typ)   V(min)   V(max)
0s        581.6mV    569.9mV    635mV
148ps     582.4mV    570.5mV    635.1mV
207ps     590mV      569.3mV    978.8mV
269ps     925.4mV    556.2mV    1.119V
289ps     984.9mV    615.5mV    1.135V
309ps     1.024V     730.2mV    1.147V
356ps     1.072V     926.2mV    1.161V
419ps     1.091V     1.023V     1.168V
539ps     1.099V     1.056V     1.17V
3ns       1.1V       1.06V      1.17V
[Rising Waveform]
R_fixture= 50.000
V_fixture= 0.0
V_fixture_min= 0.0
V_fixture_max= 0.0
|time   V(typ)   V(min)   V(max)
0s        2.898uV    10.6uV     684.5nV
153ps     275uV      14.09uV    1.551mV
221ps     2.27mV     502.1uV    182.2mV
267ps     118.5mV    -1.416mV   220.2mV
305ps     174.9mV    5.123mV    187.1mV
362ps     200.6mV    121.2mV    165.7mV
405ps     176.8mV    166.9mV    162mV
485ps     158mV      187.6mV    160.5mV
639ps     156mV      155.3mV    160.3mV
3ns       156mV      154.7mV    160.3mV
[Falling Waveform]
R_fixture= 50.000
V_fixture= 1.100
V_fixture_min= 1.060
V_fixture_max= 1.170
|time   V(typ)   V(min)   V(max)
0s        1.1V       1.06V      1.17V
158ps     1.1V       1.06V      1.169V
227ps     1.089V     1.06V      622.5mV
273ps     751.9mV    1.063V     513.3mV
316ps     554.9mV    1.049V     589.8mV
356ps     498.8mV    846mV      620.1mV
416ps     545.7mV    584.8mV    632mV
495ps     577.7mV    499.4mV    634.6mV
681ps     581.5mV    568.9mV    635mV
3ns       581.6mV    569.9mV    635mV
[Falling Waveform]
R_fixture= 50.000
V_fixture= 0.0
V_fixture_min= 0.0
V_fixture_max= 0.0
|time   V(typ)   V(min)   V(max)
0s        156mV      154.7mV    160.3mV
150ps     155.8mV    154.5mV    163mV
182ps     160.5mV    154.3mV    56.73mV
203ps     161.7mV    154.8mV    19.7mV
221ps     137.2mV    156.7mV    7.812mV
255ps     36.64mV    162.5mV    1.555mV
292ps     6.748mV    133.5mV    -5.047mV
351ps     658.2uV    24.92mV    -453.8uV
422ps     -2.295mV   1.614mV    -11.46uV
3ns       2.633uV    10.53uV    257nV
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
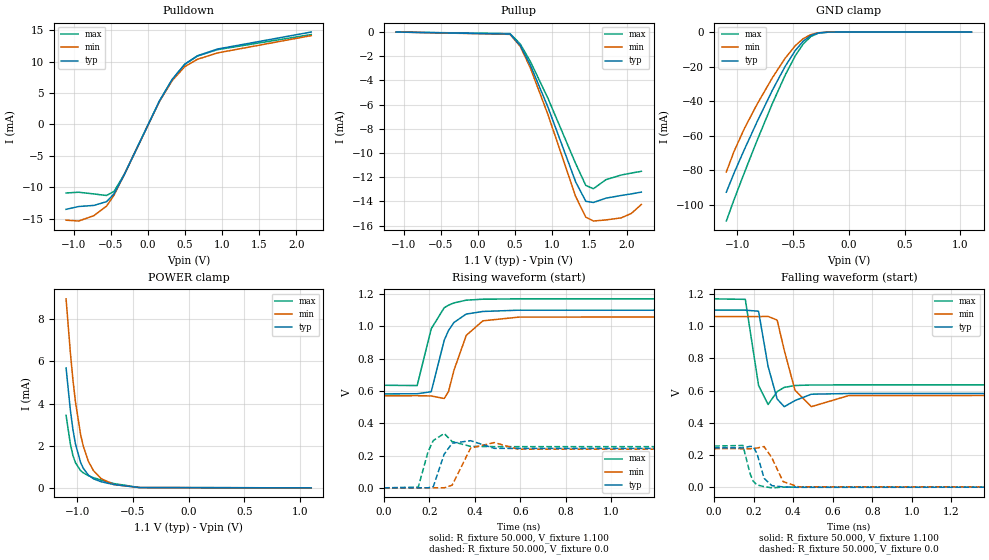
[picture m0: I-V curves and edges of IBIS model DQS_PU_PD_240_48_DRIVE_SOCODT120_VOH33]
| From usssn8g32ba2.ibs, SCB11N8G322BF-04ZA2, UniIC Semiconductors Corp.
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|   Model DQS_PU_PD_240_48_DRIVE_SOCODT120_VOH33
[Model] DQS_PU_PD_240_48_DRIVE_SOCODT120_VOH33
Model_type I/O
Polarity   Inverting
Vinl =  98.000mV
Vinh =  0.268V
Vmeas =  0.183V
Rref =  50.000
Vref =  0.183V
C_comp   1.020pF   1.010pF   1.030pF
[Model Spec]
Vinh   0.268V   0.262V   0.280V
Vinl   98.000mV   92.000mV   0.110V
Vmeas   0.183V   0.177V   0.195V
Vref   0.183V   0.177V   0.195V
Rref   50.000   NA   NA
[Temperature Range]   25.000   0.105k   -40.000
[Voltage Range]   1.100V   1.060V   1.170V
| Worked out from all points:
|   slope of the pulldown table from 0 to 0.165 V, typ, clamps not added: 42.3 ohm
|   GND clamp passes 1 mA (typ) near -0.30 V on its own axis
|   POWER clamp passes 1 mA (typ) near -0.95 V on its own axis
|   rising waveform, R_fixture 50.000, V_fixture 1.100: 20-80 % time 69ps typ, 72.4ps min, 66.6ps max; typ from 0.582 V to 1.1 V
|   rising waveform, R_fixture 50.000, V_fixture 0.0: 20-80 % time 31.3ps typ, 40.2ps min, 25.6ps max; typ from 0 V to 0.244 V
|   falling waveform, R_fixture 50.000, V_fixture 1.100: 20-80 % time 41.1ps typ, 54ps min, 33.1ps max; typ from 1.1 V to 0.582 V
|   falling waveform, R_fixture 50.000, V_fixture 0.0: 20-80 % time 35ps typ, 51.6ps min, 30.3ps max; typ from 0.244 V to 0 V
[Pulldown]
|Voltage   I(typ)   I(min)   I(max)
-1.1V     -13.51mA   -15.24mA   -10.91mA
-930mV    -13.06mA   -15.37mA   -10.79mA
-726mV    -12.89mA   -14.52mA   -11.06mA
-556mV    -12.29mA   -13.01mA   -11.31mA
-454mV    -11.04mA   -11.25mA   -10.65mA
-318mV    -8.03mA    -8.027mA   -7.964mA
158mV     3.751mA    3.687mA    3.768mA
328mV     7.153mA    6.973mA    7.158mA
498mV     9.598mA    9.214mA    9.581mA
668mV     10.93mA    10.37mA    10.89mA
940mV     12.01mA    11.39mA    11.91mA
2.2V      14.71mA    14.14mA    14.31mA
[Pullup]
|Voltage   I(typ)   I(min)   I(max)
-1.1V     1nA        10.92nA    0A
432mV     -168.8uA   -190.8uA   -131.8uA
568mV     -1.092mA   -1.17mA    -975.3uA
704mV     -2.706mA   -2.942mA   -2.412mA
942mV     -6.202mA   -6.816mA   -5.469mA
1.316V    -12.39mA   -13.6mA    -10.88mA
1.452V    -13.99mA   -15.3mA    -12.68mA
1.554V    -14.09mA   -15.62mA   -12.95mA
1.724V    -13.73mA   -15.53mA   -12.2mA
1.928V    -13.51mA   -15.36mA   -11.82mA
2.064V    -13.38mA   -15mA      -11.66mA
2.2V      -13.23mA   -14.25mA   -11.51mA
[GND_clamp]
|Voltage   I(typ)   I(min)   I(max)
-1.1V     -92.78mA   -81.05mA   -109.5mA
-1.031V   -81.73mA   -69.22mA   -97.17mA
-939mV    -68.18mA   -56.02mA   -81.64mA
-824mV    -52mA      -41.83mA   -62.83mA
-686mV    -33.62mA   -26.41mA   -41.32mA
-571mV    -19.76mA   -15.06mA   -24.85mA
-479mV    -10.5mA    -7.76mA    -13.5mA
-410mV    -5.313mA   -3.84mA    -6.916mA
-341mV    -2.007mA   -1.45mA    -2.59mA
-272mV    -506.9uA   -403.5uA   -609.8uA
-180mV    -45.65uA   -51.35uA   -43.55uA
1.1V      0A         0A         0A
[POWER_clamp]
|Voltage   I(typ)   I(min)   I(max)
-1.1V     5.691mA    8.967mA    3.44mA
-1.062V   3.709mA    6.444mA    2.092mA
-1.039V   2.781mA    5.152mA    1.546mA
-1.016V   2.086mA    4.085mA    1.193mA
-970mV    1.21mA     2.539mA    818.5uA
-947mV    943.7uA    2.005mA    716.7uA
-901mV    610.1uA    1.27mA     581.3uA
-855mV    430.7uA    824.1uA    484.6uA
-786mV    289.9uA    439.4uA    366uA
-671mV    155.9uA    155.9uA    203.6uA
-441mV    13.2uA     12.79uA    15.03uA
1.1V      0A         0A         0A
[Ramp]
| variable   typ   min   max
dV/dt_r   0.146/31.315p   0.143/40.324p   0.153/25.661p
dV/dt_f   0.311/41.212p   0.294/54.138p   0.321/33.181p
R_load = 50.000
[Rising Waveform]
R_fixture= 50.000
V_fixture= 1.100
V_fixture_min= 1.060
V_fixture_max= 1.170
|time   V(typ)   V(min)   V(max)
0s        581.6mV    569.9mV    635mV
146ps     582.5mV    570.5mV    633.3mV
208ps     595.1mV    568.9mV    985mV
265ps     913.4mV    553.1mV    1.115V
284ps     974.3mV    596.2mV    1.131V
308ps     1.024V     728.5mV    1.145V
362ps     1.076V     943.9mV    1.162V
435ps     1.092V     1.034V     1.168V
593ps     1.1V       1.057V     1.17V
3ns       1.1V       1.06V      1.17V
[Rising Waveform]
R_fixture= 50.000
V_fixture= 0.0
V_fixture_min= 0.0
V_fixture_max= 0.0
|time   V(typ)   V(min)   V(max)
0s        2.898uV    10.6uV     684.5nV
151ps     145.1uV    22.94uV    4.696mV
194ps     294.7uV    103.2uV    223.6mV
217ps     7.239mV    341.3uV    293.1mV
265ps     208.4mV    -122.3uV   336.1mV
300ps     276.2mV    16.2mV     286.2mV
381ps     291.9mV    245.9mV    256.6mV
485ps     244.6mV    280.3mV    255.1mV
589ps     243.9mV    239.4mV    255mV
3ns       243.9mV    238.7mV    255mV
[Falling Waveform]
R_fixture= 50.000
V_fixture= 1.100
V_fixture_min= 1.060
V_fixture_max= 1.170
|time   V(typ)   V(min)   V(max)
0s        1.1V       1.06V      1.17V
158ps     1.1V       1.06V      1.167V
225ps     1.093V     1.06V      631.9mV
273ps     751.1mV    1.061V     513.2mV
319ps     547.6mV    1.038V     593.6mV
355ps     499.4mV    850.7mV    619.6mV
409ps     537.7mV    602.7mV    631.3mV
492ps     577.3mV    499.9mV    634.6mV
682ps     581.5mV    569mV      635mV
3ns       581.6mV    569.9mV    635mV
[Falling Waveform]
R_fixture= 50.000
V_fixture= 0.0
V_fixture_min= 0.0
V_fixture_max= 0.0
|time   V(typ)   V(min)   V(max)
0s        243.9mV    238.7mV    255mV
146ps     243.7mV    238.4mV    258.4mV
182ps     253mV      238mV      83.12mV
198ps     251.2mV    239mV      36.59mV
217ps     208.9mV    242.7mV    13.49mV
253ps     54.78mV    251.9mV    2.284mV
292ps     8.783mV    182.4mV    -4.942mV
349ps     830.8uV    33.91mV    -507.7uV
427ps     -1.878mV   1.563mV    -8.697uV
3ns       2.805uV    10.66uV    349.9nV
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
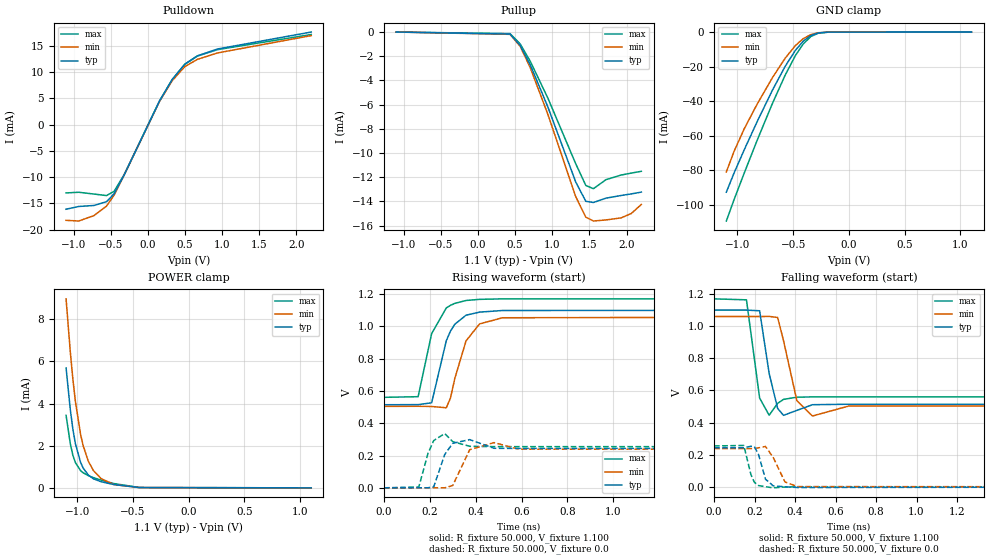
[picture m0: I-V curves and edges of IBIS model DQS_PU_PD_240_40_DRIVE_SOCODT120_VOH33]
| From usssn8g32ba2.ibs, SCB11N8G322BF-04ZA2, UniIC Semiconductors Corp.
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|   Model DQS_PU_PD_240_40_DRIVE_SOCODT120_VOH33
[Model] DQS_PU_PD_240_40_DRIVE_SOCODT120_VOH33
Model_type I/O
Polarity   Inverting
Vinl =  98.000mV
Vinh =  0.268V
Vmeas =  0.183V
Rref =  50.000
Vref =  0.183V
C_comp   1.020pF   1.010pF   1.030pF
[Model Spec]
Vinh   0.268V   0.262V   0.280V
Vinl   98.000mV   92.000mV   0.110V
Vmeas   0.183V   0.177V   0.195V
Vref   0.183V   0.177V   0.195V
Rref   50.000   NA   NA
[Temperature Range]   25.000   0.105k   -40.000
[Voltage Range]   1.100V   1.060V   1.170V
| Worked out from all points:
|   slope of the pulldown table from 0 to 0.165 V, typ, clamps not added: 35.3 ohm
|   GND clamp passes 1 mA (typ) near -0.30 V on its own axis
|   POWER clamp passes 1 mA (typ) near -0.95 V on its own axis
|   rising waveform, R_fixture 50.000, V_fixture 1.100: 20-80 % time 69.3ps typ, 73ps min, 66.7ps max; typ from 0.514 V to 1.1 V
|   rising waveform, R_fixture 50.000, V_fixture 0.0: 20-80 % time 31.3ps typ, 40.1ps min, 25.6ps max; typ from 0 V to 0.244 V
|   falling waveform, R_fixture 50.000, V_fixture 1.100: 20-80 % time 39.2ps typ, 52ps min, 32ps max; typ from 1.1 V to 0.514 V
|   falling waveform, R_fixture 50.000, V_fixture 0.0: 20-80 % time 32.5ps typ, 51ps min, 27.7ps max; typ from 0.244 V to 0 V
[Pulldown]
|Voltage   I(typ)   I(min)   I(max)
-1.1V     -16.13mA   -18.25mA   -13.03mA
-930mV    -15.61mA   -18.38mA   -12.9mA
-726mV    -15.42mA   -17.36mA   -13.24mA
-556mV    -14.7mA    -15.55mA   -13.53mA
-454mV    -13.2mA    -13.45mA   -12.73mA
-318mV    -9.609mA   -9.606mA   -9.529mA
158mV     4.492mA    4.415mA    4.512mA
328mV     8.568mA    8.352mA    8.576mA
498mV     11.5mA     11.04mA    11.48mA
668mV     13.1mA     12.43mA    13.05mA
940mV     14.4mA     13.65mA    14.28mA
2.2V      17.63mA    16.95mA    17.16mA
[Pullup]
|Voltage   I(typ)   I(min)   I(max)
-1.1V     1nA        10.92nA    0A
432mV     -168.8uA   -190.8uA   -131.8uA
568mV     -1.092mA   -1.17mA    -975.3uA
704mV     -2.706mA   -2.942mA   -2.412mA
942mV     -6.202mA   -6.816mA   -5.469mA
1.316V    -12.39mA   -13.6mA    -10.88mA
1.452V    -13.99mA   -15.3mA    -12.68mA
1.554V    -14.09mA   -15.62mA   -12.95mA
1.724V    -13.73mA   -15.53mA   -12.2mA
1.928V    -13.51mA   -15.36mA   -11.82mA
2.064V    -13.38mA   -15mA      -11.66mA
2.2V      -13.23mA   -14.25mA   -11.51mA
[GND_clamp]
|Voltage   I(typ)   I(min)   I(max)
-1.1V     -92.78mA   -81.05mA   -109.5mA
-1.031V   -81.73mA   -69.22mA   -97.17mA
-939mV    -68.18mA   -56.02mA   -81.64mA
-824mV    -52mA      -41.83mA   -62.83mA
-686mV    -33.62mA   -26.41mA   -41.32mA
-571mV    -19.76mA   -15.06mA   -24.85mA
-479mV    -10.5mA    -7.76mA    -13.5mA
-410mV    -5.313mA   -3.84mA    -6.916mA
-341mV    -2.007mA   -1.45mA    -2.59mA
-272mV    -506.9uA   -403.5uA   -609.8uA
-180mV    -45.65uA   -51.35uA   -43.55uA
1.1V      0A         0A         0A
[POWER_clamp]
|Voltage   I(typ)   I(min)   I(max)
-1.1V     5.691mA    8.967mA    3.44mA
-1.062V   3.709mA    6.444mA    2.092mA
-1.039V   2.781mA    5.152mA    1.546mA
-1.016V   2.086mA    4.085mA    1.193mA
-970mV    1.21mA     2.539mA    818.5uA
-947mV    943.7uA    2.005mA    716.7uA
-901mV    610.1uA    1.27mA     581.3uA
-855mV    430.7uA    824.1uA    484.6uA
-786mV    289.9uA    439.4uA    366uA
-671mV    155.9uA    155.9uA    203.6uA
-441mV    13.2uA     12.79uA    15.03uA
1.1V      0A         0A         0A
[Ramp]
| variable   typ   min   max
dV/dt_r   0.146/31.350p   0.143/40.203p   0.153/25.549p
dV/dt_f   0.351/39.417p   0.333/52.138p   0.366/32.077p
R_load = 50.000
[Rising Waveform]
R_fixture= 50.000
V_fixture= 1.100
V_fixture_min= 1.060
V_fixture_max= 1.170
|time   V(typ)   V(min)   V(max)
0s        514.4mV    504.3mV    560.3mV
149ps     515.2mV    505mV      564.3mV
208ps     526.4mV    503.6mV    955.2mV
272ps     911.3mV    495.6mV    1.114V
290ps     970.1mV    555.8mV    1.13V
309ps     1.013V     677.3mV    1.142V
358ps     1.069V     910mV      1.16V
417ps     1.088V     1.015V     1.167V
517ps     1.098V     1.053V     1.17V
3ns       1.1V       1.06V      1.17V
[Rising Waveform]
R_fixture= 50.000
V_fixture= 0.0
V_fixture_min= 0.0
V_fixture_max= 0.0
|time   V(typ)   V(min)   V(max)
0s        2.608uV    9.547uV    615.8nV
152ps     222.7uV    24.65uV    5.22mV
192ps     393.8uV    109.9uV    212.9mV
217ps     5.99mV     430.7uV    292.4mV
265ps     206.6mV    -178.1uV   336.1mV
300ps     275.8mV    14.43mV    286mV
374ps     298.5mV    236mV      257mV
480ps     244.7mV    279.9mV    255.1mV
588ps     243.9mV    239.4mV    255mV
3ns       243.9mV    238.7mV    255mV
[Falling Waveform]
R_fixture= 50.000
V_fixture= 1.100
V_fixture_min= 1.060
V_fixture_max= 1.170
|time   V(typ)   V(min)   V(max)
0s        1.1V       1.06V      1.17V
160ps     1.1V       1.06V      1.164V
225ps     1.096V     1.06V      552.8mV
272ps     706.4mV    1.061V     445.9mV
314ps     488.1mV    1.054V     520mV
343ps     445.4mV    909.4mV    544.6mV
409ps     476.1mV    536.5mV    558.3mV
486ps     511.5mV    441.2mV    560.1mV
666ps     514.4mV    503.6mV    560.3mV
3ns       514.4mV    504.3mV    560.3mV
[Falling Waveform]
R_fixture= 50.000
V_fixture= 0.0
V_fixture_min= 0.0
V_fixture_max= 0.0
|time   V(typ)   V(min)   V(max)
0s        243.9mV    238.7mV    255mV
147ps     243.8mV    238.3mV    257.9mV
182ps     252.8mV    238mV      76.83mV
199ps     250.8mV    239.1mV    28.78mV
220ps     200.2mV    243.4mV    8.42mV
254ps     47.92mV    251.6mV    1.467mV
292ps     6.825mV    183.7mV    -5.775mV
350ps     632.4uV    31.03mV    -436.1uV
412ps     -3.605mV   2.235mV    -10.88uV
3ns       517.9nV    6.743uV    160.3nV
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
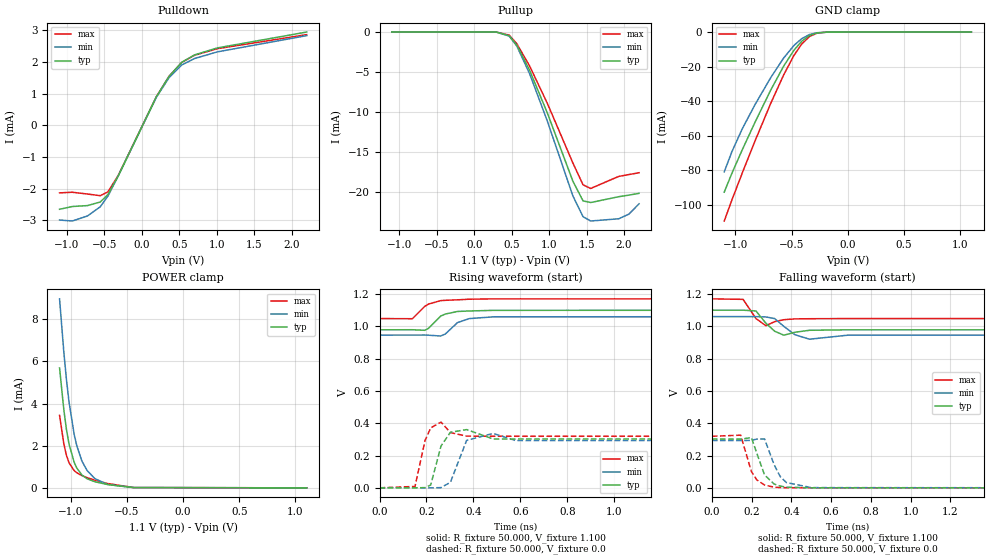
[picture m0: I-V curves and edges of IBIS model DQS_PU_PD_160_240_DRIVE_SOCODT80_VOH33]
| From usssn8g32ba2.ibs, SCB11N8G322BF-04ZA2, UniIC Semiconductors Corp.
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|   Model DQS_PU_PD_160_240_DRIVE_SOCODT80_VOH33
[Model] DQS_PU_PD_160_240_DRIVE_SOCODT80_VOH33
Model_type I/O
Polarity   Inverting
Vinl =  98.000mV
Vinh =  0.268V
Vmeas =  0.183V
Rref =  50.000
Vref =  0.183V
C_comp   1.020pF   1.010pF   1.030pF
[Model Spec]
Vinh   0.268V   0.262V   0.280V
Vinl   98.000mV   92.000mV   0.110V
Vmeas   0.183V   0.177V   0.195V
Vref   0.183V   0.177V   0.195V
Rref   50.000   NA   NA
[Temperature Range]   25.000   0.105k   -40.000
[Voltage Range]   1.100V   1.060V   1.170V
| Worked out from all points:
|   slope of the pulldown table from 0 to 0.165 V, typ, clamps not added: 211 ohm
|   GND clamp passes 1 mA (typ) near -0.30 V on its own axis
|   POWER clamp passes 1 mA (typ) near -0.95 V on its own axis
|   rising waveform, R_fixture 50.000, V_fixture 1.100: 20-80 % time 61.8ps typ, 61.1ps min, 61.8ps max; typ from 0.978 V to 1.1 V
|   rising waveform, R_fixture 50.000, V_fixture 0.0: 20-80 % time 29.7ps typ, 38.7ps min, 23.9ps max; typ from 0 V to 0.302 V
|   falling waveform, R_fixture 50.000, V_fixture 1.100: 20-80 % time 45.4ps typ, 61.1ps min, 35ps max; typ from 1.1 V to 0.978 V
|   falling waveform, R_fixture 50.000, V_fixture 0.0: 20-80 % time 55.5ps typ, 62.9ps min, 52.6ps max; typ from 0.302 V to 0 V
[Pulldown]
|Voltage   I(typ)   I(min)   I(max)
-1.1V     -2.652mA   -2.992mA   -2.134mA
-930mV    -2.565mA   -3.023mA   -2.114mA
-726mV    -2.535mA   -2.862mA   -2.171mA
-556mV    -2.422mA   -2.572mA   -2.223mA
-454mV    -2.185mA   -2.234mA   -2.101mA
-318mV    -1.604mA   -1.606mA   -1.589mA
192mV     900.6uA    884.3uA    903.8uA
362mV     1.549mA    1.507mA    1.549mA
532mV     1.993mA    1.907mA    1.988mA
702mV     2.225mA    2.111mA    2.215mA
1.008V    2.447mA    2.322mA    2.422mA
2.2V      2.948mA    2.835mA    2.866mA
[Pullup]
|Voltage   I(typ)   I(min)   I(max)
-1.1V     1.606nA    16.44nA    0A
296mV     -8.845uA   -14.64uA   -4.922uA
466mV     -464.7uA   -507.7uA   -387.5uA
568mV     -1.641mA   -1.758mA   -1.466mA
738mV     -4.764mA   -5.196mA   -4.236mA
976mV     -10.14mA   -11.16mA   -8.932mA
1.316V    -18.65mA   -20.49mA   -16.37mA
1.452V    -21.12mA   -23.1mA    -19.11mA
1.554V    -21.33mA   -23.64mA   -19.57mA
1.928V    -20.6mA    -23.36mA   -18.06mA
2.064V    -20.4mA    -22.78mA   -17.83mA
2.2V      -20.18mA   -21.49mA   -17.6mA
[GND_clamp]
|Voltage   I(typ)   I(min)   I(max)
-1.1V     -92.78mA   -81.05mA   -109.5mA
-1.031V   -81.73mA   -69.22mA   -97.17mA
-939mV    -68.18mA   -56.02mA   -81.64mA
-824mV    -52mA      -41.83mA   -62.83mA
-686mV    -33.62mA   -26.41mA   -41.32mA
-571mV    -19.76mA   -15.06mA   -24.85mA
-479mV    -10.5mA    -7.76mA    -13.5mA
-410mV    -5.313mA   -3.84mA    -6.916mA
-341mV    -2.007mA   -1.45mA    -2.59mA
-272mV    -506.9uA   -403.5uA   -609.8uA
-180mV    -45.65uA   -51.35uA   -43.55uA
1.1V      0A         0A         0A
[POWER_clamp]
|Voltage   I(typ)   I(min)   I(max)
-1.1V     5.691mA    8.967mA    3.44mA
-1.062V   3.709mA    6.444mA    2.092mA
-1.039V   2.781mA    5.152mA    1.546mA
-1.016V   2.086mA    4.085mA    1.193mA
-970mV    1.21mA     2.539mA    818.5uA
-947mV    943.7uA    2.005mA    716.7uA
-901mV    610.1uA    1.27mA     581.3uA
-855mV    430.7uA    824.1uA    484.6uA
-786mV    289.9uA    439.4uA    366uA
-671mV    155.9uA    155.9uA    203.6uA
-441mV    13.2uA     12.79uA    15.03uA
1.1V      0A         0A         0A
[Ramp]
| variable   typ   min   max
dV/dt_r   0.181/29.827p   0.176/38.721p   0.192/24.123p
dV/dt_f   72.904m/45.570p   68.572m/61.281p   73.268m/35.048p
R_load = 50.000
[Rising Waveform]
R_fixture= 50.000
V_fixture= 1.100
V_fixture_min= 1.060
V_fixture_max= 1.170
|time   V(typ)   V(min)   V(max)
0s        978.5mV    945.7mV    1.048V
140ps     978.8mV    945.9mV    1.047V
193ps     975.3mV    946mV      1.124V
209ps     988.1mV    945mV      1.138V
260ps     1.063V     939.9mV    1.159V
280ps     1.076V     952.2mV    1.161V
332ps     1.092V     1.023V     1.164V
383ps     1.095V     1.048V     1.168V
489ps     1.099V     1.059V     1.17V
3ns       1.1V       1.06V      1.17V
[Rising Waveform]
R_fixture= 50.000
V_fixture= 0.0
V_fixture_min= 0.0
V_fixture_max= 0.0
|time   V(typ)   V(min)   V(max)
0s        5.234uV    19.06uV    1.239uV
151ps     -194.2uV   66.06uV    8.497mV
194ps     1.149mV    -93.12uV   293.7mV
218ps     17.47mV    -291.2uV   371.2mV
262ps     259.3mV    1.042mV    406.8mV
302ps     343.7mV    34.49mV    341.8mV
371ps     360.6mV    293.8mV    320mV
484ps     302.1mV    336.8mV    319.2mV
579ps     302.1mV    292.7mV    319.2mV
3ns       302.1mV    293.3mV    319.2mV
[Falling Waveform]
R_fixture= 50.000
V_fixture= 1.100
V_fixture_min= 1.060
V_fixture_max= 1.170
|time   V(typ)   V(min)   V(max)
0s        1.1V       1.06V      1.17V
157ps     1.1V       1.06V      1.167V
222ps     1.095V     1.06V      1.048V
272ps     1.019V     1.058V     1.004V
316ps     969.7mV    1.048V     1.029V
362ps     945mV      1V         1.041V
417ps     963.1mV    948.5mV    1.046V
491ps     975.5mV    920.3mV    1.047V
684ps     978.5mV    945.1mV    1.048V
3ns       978.5mV    945.7mV    1.048V
[Falling Waveform]
R_fixture= 50.000
V_fixture= 0.0
V_fixture_min= 0.0
V_fixture_max= 0.0
|time   V(typ)   V(min)   V(max)
0s        302.1mV    293.3mV    319.2mV
145ps     301.6mV    292.9mV    326.1mV
199ps     311mV      293.7mV    100.6mV
226ps     215mV      301.8mV    49.33mV
265ps     79.85mV    302.7mV    17.39mV
313ps     23.69mV    144.3mV    4.268mV
344ps     10.83mV    69.39mV    1.975mV
375ps     4.426mV    32.98mV    908.9uV
500ps     127.9uV    1.33mV     40.15uV
3ns       5.238uV    19.13uV    497.2nV
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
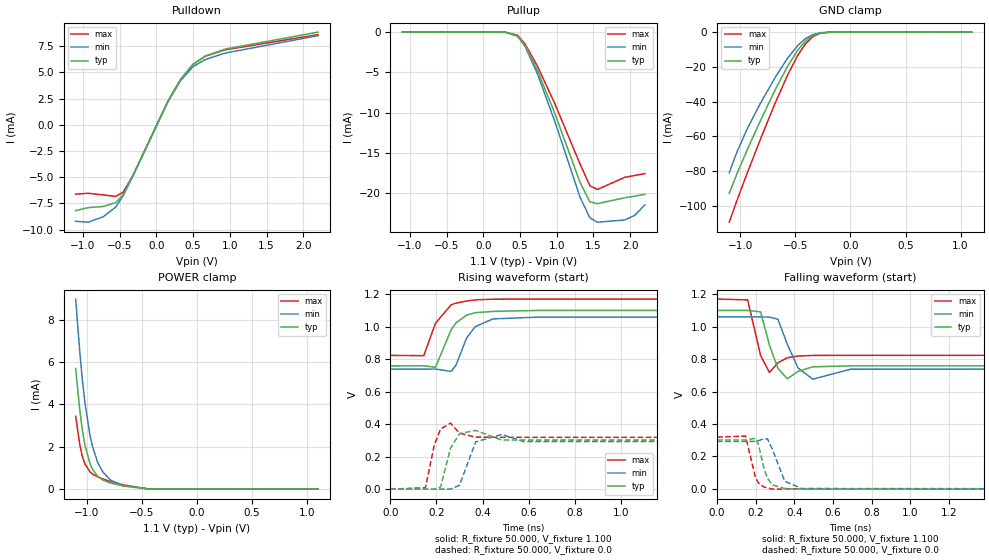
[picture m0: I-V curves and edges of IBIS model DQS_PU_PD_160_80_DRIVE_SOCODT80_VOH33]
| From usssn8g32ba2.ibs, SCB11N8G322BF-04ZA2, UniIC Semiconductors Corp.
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|   Model DQS_PU_PD_160_80_DRIVE_SOCODT80_VOH33
[Model] DQS_PU_PD_160_80_DRIVE_SOCODT80_VOH33
Model_type I/O
Polarity   Inverting
Vinl =  98.000mV
Vinh =  0.268V
Vmeas =  0.183V
Rref =  50.000
Vref =  0.183V
C_comp   1.020pF   1.010pF   1.030pF
[Model Spec]
Vinh   0.268V   0.262V   0.280V
Vinl   98.000mV   92.000mV   0.110V
Vmeas   0.183V   0.177V   0.195V
Vref   0.183V   0.177V   0.195V
Rref   50.000   NA   NA
[Temperature Range]   25.000   0.105k   -40.000
[Voltage Range]   1.100V   1.060V   1.170V
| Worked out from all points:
|   slope of the pulldown table from 0 to 0.165 V, typ, clamps not added: 70.2 ohm
|   GND clamp passes 1 mA (typ) near -0.30 V on its own axis
|   POWER clamp passes 1 mA (typ) near -0.95 V on its own axis
|   rising waveform, R_fixture 50.000, V_fixture 1.100: 20-80 % time 67ps typ, 69.3ps min, 65.4ps max; typ from 0.759 V to 1.1 V
|   rising waveform, R_fixture 50.000, V_fixture 0.0: 20-80 % time 29.4ps typ, 38ps min, 23.9ps max; typ from 0 V to 0.302 V
|   falling waveform, R_fixture 50.000, V_fixture 1.100: 20-80 % time 43.6ps typ, 57.2ps min, 34.5ps max; typ from 1.1 V to 0.759 V
|   falling waveform, R_fixture 50.000, V_fixture 0.0: 20-80 % time 41.6ps typ, 54.6ps min, 37.5ps max; typ from 0.302 V to 0 V
[Pulldown]
|Voltage   I(typ)   I(min)   I(max)
-1.1V     -8.193mA   -9.206mA   -6.618mA
-930mV    -7.906mA   -9.295mA   -6.537mA
-726mV    -7.797mA   -8.78mA    -6.691mA
-556mV    -7.432mA   -7.863mA   -6.841mA
-454mV    -6.673mA   -6.794mA   -6.44mA
-318mV    -4.841mA   -4.838mA   -4.804mA
158mV     2.257mA    2.219mA    2.267mA
328mV     4.302mA    4.194mA    4.305mA
498mV     5.77mA     5.539mA    5.759mA
668mV     6.567mA    6.233mA    6.54mA
940mV     7.217mA    6.841mA    7.152mA
2.2V      8.836mA    8.496mA    8.595mA
[Pullup]
|Voltage   I(typ)   I(min)   I(max)
-1.1V     1.606nA    16.44nA    0A
296mV     -8.845uA   -14.64uA   -4.922uA
466mV     -464.7uA   -507.7uA   -387.5uA
568mV     -1.641mA   -1.758mA   -1.466mA
738mV     -4.764mA   -5.196mA   -4.236mA
976mV     -10.14mA   -11.16mA   -8.932mA
1.316V    -18.65mA   -20.49mA   -16.37mA
1.452V    -21.12mA   -23.1mA    -19.11mA
1.554V    -21.33mA   -23.64mA   -19.57mA
1.928V    -20.6mA    -23.36mA   -18.06mA
2.064V    -20.4mA    -22.78mA   -17.83mA
2.2V      -20.18mA   -21.49mA   -17.6mA
[GND_clamp]
|Voltage   I(typ)   I(min)   I(max)
-1.1V     -92.78mA   -81.05mA   -109.5mA
-1.031V   -81.73mA   -69.22mA   -97.17mA
-939mV    -68.18mA   -56.02mA   -81.64mA
-824mV    -52mA      -41.83mA   -62.83mA
-686mV    -33.62mA   -26.41mA   -41.32mA
-571mV    -19.76mA   -15.06mA   -24.85mA
-479mV    -10.5mA    -7.76mA    -13.5mA
-410mV    -5.313mA   -3.84mA    -6.916mA
-341mV    -2.007mA   -1.45mA    -2.59mA
-272mV    -506.9uA   -403.5uA   -609.8uA
-180mV    -45.65uA   -51.35uA   -43.55uA
1.1V      0A         0A         0A
[POWER_clamp]
|Voltage   I(typ)   I(min)   I(max)
-1.1V     5.691mA    8.967mA    3.44mA
-1.062V   3.709mA    6.444mA    2.092mA
-1.039V   2.781mA    5.152mA    1.546mA
-1.016V   2.086mA    4.085mA    1.193mA
-970mV    1.21mA     2.539mA    818.5uA
-947mV    943.7uA    2.005mA    716.7uA
-901mV    610.1uA    1.27mA     581.3uA
-855mV    430.7uA    824.1uA    484.6uA
-786mV    289.9uA    439.4uA    366uA
-671mV    155.9uA    155.9uA    203.6uA
-441mV    13.2uA     12.79uA    15.03uA
1.1V      0A         0A         0A
[Ramp]
| variable   typ   min   max
dV/dt_r   0.181/29.506p   0.176/37.971p   0.192/23.990p
dV/dt_f   0.205/43.637p   0.193/57.210p   0.208/34.598p
R_load = 50.000
[Rising Waveform]
R_fixture= 50.000
V_fixture= 1.100
V_fixture_min= 1.060
V_fixture_max= 1.170
|time   V(typ)   V(min)   V(max)
0s        758.6mV    738.8mV    823.3mV
145ps     759.4mV    739.2mV    821.6mV
196ps     750.2mV    739.5mV    1.022V
264ps     982.5mV    724.7mV    1.135V
285ps     1.024V     764mV      1.145V
331ps     1.071V     931.5mV    1.158V
368ps     1.086V     999.9mV    1.165V
445ps     1.094V     1.048V     1.169V
640ps     1.1V       1.059V     1.17V
3ns       1.1V       1.06V      1.17V
[Rising Waveform]
R_fixture= 50.000
V_fixture= 0.0
V_fixture_min= 0.0
V_fixture_max= 0.0
|time   V(typ)   V(min)   V(max)
0s        3.731uV    13.63uV    881.9nV
152ps     -68.26uV   39.27uV    8.595mV
191ps     585.6uV    -2.92uV    274.2mV
218ps     13.72mV    3.319uV    370.3mV
261ps     252.4mV    467.3uV    406.5mV
300ps     341.7mV    23.75mV    344.3mV
370ps     361.5mV    291.2mV    320mV
483ps     302.1mV    336.8mV    319.2mV
578ps     302.1mV    292.7mV    319.2mV
3ns       302.1mV    293.3mV    319.2mV
[Falling Waveform]
R_fixture= 50.000
V_fixture= 1.100
V_fixture_min= 1.060
V_fixture_max= 1.170
|time   V(typ)   V(min)   V(max)
0s        1.1V       1.06V      1.17V
158ps     1.1V       1.06V      1.165V
225ps     1.091V     1.06V      822.4mV
271ps     885.6mV    1.059V     717.5mV
315ps     742.7mV    1.045V     778mV
363ps     678.9mV    892.6mV    808.4mV
419ps     724.2mV    745.4mV    819.1mV
495ps     752.6mV    676.4mV    822.6mV
690ps     758.5mV    737.5mV    823.3mV
3ns       758.6mV    738.8mV    823.3mV
[Falling Waveform]
R_fixture= 50.000
V_fixture= 0.0
V_fixture_min= 0.0
V_fixture_max= 0.0
|time   V(typ)   V(min)   V(max)
0s        302.1mV    293.3mV    319.2mV
147ps     301.7mV    292.8mV    325.5mV
199ps     312.6mV    293.6mV    67.85mV
214ps     274.2mV    297.2mV    37.41mV
242ps     128.5mV    309mV      12.46mV
261ps     64.3mV     308.2mV    5.517mV
288ps     23.93mV    238.4mV    -1.408mV
350ps     2.5mV      47.42mV    -349.9uV
437ps     -899uV     2.645mV    -12.06uV
3ns       843.1nV    13.56uV    509.2nV
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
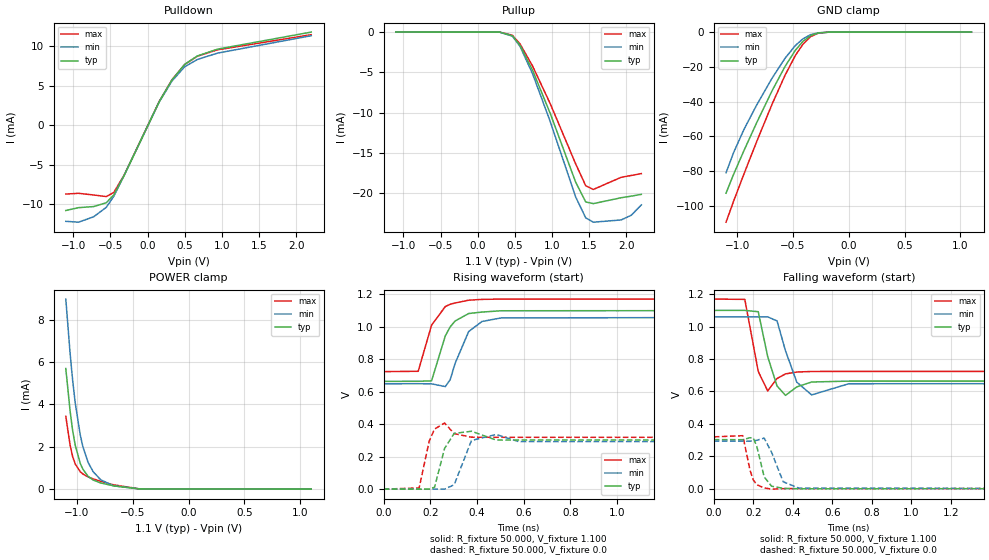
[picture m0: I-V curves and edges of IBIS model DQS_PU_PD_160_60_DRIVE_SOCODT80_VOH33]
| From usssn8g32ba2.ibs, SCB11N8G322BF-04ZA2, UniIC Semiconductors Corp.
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|   Model DQS_PU_PD_160_60_DRIVE_SOCODT80_VOH33
[Model] DQS_PU_PD_160_60_DRIVE_SOCODT80_VOH33
Model_type I/O
Polarity   Inverting
Vinl =  98.000mV
Vinh =  0.268V
Vmeas =  0.183V
Rref =  50.000
Vref =  0.183V
C_comp   1.020pF   1.010pF   1.030pF
[Model Spec]
Vinh   0.268V   0.262V   0.280V
Vinl   98.000mV   92.000mV   0.110V
Vmeas   0.183V   0.177V   0.195V
Vref   0.183V   0.177V   0.195V
Rref   50.000   NA   NA
[Temperature Range]   25.000   0.105k   -40.000
[Voltage Range]   1.100V   1.060V   1.170V
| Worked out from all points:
|   slope of the pulldown table from 0 to 0.165 V, typ, clamps not added: 52.7 ohm
|   GND clamp passes 1 mA (typ) near -0.30 V on its own axis
|   POWER clamp passes 1 mA (typ) near -0.95 V on its own axis
|   rising waveform, R_fixture 50.000, V_fixture 1.100: 20-80 % time 67.9ps typ, 70.7ps min, 65.9ps max; typ from 0.663 V to 1.1 V
|   rising waveform, R_fixture 50.000, V_fixture 0.0: 20-80 % time 29.3ps typ, 37.8ps min, 23.8ps max; typ from 0 V to 0.302 V
|   falling waveform, R_fixture 50.000, V_fixture 1.100: 20-80 % time 42.7ps typ, 56ps min, 33.9ps max; typ from 1.1 V to 0.663 V
|   falling waveform, R_fixture 50.000, V_fixture 0.0: 20-80 % time 37.6ps typ, 52.7ps min, 33ps max; typ from 0.302 V to 0 V
[Pulldown]
|Voltage   I(typ)   I(min)   I(max)
-1.1V     -10.83mA   -12.2mA    -8.746mA
-930mV    -10.47mA   -12.31mA   -8.649mA
-726mV    -10.33mA   -11.63mA   -8.863mA
-556mV    -9.849mA   -10.43mA   -9.063mA
-454mV    -8.849mA   -9.016mA   -8.534mA
-318mV    -6.436mA   -6.433mA   -6.383mA
158mV     3.005mA    2.954mA    3.019mA
328mV     5.729mA    5.586mA    5.734mA
498mV     7.686mA    7.379mA    7.672mA
668mV     8.751mA    8.306mA    8.715mA
940mV     9.618mA    9.116mA    9.532mA
2.2V      11.78mA    11.32mA    11.45mA
[Pullup]
|Voltage   I(typ)   I(min)   I(max)
-1.1V     1.606nA    16.44nA    0A
296mV     -8.845uA   -14.64uA   -4.922uA
466mV     -464.7uA   -507.7uA   -387.5uA
568mV     -1.641mA   -1.758mA   -1.466mA
738mV     -4.764mA   -5.196mA   -4.236mA
976mV     -10.14mA   -11.16mA   -8.932mA
1.316V    -18.65mA   -20.49mA   -16.37mA
1.452V    -21.12mA   -23.1mA    -19.11mA
1.554V    -21.33mA   -23.64mA   -19.57mA
1.928V    -20.6mA    -23.36mA   -18.06mA
2.064V    -20.4mA    -22.78mA   -17.83mA
2.2V      -20.18mA   -21.49mA   -17.6mA
[GND_clamp]
|Voltage   I(typ)   I(min)   I(max)
-1.1V     -92.78mA   -81.05mA   -109.5mA
-1.031V   -81.73mA   -69.22mA   -97.17mA
-939mV    -68.18mA   -56.02mA   -81.64mA
-824mV    -52mA      -41.83mA   -62.83mA
-686mV    -33.62mA   -26.41mA   -41.32mA
-571mV    -19.76mA   -15.06mA   -24.85mA
-479mV    -10.5mA    -7.76mA    -13.5mA
-410mV    -5.313mA   -3.84mA    -6.916mA
-341mV    -2.007mA   -1.45mA    -2.59mA
-272mV    -506.9uA   -403.5uA   -609.8uA
-180mV    -45.65uA   -51.35uA   -43.55uA
1.1V      0A         0A         0A
[POWER_clamp]
|Voltage   I(typ)   I(min)   I(max)
-1.1V     5.691mA    8.967mA    3.44mA
-1.062V   3.709mA    6.444mA    2.092mA
-1.039V   2.781mA    5.152mA    1.546mA
-1.016V   2.086mA    4.085mA    1.193mA
-970mV    1.21mA     2.539mA    818.5uA
-947mV    943.7uA    2.005mA    716.7uA
-901mV    610.1uA    1.27mA     581.3uA
-855mV    430.7uA    824.1uA    484.6uA
-786mV    289.9uA    439.4uA    366uA
-671mV    155.9uA    155.9uA    203.6uA
-441mV    13.2uA     12.79uA    15.03uA
1.1V      0A         0A         0A
[Ramp]
| variable   typ   min   max
dV/dt_r   0.181/29.310p   0.176/37.899p   0.192/23.883p
dV/dt_f   0.262/42.697p   0.247/56.134p   0.268/33.991p
R_load = 50.000
[Rising Waveform]
R_fixture= 50.000
V_fixture= 1.100
V_fixture_min= 1.060
V_fixture_max= 1.170
|time   V(typ)   V(min)   V(max)
0s        663.5mV    648.6mV    723.5mV
148ps     664.2mV    649.2mV    725.5mV
205ps     666.3mV    648.4mV    1.009V
264ps     943.4mV    631.3mV    1.124V
285ps     999.1mV    674.4mV    1.138V
306ps     1.035V     774.3mV    1.146V
364ps     1.081V     970mV      1.163V
421ps     1.09V      1.032V     1.168V
503ps     1.098V     1.054V     1.17V
3ns       1.1V       1.06V      1.17V
[Rising Waveform]
R_fixture= 50.000
V_fixture= 0.0
V_fixture_min= 0.0
V_fixture_max= 0.0
|time   V(typ)   V(min)   V(max)
0s        3.261uV    11.92uV    770.5nV
152ps     2.993uV    36.38uV    7.731mV
195ps     777.5uV    19.92uV    295.1mV
218ps     12.05mV    119.1uV    370.2mV
261ps     251mV      445.2uV    406.7mV
302ps     343.2mV    27mV       341.8mV
376ps     356.5mV    299.6mV    319.8mV
482ps     302.1mV    336.7mV    319.2mV
578ps     302.1mV    292.7mV    319.2mV
3ns       302.1mV    293.3mV    319.2mV
[Falling Waveform]
R_fixture= 50.000
V_fixture= 1.100
V_fixture_min= 1.060
V_fixture_max= 1.170
|time   V(typ)   V(min)   V(max)
0s        1.1V       1.06V      1.17V
157ps     1.1V       1.06V      1.168V
225ps     1.092V     1.06V      723.2mV
273ps     814mV      1.06V      602.5mV
320ps     633.4mV    1.035V     679.2mV
363ps     575.3mV    850.2mV    708.1mV
420ps     627.7mV    656.9mV    719.6mV
495ps     657.9mV    578.3mV    722.9mV
683ps     663.4mV    647.2mV    723.5mV
3ns       663.5mV    648.6mV    723.5mV
[Falling Waveform]
R_fixture= 50.000
V_fixture= 0.0
V_fixture_min= 0.0
V_fixture_max= 0.0
|time   V(typ)   V(min)   V(max)
0s        302.1mV    293.3mV    319.2mV
147ps     301.7mV    292.8mV    326.5mV
183ps     313.9mV    292.3mV    115.5mV
199ps     313.3mV    293.6mV    55.56mV
217ps     263.6mV    298.1mV    24.08mV
255ps     71.93mV    311.6mV    4.249mV
292ps     14.98mV    225.2mV    -3.68mV
351ps     1.368mV    42.17mV    -466.3uV
432ps     -1.345mV   2.114mV    -12.21uV
3ns       -322.9nV   11.92uV    372.1nV
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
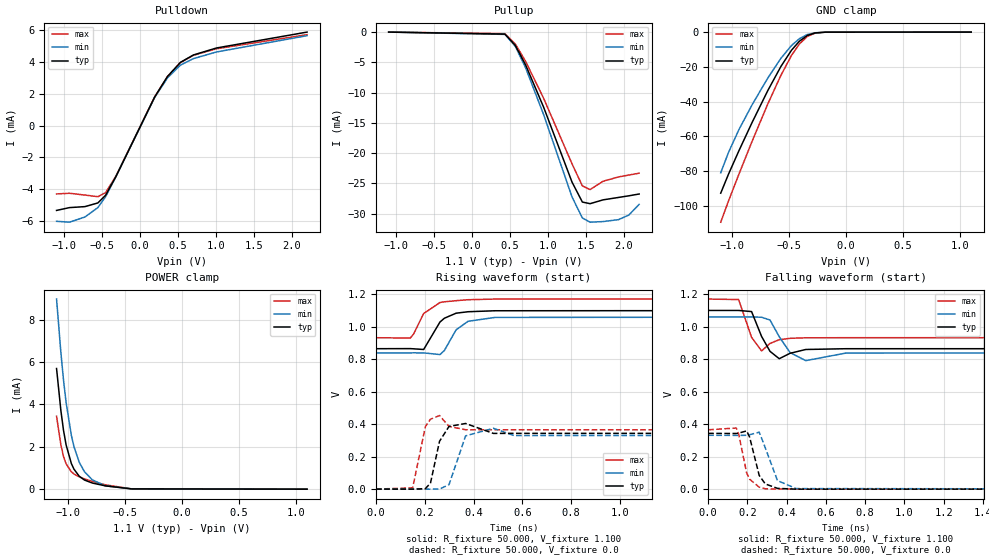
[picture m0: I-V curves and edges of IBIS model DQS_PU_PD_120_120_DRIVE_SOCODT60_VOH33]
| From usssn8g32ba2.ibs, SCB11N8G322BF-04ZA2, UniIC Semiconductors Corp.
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|   Model DQS_PU_PD_120_120_DRIVE_SOCODT60_VOH33
[Model] DQS_PU_PD_120_120_DRIVE_SOCODT60_VOH33
Model_type I/O
Polarity   Inverting
Vinl =  98.000mV
Vinh =  0.268V
Vmeas =  0.183V
Rref =  50.000
Vref =  0.183V
C_comp   1.020pF   1.010pF   1.030pF
[Model Spec]
Vinh   0.268V   0.262V   0.280V
Vinl   98.000mV   92.000mV   0.110V
Vmeas   0.183V   0.177V   0.195V
Vref   0.183V   0.177V   0.195V
Rref   50.000   NA   NA
[Temperature Range]   25.000   0.105k   -40.000
[Voltage Range]   1.100V   1.060V   1.170V
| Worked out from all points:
|   slope of the pulldown table from 0 to 0.165 V, typ, clamps not added: 105 ohm
|   GND clamp passes 1 mA (typ) near -0.30 V on its own axis
|   POWER clamp passes 1 mA (typ) near -0.95 V on its own axis
|   rising waveform, R_fixture 50.000, V_fixture 1.100: 20-80 % time 63.6ps typ, 63.7ps min, 63.2ps max; typ from 0.864 V to 1.1 V
|   rising waveform, R_fixture 50.000, V_fixture 0.0: 20-80 % time 27.9ps typ, 36.5ps min, 22.5ps max; typ from 0 V to 0.343 V
|   falling waveform, R_fixture 50.000, V_fixture 1.100: 20-80 % time 44.3ps typ, 58.9ps min, 34.6ps max; typ from 1.1 V to 0.864 V
|   falling waveform, R_fixture 50.000, V_fixture 0.0: 20-80 % time 46.5ps typ, 56.5ps min, 43.2ps max; typ from 0.343 V to 0 V
[Pulldown]
|Voltage   I(typ)   I(min)   I(max)
-1.1V     -5.34mA    -6.026mA   -4.302mA
-930mV    -5.164mA   -6.082mA   -4.26mA
-726mV    -5.101mA   -5.754mA   -4.373mA
-556mV    -4.87mA    -5.165mA   -4.475mA
-454mV    -4.386mA   -4.479mA   -4.222mA
-318mV    -3.209mA   -3.211mA   -3.18mA
192mV     1.799mA    1.766mA    1.806mA
362mV     3.096mA    3.011mA    3.096mA
532mV     3.983mA    3.811mA    3.973mA
702mV     4.448mA    4.219mA    4.427mA
1.008V    4.891mA    4.64mA     4.842mA
2.2V      5.891mA    5.665mA    5.73mA
[Pullup]
|Voltage   I(typ)   I(min)   I(max)
-1.1V     2.106nA    21.95nA    0A
432mV     -337.7uA   -381.6uA   -263.6uA
568mV     -2.186mA   -2.341mA   -1.952mA
704mV     -5.417mA   -5.891mA   -4.827mA
942mV     -12.42mA   -13.65mA   -10.95mA
1.316V    -24.8mA    -27.25mA   -21.78mA
1.452V    -28.09mA   -30.72mA   -25.42mA
1.554V    -28.36mA   -31.42mA   -26.03mA
1.724V    -27.73mA   -31.32mA   -24.66mA
1.928V    -27.33mA   -31mA      -23.94mA
2.064V    -27.06mA   -30.24mA   -23.63mA
2.2V      -26.76mA   -28.47mA   -23.32mA
[GND_clamp]
|Voltage   I(typ)   I(min)   I(max)
-1.1V     -92.78mA   -81.05mA   -109.5mA
-1.031V   -81.73mA   -69.22mA   -97.17mA
-939mV    -68.18mA   -56.02mA   -81.64mA
-824mV    -52mA      -41.83mA   -62.83mA
-686mV    -33.62mA   -26.41mA   -41.32mA
-571mV    -19.76mA   -15.06mA   -24.85mA
-479mV    -10.5mA    -7.76mA    -13.5mA
-410mV    -5.313mA   -3.84mA    -6.916mA
-341mV    -2.007mA   -1.45mA    -2.59mA
-272mV    -506.9uA   -403.5uA   -609.8uA
-180mV    -45.65uA   -51.35uA   -43.55uA
1.1V      0A         0A         0A
[POWER_clamp]
|Voltage   I(typ)   I(min)   I(max)
-1.1V     5.691mA    8.967mA    3.44mA
-1.062V   3.709mA    6.444mA    2.092mA
-1.039V   2.781mA    5.152mA    1.546mA
-1.016V   2.086mA    4.085mA    1.193mA
-970mV    1.21mA     2.539mA    818.5uA
-947mV    943.7uA    2.005mA    716.7uA
-901mV    610.1uA    1.27mA     581.3uA
-855mV    430.7uA    824.1uA    484.6uA
-786mV    289.9uA    439.4uA    366uA
-671mV    155.9uA    155.9uA    203.6uA
-441mV    13.2uA     12.79uA    15.03uA
1.1V      0A         0A         0A
[Ramp]
| variable   typ   min   max
dV/dt_r   0.206/28.069p   0.199/36.722p   0.219/22.700p
dV/dt_f   0.141/44.376p   0.133/58.795p   0.143/34.605p
R_load = 50.000
[Rising Waveform]
R_fixture= 50.000
V_fixture= 1.100
V_fixture_min= 1.060
V_fixture_max= 1.170
|time   V(typ)   V(min)   V(max)
0s        864.4mV    838.5mV    932.1mV
140ps     865mV      838.7mV    929.9mV
153ps     863.8mV    839mV      953.1mV
195ps     859.6mV    838.7mV    1.081V
262ps     1.029V     828.4mV    1.149V
280ps     1.052V     853.7mV    1.153V
328ps     1.083V     980.5mV    1.16V
377ps     1.092V     1.033V     1.166V
487ps     1.098V     1.057V     1.17V
3ns       1.1V       1.06V      1.17V
[Rising Waveform]
R_fixture= 50.000
V_fixture= 0.0
V_fixture_min= 0.0
V_fixture_max= 0.0
|time   V(typ)   V(min)   V(max)
0s        4.355uV    15.89uV    1.03uV
150ps     -154uV     63.63uV    8.025mV
202ps     2.846mV    -138.3uV   384.9mV
223ps     37.41mV    -253.3uV   430.6mV
260ps     294.4mV    348.6uV    453.1mV
299ps     386mV      27.53mV    386mV
367ps     404.1mV    327.9mV    365.4mV
481ps     343mV      374.4mV    365.2mV
565ps     343.2mV    329.9mV    365.2mV
3ns       343.2mV    331.4mV    365.2mV
[Falling Waveform]
R_fixture= 50.000
V_fixture= 1.100
V_fixture_min= 1.060
V_fixture_max= 1.170
|time   V(typ)   V(min)   V(max)
0s        1.1V       1.06V      1.17V
155ps     1.1V       1.06V      1.167V
221ps     1.093V     1.06V      934.5mV
272ps     940mV      1.058V     851mV
315ps     848.1mV    1.041V     896.9mV
362ps     802.8mV    938mV      919.8mV
417ps     836.1mV    840.8mV    928.4mV
497ps     859.6mV    790.9mV    931.5mV
702ps     864.3mV    837.6mV    932.1mV
3ns       864.4mV    838.5mV    932.1mV
[Falling Waveform]
R_fixture= 50.000
V_fixture= 0.0
V_fixture_min= 0.0
V_fixture_max= 0.0
|time   V(typ)   V(min)   V(max)
0s        343.2mV    331.4mV    365.2mV
143ps     342.4mV    330.9mV    376.1mV
155ps     344.6mV    330.6mV    340.2mV
196ps     358.4mV    331.2mV    99.72mV
211ps     320.3mV    335mV      60.97mV
260ps     84mV       350.5mV    11.83mV
291ps     31.84mV    254.1mV    1.909mV
353ps     4.595mV    52.37mV    186.6uV
448ps     -327.6uV   3.338mV    11.95uV
3ns       4.156uV    15.84uV    1.007uV
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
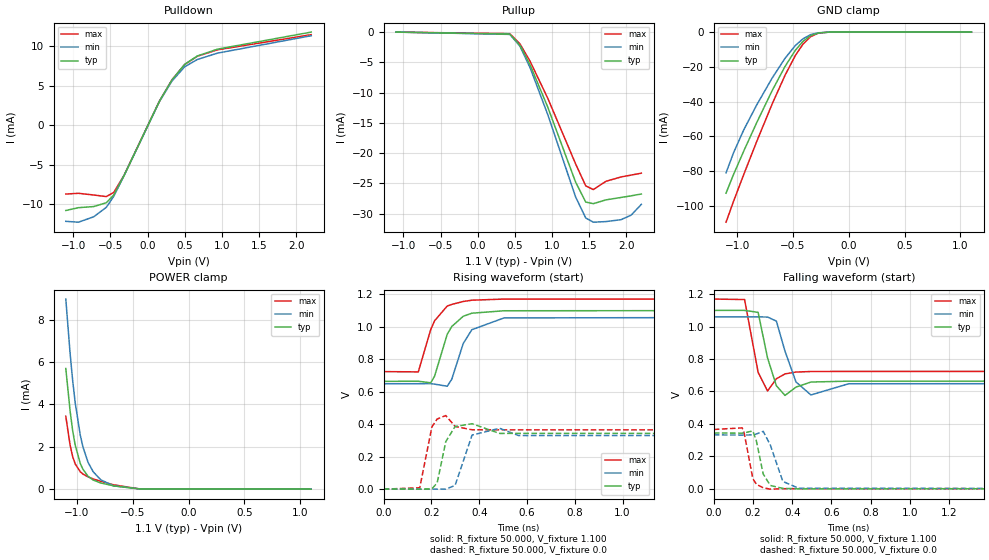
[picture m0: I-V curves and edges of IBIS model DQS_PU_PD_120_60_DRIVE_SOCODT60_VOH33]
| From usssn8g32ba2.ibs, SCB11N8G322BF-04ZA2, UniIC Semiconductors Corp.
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|   Model DQS_PU_PD_120_60_DRIVE_SOCODT60_VOH33
[Model] DQS_PU_PD_120_60_DRIVE_SOCODT60_VOH33
Model_type I/O
Polarity   Inverting
Vinl =  98.000mV
Vinh =  0.268V
Vmeas =  0.183V
Rref =  50.000
Vref =  0.183V
C_comp   1.020pF   1.010pF   1.030pF
[Model Spec]
Vinh   0.268V   0.262V   0.280V
Vinl   98.000mV   92.000mV   0.110V
Vmeas   0.183V   0.177V   0.195V
Vref   0.183V   0.177V   0.195V
Rref   50.000   NA   NA
[Temperature Range]   25.000   0.105k   -40.000
[Voltage Range]   1.100V   1.060V   1.170V
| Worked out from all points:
|   slope of the pulldown table from 0 to 0.165 V, typ, clamps not added: 52.7 ohm
|   GND clamp passes 1 mA (typ) near -0.30 V on its own axis
|   POWER clamp passes 1 mA (typ) near -0.95 V on its own axis
|   rising waveform, R_fixture 50.000, V_fixture 1.100: 20-80 % time 67.4ps typ, 69.7ps min, 65.7ps max; typ from 0.663 V to 1.1 V
|   rising waveform, R_fixture 50.000, V_fixture 0.0: 20-80 % time 27.7ps typ, 36.2ps min, 22.6ps max; typ from 0 V to 0.343 V
|   falling waveform, R_fixture 50.000, V_fixture 1.100: 20-80 % time 42.8ps typ, 56.4ps min, 34.1ps max; typ from 1.1 V to 0.663 V
|   falling waveform, R_fixture 50.000, V_fixture 0.0: 20-80 % time 37.8ps typ, 52.4ps min, 33.2ps max; typ from 0.343 V to 0 V
[Pulldown]
|Voltage   I(typ)   I(min)   I(max)
-1.1V     -10.83mA   -12.2mA    -8.746mA
-930mV    -10.47mA   -12.31mA   -8.649mA
-726mV    -10.33mA   -11.63mA   -8.863mA
-556mV    -9.849mA   -10.43mA   -9.063mA
-454mV    -8.849mA   -9.016mA   -8.534mA
-318mV    -6.436mA   -6.433mA   -6.383mA
158mV     3.005mA    2.954mA    3.019mA
328mV     5.729mA    5.586mA    5.734mA
498mV     7.686mA    7.379mA    7.672mA
668mV     8.751mA    8.306mA    8.715mA
940mV     9.618mA    9.116mA    9.532mA
2.2V      11.78mA    11.32mA    11.45mA
[Pullup]
|Voltage   I(typ)   I(min)   I(max)
-1.1V     2.106nA    21.95nA    0A
432mV     -337.7uA   -381.6uA   -263.6uA
568mV     -2.186mA   -2.341mA   -1.952mA
704mV     -5.417mA   -5.891mA   -4.827mA
942mV     -12.42mA   -13.65mA   -10.95mA
1.316V    -24.8mA    -27.25mA   -21.78mA
1.452V    -28.09mA   -30.72mA   -25.42mA
1.554V    -28.36mA   -31.42mA   -26.03mA
1.724V    -27.73mA   -31.32mA   -24.66mA
1.928V    -27.33mA   -31mA      -23.94mA
2.064V    -27.06mA   -30.24mA   -23.63mA
2.2V      -26.76mA   -28.47mA   -23.32mA
[GND_clamp]
|Voltage   I(typ)   I(min)   I(max)
-1.1V     -92.78mA   -81.05mA   -109.5mA
-1.031V   -81.73mA   -69.22mA   -97.17mA
-939mV    -68.18mA   -56.02mA   -81.64mA
-824mV    -52mA      -41.83mA   -62.83mA
-686mV    -33.62mA   -26.41mA   -41.32mA
-571mV    -19.76mA   -15.06mA   -24.85mA
-479mV    -10.5mA    -7.76mA    -13.5mA
-410mV    -5.313mA   -3.84mA    -6.916mA
-341mV    -2.007mA   -1.45mA    -2.59mA
-272mV    -506.9uA   -403.5uA   -609.8uA
-180mV    -45.65uA   -51.35uA   -43.55uA
1.1V      0A         0A         0A
[POWER_clamp]
|Voltage   I(typ)   I(min)   I(max)
-1.1V     5.691mA    8.967mA    3.44mA
-1.062V   3.709mA    6.444mA    2.092mA
-1.039V   2.781mA    5.152mA    1.546mA
-1.016V   2.086mA    4.085mA    1.193mA
-970mV    1.21mA     2.539mA    818.5uA
-947mV    943.7uA    2.005mA    716.7uA
-901mV    610.1uA    1.27mA     581.3uA
-855mV    430.7uA    824.1uA    484.6uA
-786mV    289.9uA    439.4uA    366uA
-671mV    155.9uA    155.9uA    203.6uA
-441mV    13.2uA     12.79uA    15.03uA
1.1V      0A         0A         0A
[Ramp]
| variable   typ   min   max
dV/dt_r   0.206/27.799p   0.199/36.282p   0.219/22.685p
dV/dt_f   0.262/42.819p   0.247/56.495p   0.268/34.109p
R_load = 50.000
[Rising Waveform]
R_fixture= 50.000
V_fixture= 1.100
V_fixture_min= 1.060
V_fixture_max= 1.170
|time   V(typ)   V(min)   V(max)
0s        663.5mV    648.6mV    723.5mV
145ps     664.4mV    649.1mV    721.8mV
197ps     654.4mV    649.5mV    982.1mV
213ps     694.8mV    646.4mV    1.036V
266ps     952.8mV    633.5mV    1.127V
285ps     1.001V     676.2mV    1.137V
333ps     1.064V     896.2mV    1.155V
369ps     1.083V     981.4mV    1.163V
504ps     1.098V     1.054V     1.17V
3ns       1.1V       1.06V      1.17V
[Rising Waveform]
R_fixture= 50.000
V_fixture= 0.0
V_fixture_min= 0.0
V_fixture_max= 0.0
|time   V(typ)   V(min)   V(max)
0s        3.261uV    11.92uV    770.5nV
151ps     -66.82uV   44.87uV    8.489mV
202ps     2.074mV    -26.85uV   383.3mV
224ps     38.23mV    27.15uV    431.6mV
260ps     292.5mV    460.4uV    453.2mV
299ps     385.7mV    22.86mV    386mV
370ps     402.7mV    332.7mV    365.4mV
485ps     343mV      374.8mV    365.2mV
565ps     343.2mV    329.8mV    365.2mV
3ns       343.2mV    331.4mV    365.2mV
[Falling Waveform]
R_fixture= 50.000
V_fixture= 1.100
V_fixture_min= 1.060
V_fixture_max= 1.170
|time   V(typ)   V(min)   V(max)
0s        1.1V       1.06V      1.17V
157ps     1.1V       1.06V      1.167V
226ps     1.088V     1.06V      717.9mV
274ps     806.8mV    1.059V     602.6mV
319ps     635.2mV    1.034V     678.1mV
363ps     575.3mV    848.4mV    708.1mV
419ps     626.7mV    658.4mV    719.5mV
495ps     657.9mV    578.2mV    722.9mV
688ps     663.4mV    647.4mV    723.5mV
3ns       663.5mV    648.6mV    723.5mV
[Falling Waveform]
R_fixture= 50.000
V_fixture= 0.0
V_fixture_min= 0.0
V_fixture_max= 0.0
|time   V(typ)   V(min)   V(max)
0s        343.2mV    331.4mV    365.2mV
145ps     342.6mV    330.8mV    375mV
155ps     344.5mV    330.6mV    343mV
199ps     355.9mV    331.7mV    62.15mV
217ps     295.1mV    337.1mV    26.83mV
252ps     90.25mV    353.4mV    5.421mV
288ps     19.63mV    269.9mV    -3.24mV
352ps     1.403mV    44.32mV    -435uV
433ps     -1.291mV   2.162mV    -11.34uV
3ns       -306.2nV   11.85uV    515.9nV
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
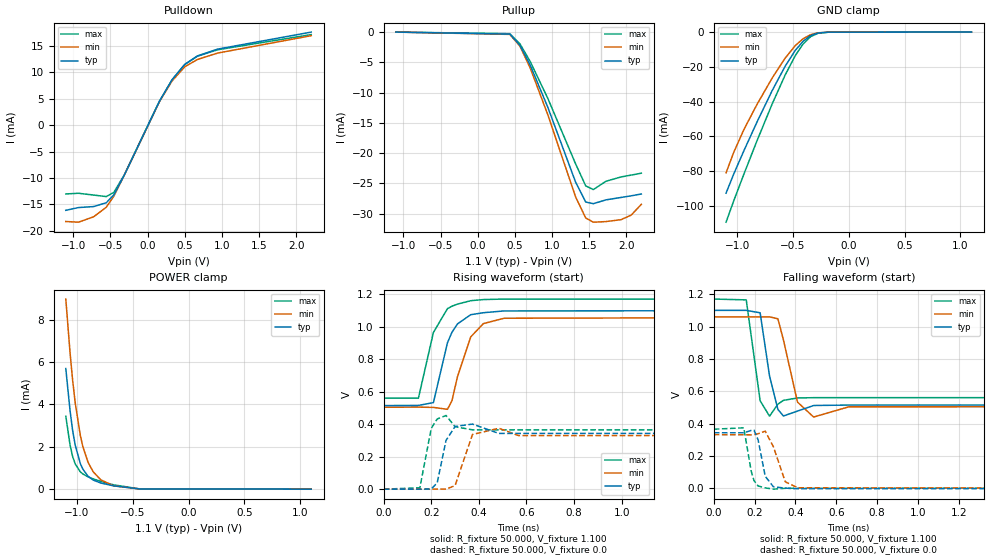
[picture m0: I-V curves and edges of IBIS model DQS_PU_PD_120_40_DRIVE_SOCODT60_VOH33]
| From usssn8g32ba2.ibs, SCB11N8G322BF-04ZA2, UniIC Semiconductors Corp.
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|   Model DQS_PU_PD_120_40_DRIVE_SOCODT60_VOH33
[Model] DQS_PU_PD_120_40_DRIVE_SOCODT60_VOH33
Model_type I/O
Polarity   Inverting
Vinl =  98.000mV
Vinh =  0.268V
Vmeas =  0.183V
Rref =  50.000
Vref =  0.183V
C_comp   1.020pF   1.010pF   1.030pF
[Model Spec]
Vinh   0.268V   0.262V   0.280V
Vinl   98.000mV   92.000mV   0.110V
Vmeas   0.183V   0.177V   0.195V
Vref   0.183V   0.177V   0.195V
Rref   50.000   NA   NA
[Temperature Range]   25.000   0.105k   -40.000
[Voltage Range]   1.100V   1.060V   1.170V
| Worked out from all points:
|   slope of the pulldown table from 0 to 0.165 V, typ, clamps not added: 35.3 ohm
|   GND clamp passes 1 mA (typ) near -0.30 V on its own axis
|   POWER clamp passes 1 mA (typ) near -0.95 V on its own axis
|   rising waveform, R_fixture 50.000, V_fixture 1.100: 20-80 % time 68.6ps typ, 71.8ps min, 66.6ps max; typ from 0.514 V to 1.1 V
|   rising waveform, R_fixture 50.000, V_fixture 0.0: 20-80 % time 27.4ps typ, 35.8ps min, 22.4ps max; typ from 0 V to 0.343 V
|   falling waveform, R_fixture 50.000, V_fixture 1.100: 20-80 % time 39.5ps typ, 52.5ps min, 32.2ps max; typ from 1.1 V to 0.514 V
|   falling waveform, R_fixture 50.000, V_fixture 0.0: 20-80 % time 32ps typ, 49.2ps min, 27.1ps max; typ from 0.343 V to 0 V
[Pulldown]
|Voltage   I(typ)   I(min)   I(max)
-1.1V     -16.13mA   -18.25mA   -13.03mA
-930mV    -15.61mA   -18.38mA   -12.9mA
-726mV    -15.42mA   -17.36mA   -13.24mA
-556mV    -14.7mA    -15.55mA   -13.53mA
-454mV    -13.2mA    -13.45mA   -12.73mA
-318mV    -9.609mA   -9.606mA   -9.529mA
158mV     4.492mA    4.415mA    4.512mA
328mV     8.568mA    8.352mA    8.576mA
498mV     11.5mA     11.04mA    11.48mA
668mV     13.1mA     12.43mA    13.05mA
940mV     14.4mA     13.65mA    14.28mA
2.2V      17.63mA    16.95mA    17.16mA
[Pullup]
|Voltage   I(typ)   I(min)   I(max)
-1.1V     2.106nA    21.95nA    0A
432mV     -337.7uA   -381.6uA   -263.6uA
568mV     -2.186mA   -2.341mA   -1.952mA
704mV     -5.417mA   -5.891mA   -4.827mA
942mV     -12.42mA   -13.65mA   -10.95mA
1.316V    -24.8mA    -27.25mA   -21.78mA
1.452V    -28.09mA   -30.72mA   -25.42mA
1.554V    -28.36mA   -31.42mA   -26.03mA
1.724V    -27.73mA   -31.32mA   -24.66mA
1.928V    -27.33mA   -31mA      -23.94mA
2.064V    -27.06mA   -30.24mA   -23.63mA
2.2V      -26.76mA   -28.47mA   -23.32mA
[GND_clamp]
|Voltage   I(typ)   I(min)   I(max)
-1.1V     -92.78mA   -81.05mA   -109.5mA
-1.031V   -81.73mA   -69.22mA   -97.17mA
-939mV    -68.18mA   -56.02mA   -81.64mA
-824mV    -52mA      -41.83mA   -62.83mA
-686mV    -33.62mA   -26.41mA   -41.32mA
-571mV    -19.76mA   -15.06mA   -24.85mA
-479mV    -10.5mA    -7.76mA    -13.5mA
-410mV    -5.313mA   -3.84mA    -6.916mA
-341mV    -2.007mA   -1.45mA    -2.59mA
-272mV    -506.9uA   -403.5uA   -609.8uA
-180mV    -45.65uA   -51.35uA   -43.55uA
1.1V      0A         0A         0A
[POWER_clamp]
|Voltage   I(typ)   I(min)   I(max)
-1.1V     5.691mA    8.967mA    3.44mA
-1.062V   3.709mA    6.444mA    2.092mA
-1.039V   2.781mA    5.152mA    1.546mA
-1.016V   2.086mA    4.085mA    1.193mA
-970mV    1.21mA     2.539mA    818.5uA
-947mV    943.7uA    2.005mA    716.7uA
-901mV    610.1uA    1.27mA     581.3uA
-855mV    430.7uA    824.1uA    484.6uA
-786mV    289.9uA    439.4uA    366uA
-671mV    155.9uA    155.9uA    203.6uA
-441mV    13.2uA     12.79uA    15.03uA
1.1V      0A         0A         0A
[Ramp]
| variable   typ   min   max
dV/dt_r   0.206/27.590p   0.199/35.878p   0.219/22.619p
dV/dt_f   0.351/39.588p   0.333/52.560p   0.366/32.212p
R_load = 50.000
[Rising Waveform]
R_fixture= 50.000
V_fixture= 1.100
V_fixture_min= 1.060
V_fixture_max= 1.170
|time   V(typ)   V(min)   V(max)
0s        514.4mV    504.3mV    560.3mV
146ps     515.4mV    504.9mV    560.2mV
209ps     532.6mV    503.2mV    964.4mV
268ps     900.9mV    491.4mV    1.111V
287ps     965.8mV    544.8mV    1.126V
310ps     1.017V     691.8mV    1.139V
366ps     1.074V     937.6mV    1.16V
419ps     1.086V     1.019V     1.167V
506ps     1.097V     1.052V     1.17V
3ns       1.1V       1.06V      1.17V
[Rising Waveform]
R_fixture= 50.000
V_fixture= 0.0
V_fixture_min= 0.0
V_fixture_max= 0.0
|time   V(typ)   V(min)   V(max)
0s        2.608uV    9.547uV    615.8nV
152ps     89.05uV    40.28uV    8.349mV
200ps     795.4uV    94.94uV    374.1mV
225ps     39.29mV    293.5uV    432.2mV
262ps     299.7mV    299.2uV    453.4mV
300ps     386.2mV    21.84mV    384.4mV
373ps     400.5mV    336.4mV    365.3mV
484ps     343mV      374.8mV    365.2mV
567ps     343.2mV    329.7mV    365.2mV
3ns       343.2mV    331.4mV    365.2mV
[Falling Waveform]
R_fixture= 50.000
V_fixture= 1.100
V_fixture_min= 1.060
V_fixture_max= 1.170
|time   V(typ)   V(min)   V(max)
0s        1.1V       1.06V      1.17V
159ps     1.1V       1.06V      1.165V
227ps     1.085V     1.06V      541.4mV
273ps     694.6mV    1.06V      445.7mV
314ps     487.4mV    1.048V     520mV
341ps     446.9mV    917.9mV    543.6mV
410ps     477.2mV    532.6mV    558.3mV
489ps     511.7mV    440.3mV    560.1mV
661ps     514.4mV    503.5mV    560.3mV
3ns       514.4mV    504.3mV    560.3mV
[Falling Waveform]
R_fixture= 50.000
V_fixture= 0.0
V_fixture_min= 0.0
V_fixture_max= 0.0
|time   V(typ)   V(min)   V(max)
0s        343.2mV    331.4mV    365.2mV
147ps     342.7mV    330.8mV    373.6mV
183ps     357.5mV    330.2mV    106.8mV
197ps     359.4mV    331.3mV    46.75mV
217ps     299.4mV    336.9mV    14.04mV
252ps     73.97mV    353.3mV    2.068mV
292ps     8.782mV    256.1mV    -5.781mV
350ps     712.5uV    39.72mV    -439.6uV
412ps     -3.608mV   2.58mV     -10.55uV
3ns       2.384uV    9.446uV    119.5nV
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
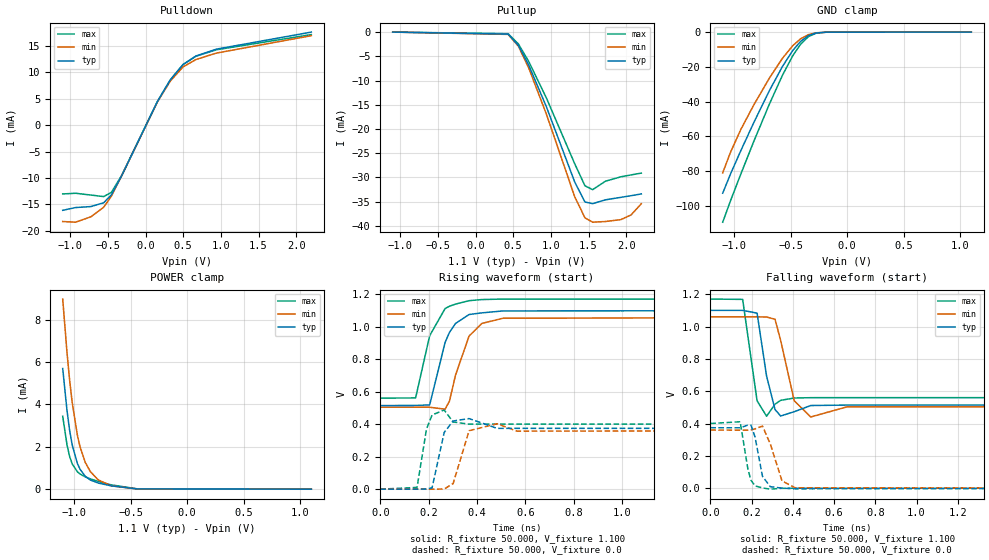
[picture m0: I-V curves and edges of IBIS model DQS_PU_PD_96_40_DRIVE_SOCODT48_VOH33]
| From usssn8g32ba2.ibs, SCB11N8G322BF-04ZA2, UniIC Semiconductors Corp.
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|   Model DQS_PU_PD_96_40_DRIVE_SOCODT48_VOH33
[Model] DQS_PU_PD_96_40_DRIVE_SOCODT48_VOH33
Model_type I/O
Polarity   Inverting
Vinl =  98.000mV
Vinh =  0.268V
Vmeas =  0.183V
Rref =  50.000
Vref =  0.183V
C_comp   1.020pF   1.010pF   1.030pF
[Model Spec]
Vinh   0.268V   0.262V   0.280V
Vinl   98.000mV   92.000mV   0.110V
Vmeas   0.183V   0.177V   0.195V
Vref   0.183V   0.177V   0.195V
Rref   50.000   NA   NA
[Temperature Range]   25.000   0.105k   -40.000
[Voltage Range]   1.100V   1.060V   1.170V
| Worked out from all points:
|   slope of the pulldown table from 0 to 0.165 V, typ, clamps not added: 35.3 ohm
|   GND clamp passes 1 mA (typ) near -0.30 V on its own axis
|   POWER clamp passes 1 mA (typ) near -0.95 V on its own axis
|   rising waveform, R_fixture 50.000, V_fixture 1.100: 20-80 % time 68.4ps typ, 71.3ps min, 66.4ps max; typ from 0.514 V to 1.1 V
|   rising waveform, R_fixture 50.000, V_fixture 0.0: 20-80 % time 26.5ps typ, 34.9ps min, 21.5ps max; typ from 0 V to 0.374 V
|   falling waveform, R_fixture 50.000, V_fixture 1.100: 20-80 % time 39.6ps typ, 52.7ps min, 32.2ps max; typ from 1.1 V to 0.514 V
|   falling waveform, R_fixture 50.000, V_fixture 0.0: 20-80 % time 32.7ps typ, 50.1ps min, 27.4ps max; typ from 0.374 V to 0 V
[Pulldown]
|Voltage   I(typ)   I(min)   I(max)
-1.1V     -16.13mA   -18.25mA   -13.03mA
-930mV    -15.61mA   -18.38mA   -12.9mA
-726mV    -15.42mA   -17.36mA   -13.24mA
-556mV    -14.7mA    -15.55mA   -13.53mA
-454mV    -13.2mA    -13.45mA   -12.73mA
-318mV    -9.609mA   -9.606mA   -9.529mA
158mV     4.492mA    4.415mA    4.512mA
328mV     8.568mA    8.352mA    8.576mA
498mV     11.5mA     11.04mA    11.48mA
668mV     13.1mA     12.43mA    13.05mA
940mV     14.4mA     13.65mA    14.28mA
2.2V      17.63mA    16.95mA    17.16mA
[Pullup]
|Voltage   I(typ)   I(min)   I(max)
-1.1V     2.6nA      27.46nA    0A
432mV     -421.9uA   -476.8uA   -329.3uA
568mV     -2.729mA   -2.923mA   -2.437mA
704mV     -6.762mA   -7.352mA   -6.026mA
942mV     -15.5mA    -17.03mA   -13.67mA
1.316V    -30.95mA   -34mA      -27.19mA
1.452V    -35.08mA   -38.36mA   -31.74mA
1.554V    -35.42mA   -39.25mA   -32.53mA
1.724V    -34.63mA   -39.11mA   -30.79mA
1.928V    -34.12mA   -38.72mA   -29.88mA
2.064V    -33.78mA   -37.75mA   -29.49mA
2.2V      -33.41mA   -35.44mA   -29.11mA
[GND_clamp]
|Voltage   I(typ)   I(min)   I(max)
-1.1V     -92.78mA   -81.05mA   -109.5mA
-1.031V   -81.73mA   -69.22mA   -97.17mA
-939mV    -68.18mA   -56.02mA   -81.64mA
-824mV    -52mA      -41.83mA   -62.83mA
-686mV    -33.62mA   -26.41mA   -41.32mA
-571mV    -19.76mA   -15.06mA   -24.85mA
-479mV    -10.5mA    -7.76mA    -13.5mA
-410mV    -5.313mA   -3.84mA    -6.916mA
-341mV    -2.007mA   -1.45mA    -2.59mA
-272mV    -506.9uA   -403.5uA   -609.8uA
-180mV    -45.65uA   -51.35uA   -43.55uA
1.1V      0A         0A         0A
[POWER_clamp]
|Voltage   I(typ)   I(min)   I(max)
-1.1V     5.691mA    8.967mA    3.44mA
-1.062V   3.709mA    6.444mA    2.092mA
-1.039V   2.781mA    5.152mA    1.546mA
-1.016V   2.086mA    4.085mA    1.193mA
-970mV    1.21mA     2.539mA    818.5uA
-947mV    943.7uA    2.005mA    716.7uA
-901mV    610.1uA    1.27mA     581.3uA
-855mV    430.7uA    824.1uA    484.6uA
-786mV    289.9uA    439.4uA    366uA
-671mV    155.9uA    155.9uA    203.6uA
-441mV    13.2uA     12.79uA    15.03uA
1.1V      0A         0A         0A
[Ramp]
| variable   typ   min   max
dV/dt_r   0.225/26.612p   0.216/35.011p   0.240/21.722p
dV/dt_f   0.351/39.753p   0.333/52.848p   0.366/32.298p
R_load = 50.000
[Rising Waveform]
R_fixture= 50.000
V_fixture= 1.100
V_fixture_min= 1.060
V_fixture_max= 1.170
|time   V(typ)   V(min)   V(max)
0s        514.4mV    504.3mV    560.3mV
146ps     515.3mV    504.9mV    561.5mV
204ps     518.6mV    504.2mV    944.2mV
268ps     903.8mV    492.3mV    1.112V
286ps     965.1mV    542.3mV    1.126V
311ps     1.02V      702.6mV    1.139V
367ps     1.075V     942.7mV    1.16V
420ps     1.085V     1.02V      1.167V
507ps     1.097V     1.052V     1.17V
3ns       1.1V       1.06V      1.17V
[Rising Waveform]
R_fixture= 50.000
V_fixture= 0.0
V_fixture_min= 0.0
V_fixture_max= 0.0
|time   V(typ)   V(min)   V(max)
0s        2.608uV    9.547uV    615.8nV
152ps     6.767uV    48.98uV    10.81mV
191ps     849.3uV    23.63uV    370.4mV
214ps     8.08mV     121.2uV    456.6mV
264ps     348.9mV    895.7uV    487.2mV
301ps     419.5mV    34.26mV    413.5mV
367ps     434.4mV    359.8mV    400.2mV
483ps     374.1mV    402.5mV    400.4mV
565ps     374.4mV    357.3mV    400.4mV
3ns       374.4mV    360.1mV    400.4mV
[Falling Waveform]
R_fixture= 50.000
V_fixture= 1.100
V_fixture_min= 1.060
V_fixture_max= 1.170
|time   V(typ)   V(min)   V(max)
0s        1.1V       1.06V      1.17V
157ps     1.1V       1.06V      1.168V
227ps     1.083V     1.06V      540.7mV
273ps     693.3mV    1.059V     445.6mV
314ps     487.2mV    1.045V     520.1mV
341ps     446.7mV    915.6mV    543.6mV
407ps     473.4mV    541.2mV    558.1mV
487ps     511.6mV    440.8mV    560.1mV
663ps     514.4mV    503.5mV    560.3mV
3ns       514.4mV    504.3mV    560.3mV
[Falling Waveform]
R_fixture= 50.000
V_fixture= 0.0
V_fixture_min= 0.0
V_fixture_max= 0.0
|time   V(typ)   V(min)   V(max)
0s        374.4mV    360.1mV    400.4mV
145ps     373.7mV    359.4mV    411.2mV
182ps     390.7mV    358.8mV    121.3mV
197ps     390.7mV    360.3mV    49.73mV
217ps     317.7mV    367mV      14.87mV
253ps     74.02mV    384.6mV    2.055mV
291ps     9.709mV    274.1mV    -5.651mV
348ps     774.7uV    44.99mV    -473.8uV
412ps     -3.608mV   2.684mV    -12.55uV
3ns       2.377uV    9.426uV    315.8nV
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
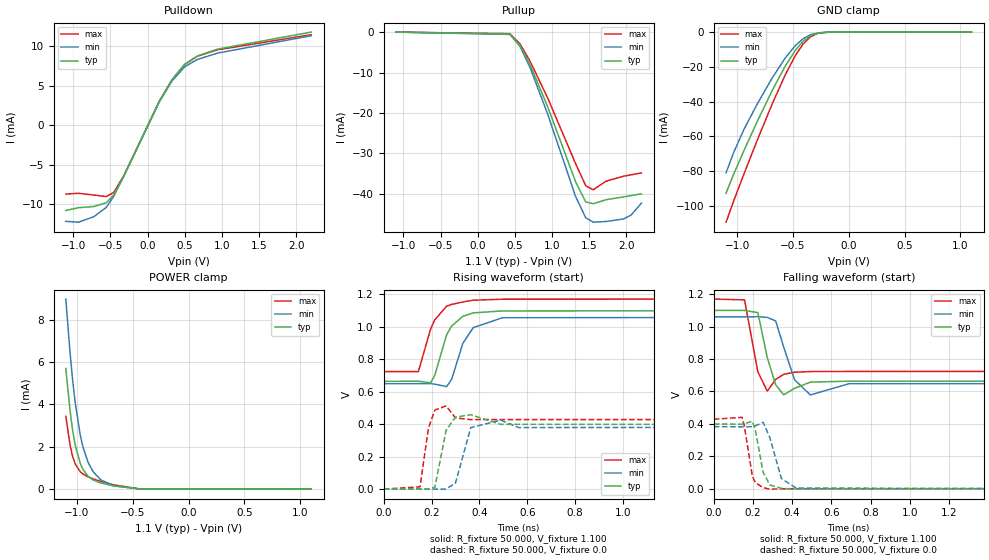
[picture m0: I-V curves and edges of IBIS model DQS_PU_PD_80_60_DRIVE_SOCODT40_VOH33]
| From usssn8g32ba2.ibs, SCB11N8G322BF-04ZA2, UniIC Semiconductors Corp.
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|   Model DQS_PU_PD_80_60_DRIVE_SOCODT40_VOH33
[Model] DQS_PU_PD_80_60_DRIVE_SOCODT40_VOH33
Model_type I/O
Polarity   Inverting
Vinl =  98.000mV
Vinh =  0.268V
Vmeas =  0.183V
Rref =  50.000
Vref =  0.183V
C_comp   1.020pF   1.010pF   1.030pF
[Model Spec]
Vinh   0.268V   0.262V   0.280V
Vinl   98.000mV   92.000mV   0.110V
Vmeas   0.183V   0.177V   0.195V
Vref   0.183V   0.177V   0.195V
Rref   50.000   NA   NA
[Temperature Range]   25.000   0.105k   -40.000
[Voltage Range]   1.100V   1.060V   1.170V
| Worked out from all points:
|   slope of the pulldown table from 0 to 0.165 V, typ, clamps not added: 52.7 ohm
|   GND clamp passes 1 mA (typ) near -0.30 V on its own axis
|   POWER clamp passes 1 mA (typ) near -0.95 V on its own axis
|   rising waveform, R_fixture 50.000, V_fixture 1.100: 20-80 % time 66.3ps typ, 67.6ps min, 65.2ps max; typ from 0.663 V to 1.1 V
|   rising waveform, R_fixture 50.000, V_fixture 0.0: 20-80 % time 25.8ps typ, 34.3ps min, 20.8ps max; typ from 0 V to 0.399 V
|   falling waveform, R_fixture 50.000, V_fixture 1.100: 20-80 % time 43.2ps typ, 57.3ps min, 34.2ps max; typ from 1.1 V to 0.663 V
|   falling waveform, R_fixture 50.000, V_fixture 0.0: 20-80 % time 38.1ps typ, 52.1ps min, 33.4ps max; typ from 0.399 V to 0 V
[Pulldown]
|Voltage   I(typ)   I(min)   I(max)
-1.1V     -10.83mA   -12.2mA    -8.746mA
-930mV    -10.47mA   -12.31mA   -8.649mA
-726mV    -10.33mA   -11.63mA   -8.863mA
-556mV    -9.849mA   -10.43mA   -9.063mA
-454mV    -8.849mA   -9.016mA   -8.534mA
-318mV    -6.436mA   -6.433mA   -6.383mA
158mV     3.005mA    2.954mA    3.019mA
328mV     5.729mA    5.586mA    5.734mA
498mV     7.686mA    7.379mA    7.672mA
668mV     8.751mA    8.306mA    8.715mA
940mV     9.618mA    9.116mA    9.532mA
2.2V      11.78mA    11.32mA    11.45mA
[Pullup]
|Voltage   I(typ)   I(min)   I(max)
-1.1V     3.1nA      32.98nA    0A
432mV     -506.1uA   -571.8uA   -395uA
568mV     -3.269mA   -3.501mA   -2.92mA
704mV     -8.095mA   -8.8mA     -7.217mA
942mV     -18.54mA   -20.37mA   -16.36mA
1.316V    -37.03mA   -40.67mA   -32.54mA
1.452V    -42.01mA   -45.93mA   -38mA
1.554V    -42.45mA   -47.02mA   -39mA
1.724V    -41.47mA   -46.85mA   -36.88mA
1.962V    -40.75mA   -46.21mA   -35.64mA
2.064V    -40.44mA   -45.22mA   -35.29mA
2.2V      -40mA      -42.32mA   -34.84mA
[GND_clamp]
|Voltage   I(typ)   I(min)   I(max)
-1.1V     -92.78mA   -81.05mA   -109.5mA
-1.031V   -81.73mA   -69.22mA   -97.17mA
-939mV    -68.18mA   -56.02mA   -81.64mA
-824mV    -52mA      -41.83mA   -62.83mA
-686mV    -33.62mA   -26.41mA   -41.32mA
-571mV    -19.76mA   -15.06mA   -24.85mA
-479mV    -10.5mA    -7.76mA    -13.5mA
-410mV    -5.313mA   -3.84mA    -6.916mA
-341mV    -2.007mA   -1.45mA    -2.59mA
-272mV    -506.9uA   -403.5uA   -609.8uA
-180mV    -45.65uA   -51.35uA   -43.55uA
1.1V      0A         0A         0A
[POWER_clamp]
|Voltage   I(typ)   I(min)   I(max)
-1.1V     5.691mA    8.967mA    3.44mA
-1.062V   3.709mA    6.444mA    2.092mA
-1.039V   2.781mA    5.152mA    1.546mA
-1.016V   2.086mA    4.085mA    1.193mA
-970mV    1.21mA     2.539mA    818.5uA
-947mV    943.7uA    2.005mA    716.7uA
-901mV    610.1uA    1.27mA     581.3uA
-855mV    430.7uA    824.1uA    484.6uA
-786mV    289.9uA    439.4uA    366uA
-671mV    155.9uA    155.9uA    203.6uA
-441mV    13.2uA     12.79uA    15.03uA
1.1V      0A         0A         0A
[Ramp]
| variable   typ   min   max
dV/dt_r   0.239/26.065p   0.230/34.663p   0.257/21.150p
dV/dt_f   0.262/43.228p   0.247/57.371p   0.268/34.368p
R_load = 50.000
[Rising Waveform]
R_fixture= 50.000
V_fixture= 1.100
V_fixture_min= 1.060
V_fixture_max= 1.170
|time   V(typ)   V(min)   V(max)
0s        663.5mV    648.6mV    723.5mV
145ps     664.4mV    649.2mV    723.7mV
196ps     654.3mV    649.5mV    984.1mV
213ps     698.6mV    646.2mV    1.041V
263ps     949.8mV    631.3mV    1.126V
284ps     1.004V     675.4mV    1.137V
331ps     1.064V     897.7mV    1.152V
374ps     1.085V     993.8mV    1.163V
496ps     1.097V     1.055V     1.169V
3ns       1.1V       1.06V      1.17V
[Rising Waveform]
R_fixture= 50.000
V_fixture= 0.0
V_fixture_min= 0.0
V_fixture_max= 0.0
|time   V(typ)   V(min)   V(max)
0s        3.261uV    11.92uV    770.5nV
152ps     -211.2uV   62.94uV    14.27mV
187ps     295.3uV    3.182uV    375.6mV
214ps     11.8mV     -190.3uV   486.5mV
261ps     362.4mV    817.4uV    512.4mV
300ps     443.2mV    36.51mV    438.3mV
364ps     458.1mV    378.3mV    427.9mV
489ps     398.7mV    424.7mV    428.3mV
564ps     398.9mV    378.9mV    428.3mV
3ns       398.9mV    382.6mV    428.3mV
[Falling Waveform]
R_fixture= 50.000
V_fixture= 1.100
V_fixture_min= 1.060
V_fixture_max= 1.170
|time   V(typ)   V(min)   V(max)
0s        1.1V       1.06V      1.17V
157ps     1.1V       1.06V      1.165V
225ps     1.086V     1.061V     720.9mV
273ps     809.5mV    1.057V     601.8mV
316ps     641.1mV    1.035V     674.4mV
357ps     579.2mV    873.1mV    705.7mV
412ps     619.3mV    672.8mV    718.7mV
493ps     657.6mV    578.4mV    722.8mV
689ps     663.4mV    647.4mV    723.5mV
3ns       663.5mV    648.6mV    723.5mV
[Falling Waveform]
R_fixture= 50.000
V_fixture= 0.0
V_fixture_min= 0.0
V_fixture_max= 0.0
|time   V(typ)   V(min)   V(max)
0s        398.9mV    382.6mV    428.3mV
144ps     398.1mV    381.9mV    440.5mV
155ps     400.9mV    381.5mV    393.7mV
197ps     416.3mV    382.7mV    77.07mV
212ps     363.3mV    387.6mV    38.23mV
252ps     100.4mV    409.8mV    6.07mV
286ps     23.37mV    315.3mV    -2.786mV
345ps     2.047mV    62.78mV    -581.9uV
421ps     -2.013mV   3.494mV    -19.62uV
3ns       1.67uV     11.83uV    -1.494uV
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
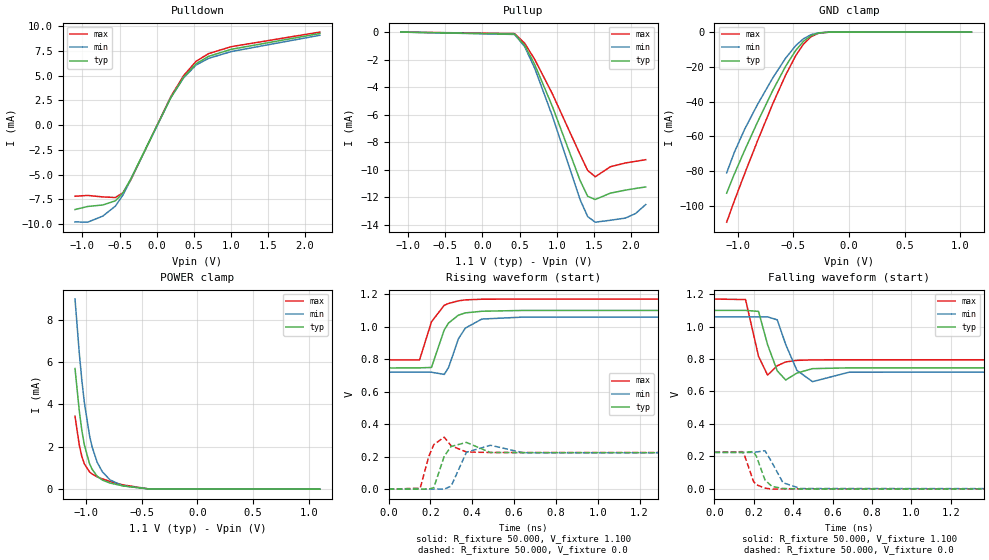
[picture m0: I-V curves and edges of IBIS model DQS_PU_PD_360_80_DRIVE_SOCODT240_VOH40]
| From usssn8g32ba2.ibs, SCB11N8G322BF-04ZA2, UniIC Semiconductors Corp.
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|   Model DQS_PU_PD_360_80_DRIVE_SOCODT240_VOH40
[Model] DQS_PU_PD_360_80_DRIVE_SOCODT240_VOH40
Model_type I/O
Polarity   Inverting
Vinl =  0.135V
Vinh =  0.305V
Vmeas =  0.220V
Rref =  50.000
Vref =  0.220V
C_comp   1.020pF   1.010pF   1.030pF
[Model Spec]
Vinh   0.305V   0.297V   0.319V
Vinl   0.135V   0.127V   0.149V
Vmeas   0.220V   0.212V   0.234V
Vref   0.220V   0.212V   0.234V
Rref   50.000   NA   NA
[Temperature Range]   25.000   0.105k   -40.000
[Voltage Range]   1.100V   1.060V   1.170V
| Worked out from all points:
|   slope of the pulldown table from 0 to 0.165 V, typ, clamps not added: 68.2 ohm
|   GND clamp passes 1 mA (typ) near -0.30 V on its own axis
|   POWER clamp passes 1 mA (typ) near -0.95 V on its own axis
|   rising waveform, R_fixture 50.000, V_fixture 1.100: 20-80 % time 67.7ps typ, 70.6ps min, 66.1ps max; typ from 0.746 V to 1.1 V
|   rising waveform, R_fixture 50.000, V_fixture 0.0: 20-80 % time 30.6ps typ, 39.1ps min, 24.4ps max; typ from 0 V to 0.225 V
|   falling waveform, R_fixture 50.000, V_fixture 1.100: 20-80 % time 44.2ps typ, 56.3ps min, 36ps max; typ from 1.1 V to 0.746 V
|   falling waveform, R_fixture 50.000, V_fixture 0.0: 20-80 % time 42.5ps typ, 56.5ps min, 39.3ps max; typ from 0.225 V to 0 V
[Pulldown]
|Voltage   I(typ)   I(min)   I(max)
-1.1V     -8.531mA   -9.779mA   -7.187mA
-930mV    -8.221mA   -9.809mA   -7.107mA
-726mV    -8.07mA    -9.196mA   -7.255mA
-556mV    -7.649mA   -8.186mA   -7.316mA
-454mV    -6.852mA   -7.06mA    -6.833mA
-352mV    -5.485mA   -5.559mA   -5.593mA
192mV     2.785mA    2.773mA    2.883mA
362mV     4.806mA    4.757mA    4.977mA
532mV     6.204mA    6.068mA    6.444mA
702mV     6.948mA    6.744mA    7.224mA
1.008V    7.659mA    7.43mA     7.924mA
2.2V      9.253mA    9.074mA    9.394mA
[Pullup]
|Voltage   I(typ)   I(min)   I(max)
-1.1V     900pA      9.618nA    0A
432mV     -147.1uA   -170.1uA   -107.3uA
568mV     -948.7uA   -1.043mA   -800.9uA
704mV     -2.351mA   -2.626mA   -1.98mA
942mV     -5.394mA   -6.093mA   -4.481mA
1.316V    -10.78mA   -12.17mA   -8.894mA
1.418V    -11.93mA   -13.4mA    -10.05mA
1.52V     -12.16mA   -13.81mA   -10.51mA
1.724V    -11.7mA    -13.67mA   -9.778mA
1.928V    -11.48mA   -13.51mA   -9.507mA
2.064V    -11.36mA   -13.18mA   -9.389mA
2.2V      -11.25mA   -12.53mA   -9.27mA
[GND_clamp]
|Voltage   I(typ)   I(min)   I(max)
-1.1V     -92.78mA   -81.05mA   -109.5mA
-1.031V   -81.73mA   -69.22mA   -97.17mA
-939mV    -68.18mA   -56.02mA   -81.64mA
-824mV    -52mA      -41.83mA   -62.83mA
-686mV    -33.62mA   -26.41mA   -41.32mA
-571mV    -19.76mA   -15.06mA   -24.85mA
-479mV    -10.5mA    -7.76mA    -13.5mA
-410mV    -5.313mA   -3.84mA    -6.916mA
-341mV    -2.007mA   -1.45mA    -2.59mA
-272mV    -506.9uA   -403.5uA   -609.8uA
-180mV    -45.65uA   -51.35uA   -43.55uA
1.1V      0A         0A         0A
[POWER_clamp]
|Voltage   I(typ)   I(min)   I(max)
-1.1V     5.691mA    8.967mA    3.44mA
-1.062V   3.709mA    6.444mA    2.092mA
-1.039V   2.781mA    5.152mA    1.546mA
-1.016V   2.086mA    4.085mA    1.193mA
-970mV    1.21mA     2.539mA    818.5uA
-947mV    943.7uA    2.005mA    716.7uA
-901mV    610.1uA    1.27mA     581.3uA
-855mV    430.7uA    824.1uA    484.6uA
-786mV    289.9uA    439.4uA    366uA
-671mV    155.9uA    155.9uA    203.6uA
-441mV    13.2uA     12.79uA    15.03uA
1.1V      0A         0A         0A
[Ramp]
| variable   typ   min   max
dV/dt_r   0.135/30.829p   0.134/39.152p   0.135/24.625p
dV/dt_f   0.212/44.377p   0.204/56.407p   0.225/36.122p
R_load = 50.000
[Rising Waveform]
R_fixture= 50.000
V_fixture= 1.100
V_fixture_min= 1.060
V_fixture_max= 1.170
|time   V(typ)   V(min)   V(max)
0s        746mV      720.2mV    795.6mV
148ps     746.6mV    720.7mV    795.6mV
205ps     749.1mV    719.8mV    1.03V
266ps     980.1mV    706.2mV    1.132V
287ps     1.023V     749.3mV    1.143V
334ps     1.071V     925.9mV    1.159V
367ps     1.085V     991.3mV    1.165V
446ps     1.095V     1.047V     1.169V
643ps     1.1V       1.059V     1.17V
3ns       1.1V       1.06V      1.17V
[Rising Waveform]
R_fixture= 50.000
V_fixture= 0.0
V_fixture_min= 0.0
V_fixture_max= 0.0
|time   V(typ)   V(min)   V(max)
0s        3.687uV    13.4uV     860.8nV
151ps     -6.345uV   31.84uV    5.974mV
192ps     689.9uV    26.81uV    201.1mV
216ps     8.884mV    122.5uV    274mV
266ps     202.9mV    574.4uV    320mV
299ps     262.9mV    18.26mV    267.1mV
372ps     287.7mV    227mV      228.9mV
487ps     225.7mV    270.2mV    225.5mV
644ps     224.7mV    224.1mV    225.5mV
3ns       224.7mV    224.1mV    225.5mV
[Falling Waveform]
R_fixture= 50.000
V_fixture= 1.100
V_fixture_min= 1.060
V_fixture_max= 1.170
|time   V(typ)   V(min)   V(max)
0s        1.1V       1.06V      1.17V
158ps     1.1V       1.06V      1.167V
224ps     1.094V     1.06V      816.6mV
270ps     888.7mV    1.06V      701mV
319ps     727.5mV    1.042V     758.9mV
362ps     670.9mV    890mV      782.2mV
419ps     713.7mV    730.1mV    792mV
498ps     740.9mV    660.8mV    795mV
684ps     745.9mV    718.9mV    795.6mV
3ns       746mV      720.2mV    795.6mV
[Falling Waveform]
R_fixture= 50.000
V_fixture= 0.0
V_fixture_min= 0.0
V_fixture_max= 0.0
|time   V(typ)   V(min)   V(max)
0s        224.7mV    224.1mV    225.5mV
142ps     224.3mV    223.8mV    228.9mV
152ps     225.2mV    223.6mV    209.5mV
198ps     229.6mV    224.4mV    46.17mV
214ps     197.5mV    227.1mV    24.64mV
257ps     53.55mV    234.7mV    4.428mV
292ps     14.76mV    162.6mV    -2.269mV
348ps     1.954mV    37.64mV    -416.7uV
437ps     -888.8uV   1.961mV    -12.48uV
3ns       992.1nV    13.35uV    746.8nV
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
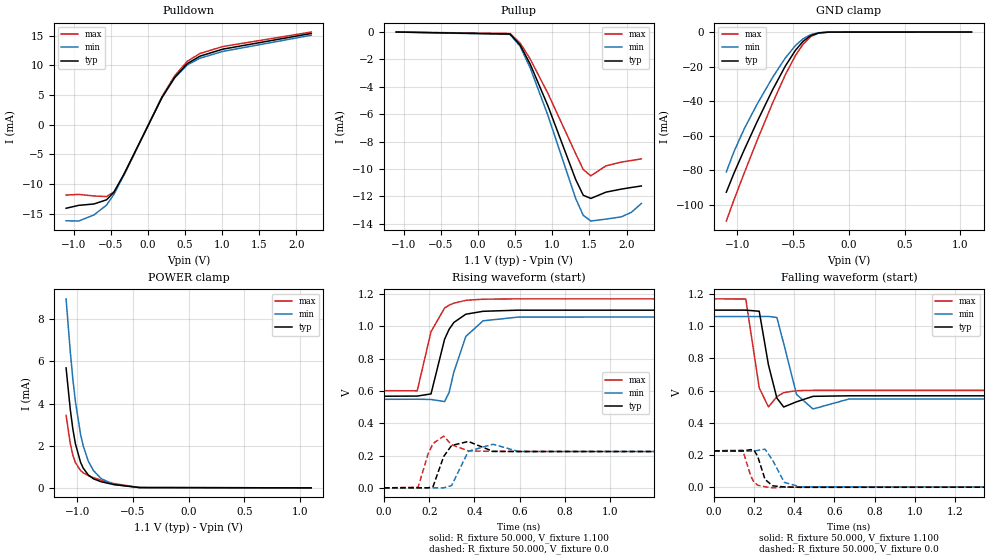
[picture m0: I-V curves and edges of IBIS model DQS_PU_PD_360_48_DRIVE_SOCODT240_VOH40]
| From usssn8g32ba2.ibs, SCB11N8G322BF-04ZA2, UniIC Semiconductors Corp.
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|   Model DQS_PU_PD_360_48_DRIVE_SOCODT240_VOH40
[Model] DQS_PU_PD_360_48_DRIVE_SOCODT240_VOH40
Model_type I/O
Polarity   Inverting
Vinl =  0.135V
Vinh =  0.305V
Vmeas =  0.220V
Rref =  50.000
Vref =  0.220V
C_comp   1.020pF   1.010pF   1.030pF
[Model Spec]
Vinh   0.305V   0.297V   0.319V
Vinl   0.135V   0.127V   0.149V
Vmeas   0.220V   0.212V   0.234V
Vref   0.220V   0.212V   0.234V
Rref   50.000   NA   NA
[Temperature Range]   25.000   0.105k   -40.000
[Voltage Range]   1.100V   1.060V   1.170V
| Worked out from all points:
|   slope of the pulldown table from 0 to 0.165 V, typ, clamps not added: 41 ohm
|   GND clamp passes 1 mA (typ) near -0.30 V on its own axis
|   POWER clamp passes 1 mA (typ) near -0.95 V on its own axis
|   rising waveform, R_fixture 50.000, V_fixture 1.100: 20-80 % time 68.8ps typ, 72.2ps min, 66.9ps max; typ from 0.567 V to 1.1 V
|   rising waveform, R_fixture 50.000, V_fixture 0.0: 20-80 % time 30.5ps typ, 38.7ps min, 24.4ps max; typ from 0 V to 0.225 V
|   falling waveform, R_fixture 50.000, V_fixture 1.100: 20-80 % time 41.5ps typ, 53.1ps min, 34.1ps max; typ from 1.1 V to 0.567 V
|   falling waveform, R_fixture 50.000, V_fixture 0.0: 20-80 % time 34.7ps typ, 52.5ps min, 31.2ps max; typ from 0.225 V to 0 V
[Pulldown]
|Voltage   I(typ)   I(min)   I(max)
-1.1V     -14.07mA   -16.18mA   -11.85mA
-930mV    -13.58mA   -16.22mA   -11.73mA
-726mV    -13.35mA   -15.21mA   -12mA
-556mV    -12.65mA   -13.54mA   -12.1mA
-454mV    -11.34mA   -11.69mA   -11.29mA
-318mV    -8.242mA   -8.339mA   -8.422mA
192mV     4.628mA    4.609mA    4.791mA
362mV     7.992mA    7.909mA    8.275mA
532mV     10.32mA    10.1mA     10.72mA
702mV     11.57mA    11.22mA    12.02mA
1.008V    12.75mA    12.37mA    13.19mA
2.2V      15.4mA     15.1mA     15.64mA
[Pullup]
|Voltage   I(typ)   I(min)   I(max)
-1.1V     900pA      9.618nA    0A
432mV     -147.1uA   -170.1uA   -107.3uA
568mV     -948.7uA   -1.043mA   -800.9uA
704mV     -2.351mA   -2.626mA   -1.98mA
942mV     -5.394mA   -6.093mA   -4.481mA
1.316V    -10.78mA   -12.17mA   -8.894mA
1.418V    -11.93mA   -13.4mA    -10.05mA
1.52V     -12.16mA   -13.81mA   -10.51mA
1.724V    -11.7mA    -13.67mA   -9.778mA
1.928V    -11.48mA   -13.51mA   -9.507mA
2.064V    -11.36mA   -13.18mA   -9.389mA
2.2V      -11.25mA   -12.53mA   -9.27mA
[GND_clamp]
|Voltage   I(typ)   I(min)   I(max)
-1.1V     -92.78mA   -81.05mA   -109.5mA
-1.031V   -81.73mA   -69.22mA   -97.17mA
-939mV    -68.18mA   -56.02mA   -81.64mA
-824mV    -52mA      -41.83mA   -62.83mA
-686mV    -33.62mA   -26.41mA   -41.32mA
-571mV    -19.76mA   -15.06mA   -24.85mA
-479mV    -10.5mA    -7.76mA    -13.5mA
-410mV    -5.313mA   -3.84mA    -6.916mA
-341mV    -2.007mA   -1.45mA    -2.59mA
-272mV    -506.9uA   -403.5uA   -609.8uA
-180mV    -45.65uA   -51.35uA   -43.55uA
1.1V      0A         0A         0A
[POWER_clamp]
|Voltage   I(typ)   I(min)   I(max)
-1.1V     5.691mA    8.967mA    3.44mA
-1.062V   3.709mA    6.444mA    2.092mA
-1.039V   2.781mA    5.152mA    1.546mA
-1.016V   2.086mA    4.085mA    1.193mA
-970mV    1.21mA     2.539mA    818.5uA
-947mV    943.7uA    2.005mA    716.7uA
-901mV    610.1uA    1.27mA     581.3uA
-855mV    430.7uA    824.1uA    484.6uA
-786mV    289.9uA    439.4uA    366uA
-671mV    155.9uA    155.9uA    203.6uA
-441mV    13.2uA     12.79uA    15.03uA
1.1V      0A         0A         0A
[Ramp]
| variable   typ   min   max
dV/dt_r   0.135/30.432p   0.134/38.816p   0.135/24.523p
dV/dt_f   0.320/41.680p   0.307/53.039p   0.341/34.150p
R_load = 50.000
[Rising Waveform]
R_fixture= 50.000
V_fixture= 1.100
V_fixture_min= 1.060
V_fixture_max= 1.170
|time   V(typ)   V(min)   V(max)
0s        567.3mV    548.1mV    601.6mV
147ps     568.1mV    548.7mV    600.6mV
208ps     581.6mV    547.1mV    966.8mV
268ps     920.1mV    534.2mV    1.113V
288ps     981.4mV    590.9mV    1.131V
309ps     1.024V     716.9mV    1.143V
362ps     1.075V     937.6mV    1.161V
438ps     1.093V     1.034V     1.168V
592ps     1.1V       1.057V     1.17V
3ns       1.1V       1.06V      1.17V
[Rising Waveform]
R_fixture= 50.000
V_fixture= 0.0
V_fixture_min= 0.0
V_fixture_max= 0.0
|time   V(typ)   V(min)   V(max)
0s        2.854uV    10.37uV    663.5nV
151ps     135uV      28.09uV    3.94mV
195ps     288.3uV    125.1uV    210mV
217ps     7.638mV    353.1uV    274.5mV
264ps     194mV      -21.76uV   319.8mV
299ps     262.2mV    13.97mV    267mV
373ps     287.1mV    226.6mV    228.8mV
482ps     225.9mV    269.9mV    225.5mV
596ps     224.7mV    224.9mV    225.5mV
3ns       224.7mV    224.1mV    225.5mV
[Falling Waveform]
R_fixture= 50.000
V_fixture= 1.100
V_fixture_min= 1.060
V_fixture_max= 1.170
|time   V(typ)   V(min)   V(max)
0s        1.1V       1.06V      1.17V
158ps     1.1V       1.06V      1.169V
225ps     1.093V     1.06V      616.7mV
271ps     759.6mV    1.061V     498.3mV
313ps     553.2mV    1.054V     562mV
347ps     497.7mV    892.1mV    587.4mV
411ps     530.2mV    576mV      599.3mV
493ps     564.1mV    485.5mV    601.4mV
672ps     567.3mV    547.3mV    601.6mV
3ns       567.3mV    548.1mV    601.6mV
[Falling Waveform]
R_fixture= 50.000
V_fixture= 0.0
V_fixture_min= 0.0
V_fixture_max= 0.0
|time   V(typ)   V(min)   V(max)
0s        224.7mV    224.1mV    225.5mV
143ps     224.3mV    223.8mV    229.5mV
182ps     232.5mV    223.4mV    71.64mV
198ps     230.9mV    224.3mV    31.94mV
217ps     192.3mV    227.7mV    11.76mV
254ps     47.37mV    235.8mV    1.934mV
292ps     7.781mV    166.3mV    -4.798mV
350ps     713.2uV    29.56mV    -431.4uV
429ps     -1.646mV   1.226mV    -6.663uV
3ns       -1.615uV   10.14uV    550.5nV
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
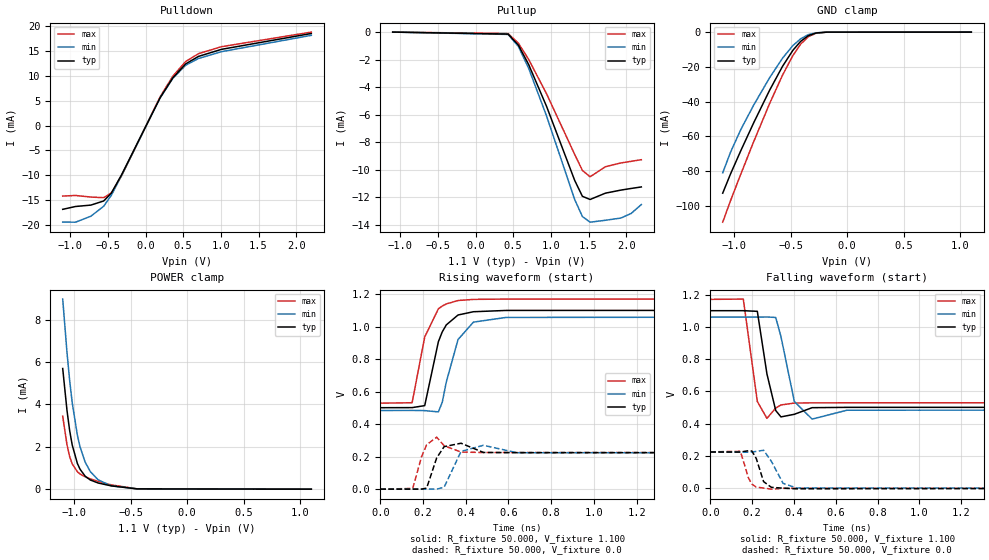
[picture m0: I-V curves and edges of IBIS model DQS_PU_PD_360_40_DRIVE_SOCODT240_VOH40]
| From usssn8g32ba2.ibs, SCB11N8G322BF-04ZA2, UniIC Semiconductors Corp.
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|   Model DQS_PU_PD_360_40_DRIVE_SOCODT240_VOH40
[Model] DQS_PU_PD_360_40_DRIVE_SOCODT240_VOH40
Model_type I/O
Polarity   Inverting
Vinl =  0.135V
Vinh =  0.305V
Vmeas =  0.220V
Rref =  50.000
Vref =  0.220V
C_comp   1.020pF   1.010pF   1.030pF
[Model Spec]
Vinh   0.305V   0.297V   0.319V
Vinl   0.135V   0.127V   0.149V
Vmeas   0.220V   0.212V   0.234V
Vref   0.220V   0.212V   0.234V
Rref   50.000   NA   NA
[Temperature Range]   25.000   0.105k   -40.000
[Voltage Range]   1.100V   1.060V   1.170V
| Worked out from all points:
|   slope of the pulldown table from 0 to 0.165 V, typ, clamps not added: 34.3 ohm
|   GND clamp passes 1 mA (typ) near -0.30 V on its own axis
|   POWER clamp passes 1 mA (typ) near -0.95 V on its own axis
|   rising waveform, R_fixture 50.000, V_fixture 1.100: 20-80 % time 69.2ps typ, 72.8ps min, 67.1ps max; typ from 0.501 V to 1.1 V
|   rising waveform, R_fixture 50.000, V_fixture 0.0: 20-80 % time 30.4ps typ, 38.8ps min, 24.5ps max; typ from 0 V to 0.225 V
|   falling waveform, R_fixture 50.000, V_fixture 1.100: 20-80 % time 39.4ps typ, 50.5ps min, 32.6ps max; typ from 1.1 V to 0.501 V
|   falling waveform, R_fixture 50.000, V_fixture 0.0: 20-80 % time 32.3ps typ, 51.8ps min, 28.7ps max; typ from 0.225 V to 0 V
[Pulldown]
|Voltage   I(typ)   I(min)   I(max)
-1.1V     -16.81mA   -19.37mA   -14.15mA
-930mV    -16.24mA   -19.39mA   -14.03mA
-726mV    -15.96mA   -18.19mA   -14.35mA
-556mV    -15.13mA   -16.19mA   -14.47mA
-454mV    -13.55mA   -13.98mA   -13.5mA
-318mV    -9.863mA   -9.979mA   -10.07mA
192mV     5.543mA    5.52mA     5.738mA
362mV     9.574mA    9.475mA    9.913mA
532mV     12.37mA    12.1mA     12.85mA
702mV     13.87mA    13.45mA    14.42mA
1.008V    15.29mA    14.82mA    15.82mA
2.2V      18.47mA    18.1mA     18.75mA
[Pullup]
|Voltage   I(typ)   I(min)   I(max)
-1.1V     900pA      9.618nA    0A
432mV     -147.1uA   -170.1uA   -107.3uA
568mV     -948.7uA   -1.043mA   -800.9uA
704mV     -2.351mA   -2.626mA   -1.98mA
942mV     -5.394mA   -6.093mA   -4.481mA
1.316V    -10.78mA   -12.17mA   -8.894mA
1.418V    -11.93mA   -13.4mA    -10.05mA
1.52V     -12.16mA   -13.81mA   -10.51mA
1.724V    -11.7mA    -13.67mA   -9.778mA
1.928V    -11.48mA   -13.51mA   -9.507mA
2.064V    -11.36mA   -13.18mA   -9.389mA
2.2V      -11.25mA   -12.53mA   -9.27mA
[GND_clamp]
|Voltage   I(typ)   I(min)   I(max)
-1.1V     -92.78mA   -81.05mA   -109.5mA
-1.031V   -81.73mA   -69.22mA   -97.17mA
-939mV    -68.18mA   -56.02mA   -81.64mA
-824mV    -52mA      -41.83mA   -62.83mA
-686mV    -33.62mA   -26.41mA   -41.32mA
-571mV    -19.76mA   -15.06mA   -24.85mA
-479mV    -10.5mA    -7.76mA    -13.5mA
-410mV    -5.313mA   -3.84mA    -6.916mA
-341mV    -2.007mA   -1.45mA    -2.59mA
-272mV    -506.9uA   -403.5uA   -609.8uA
-180mV    -45.65uA   -51.35uA   -43.55uA
1.1V      0A         0A         0A
[POWER_clamp]
|Voltage   I(typ)   I(min)   I(max)
-1.1V     5.691mA    8.967mA    3.44mA
-1.062V   3.709mA    6.444mA    2.092mA
-1.039V   2.781mA    5.152mA    1.546mA
-1.016V   2.086mA    4.085mA    1.193mA
-970mV    1.21mA     2.539mA    818.5uA
-947mV    943.7uA    2.005mA    716.7uA
-901mV    610.1uA    1.27mA     581.3uA
-855mV    430.7uA    824.1uA    484.6uA
-786mV    289.9uA    439.4uA    366uA
-671mV    155.9uA    155.9uA    203.6uA
-441mV    13.2uA     12.79uA    15.03uA
1.1V      0A         0A         0A
[Ramp]
| variable   typ   min   max
dV/dt_r   0.135/30.349p   0.134/38.742p   0.135/24.557p
dV/dt_f   0.359/39.608p   0.346/50.702p   0.384/32.650p
R_load = 50.000
[Rising Waveform]
R_fixture= 50.000
V_fixture= 1.100
V_fixture_min= 1.060
V_fixture_max= 1.170
|time   V(typ)   V(min)   V(max)
0s        501.3mV    484.2mV    529.3mV
149ps     501.9mV    484.8mV    531.8mV
208ps     514mV      483.4mV    936.7mV
272ps     907.8mV    475.5mV    1.11V
290ps     967.7mV    534.1mV    1.127V
309ps     1.011V     659.5mV    1.14V
364ps     1.072V     921mV      1.161V
436ps     1.092V     1.028V     1.168V
589ps     1.1V       1.057V     1.17V
3ns       1.1V       1.06V      1.17V
[Rising Waveform]
R_fixture= 50.000
V_fixture= 0.0
V_fixture_min= 0.0
V_fixture_max= 0.0
|time   V(typ)   V(min)   V(max)
0s        2.565uV    9.321uV    595.6nV
152ps     207.5uV    32.06uV    4.358mV
193ps     351.8uV    133.3uV    199.3mV
217ps     6.486mV    440.3uV    273.6mV
264ps     192.3mV    -50.54uV   319.7mV
299ps     261.8mV    12.23mV    267.1mV
378ps     282.7mV    232.3mV    228.3mV
483ps     225.9mV    270mV      225.5mV
640ps     224.7mV    224.1mV    225.5mV
3ns       224.7mV    224.1mV    225.5mV
[Falling Waveform]
R_fixture= 50.000
V_fixture= 1.100
V_fixture_min= 1.060
V_fixture_max= 1.170
|time   V(typ)   V(min)   V(max)
0s        1.1V       1.06V      1.17V
158ps     1.1V       1.06V      1.172V
225ps     1.096V     1.06V      537.5mV
271ps     708.2mV    1.061V     433mV
313ps     481.7mV    1.058V     496.7mV
338ps     442.1mV    940.3mV    516.1mV
402ps     458.2mV    537.2mV    527.8mV
487ps     499.2mV    428.5mV    529.2mV
654ps     501.2mV    483.6mV    529.3mV
3ns       501.3mV    484.2mV    529.3mV
[Falling Waveform]
R_fixture= 50.000
V_fixture= 0.0
V_fixture_min= 0.0
V_fixture_max= 0.0
|time   V(typ)   V(min)   V(max)
0s        224.7mV    224.1mV    225.5mV
144ps     224.3mV    223.8mV    229mV
183ps     232.7mV    223.4mV    63.06mV
199ps     230.6mV    224.4mV    25.6mV
220ps     184.3mV    228.4mV    7.498mV
255ps     41.14mV    235.4mV    1.293mV
292ps     5.954mV    167.6mV    -5.553mV
348ps     601.6uV    30.75mV    -434.5uV
413ps     -3.387mV   1.814mV    -8.404uV
3ns       -2.962uV   9.129uV    1.145nV
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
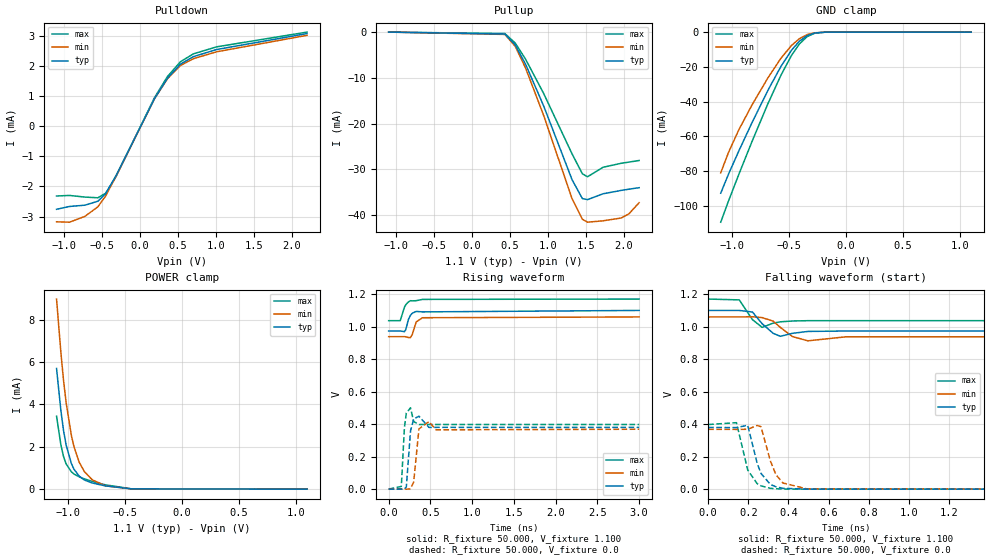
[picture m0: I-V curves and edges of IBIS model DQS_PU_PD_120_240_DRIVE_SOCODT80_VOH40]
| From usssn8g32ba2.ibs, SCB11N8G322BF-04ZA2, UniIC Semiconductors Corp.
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|   Model DQS_PU_PD_120_240_DRIVE_SOCODT80_VOH40
[Model] DQS_PU_PD_120_240_DRIVE_SOCODT80_VOH40
Model_type I/O
Polarity   Inverting
Vinl =  0.135V
Vinh =  0.305V
Vmeas =  0.220V
Rref =  50.000
Vref =  0.220V
C_comp   1.020pF   1.010pF   1.030pF
[Model Spec]
Vinh   0.305V   0.297V   0.319V
Vinl   0.135V   0.127V   0.149V
Vmeas   0.220V   0.212V   0.234V
Vref   0.220V   0.212V   0.234V
Rref   50.000   NA   NA
[Temperature Range]   25.000   0.105k   -40.000
[Voltage Range]   1.100V   1.060V   1.170V
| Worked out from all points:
|   slope of the pulldown table from 0 to 0.165 V, typ, clamps not added: 205 ohm
|   GND clamp passes 1 mA (typ) near -0.30 V on its own axis
|   POWER clamp passes 1 mA (typ) near -0.95 V on its own axis
|   rising waveform, R_fixture 50.000, V_fixture 1.100: 20-80 % time 52.2ps typ, 49.5ps min, 59.6ps max; typ from 0.973 V to 1.1 V
|   rising waveform, R_fixture 50.000, V_fixture 0.0: 20-80 % time 25.9ps typ, 33.8ps min, 20.4ps max; typ from 0 V to 0.38 V
|   falling waveform, R_fixture 50.000, V_fixture 1.100: 20-80 % time 48.4ps typ, 67.8ps min, 37.8ps max; typ from 1.1 V to 0.973 V
|   falling waveform, R_fixture 50.000, V_fixture 0.0: 20-80 % time 54.5ps typ, 60.3ps min, 52.8ps max; typ from 0.38 V to 0 V
[Pulldown]
|Voltage   I(typ)   I(min)   I(max)
-1.1V     -2.76mA    -3.177mA   -2.318mA
-930mV    -2.666mA   -3.189mA   -2.299mA
-726mV    -2.623mA   -2.996mA   -2.354mA
-556mV    -2.492mA   -2.677mA   -2.377mA
-454mV    -2.244mA   -2.321mA   -2.229mA
-318mV    -1.646mA   -1.668mA   -1.68mA
192mV     927.8uA    924.2uA    960.8uA
362mV     1.601mA    1.585mA    1.659mA
532mV     2.068mA    2.023mA    2.148mA
702mV     2.317mA    2.249mA    2.409mA
1.008V    2.554mA    2.478mA    2.643mA
2.2V      3.086mA    3.027mA    3.134mA
[Pullup]
|Voltage   I(typ)   I(min)   I(max)
-1.1V     2.7nA      29.07nA    0A
432mV     -441uA     -509.9uA   -321.6uA
568mV     -2.841mA   -3.122mA   -2.399mA
704mV     -7.035mA   -7.857mA   -5.928mA
942mV     -16.13mA   -18.22mA   -13.41mA
1.316V    -32.25mA   -36.4mA    -26.61mA
1.452V    -36.39mA   -40.9mA    -30.97mA
1.52V     -36.62mA   -41.55mA   -31.62mA
1.724V    -35.34mA   -41.25mA   -29.55mA
1.962V    -34.61mA   -40.64mA   -28.68mA
2.064V    -34.34mA   -39.74mA   -28.42mA
2.2V      -34.01mA   -37.29mA   -28.06mA
[GND_clamp]
|Voltage   I(typ)   I(min)   I(max)
-1.1V     -92.78mA   -81.05mA   -109.5mA
-1.031V   -81.73mA   -69.22mA   -97.17mA
-939mV    -68.18mA   -56.02mA   -81.64mA
-824mV    -52mA      -41.83mA   -62.83mA
-686mV    -33.62mA   -26.41mA   -41.32mA
-571mV    -19.76mA   -15.06mA   -24.85mA
-479mV    -10.5mA    -7.76mA    -13.5mA
-410mV    -5.313mA   -3.84mA    -6.916mA
-341mV    -2.007mA   -1.45mA    -2.59mA
-272mV    -506.9uA   -403.5uA   -609.8uA
-180mV    -45.65uA   -51.35uA   -43.55uA
1.1V      0A         0A         0A
[POWER_clamp]
|Voltage   I(typ)   I(min)   I(max)
-1.1V     5.691mA    8.967mA    3.44mA
-1.062V   3.709mA    6.444mA    2.092mA
-1.039V   2.781mA    5.152mA    1.546mA
-1.016V   2.086mA    4.085mA    1.193mA
-970mV    1.21mA     2.539mA    818.5uA
-947mV    943.7uA    2.005mA    716.7uA
-901mV    610.1uA    1.27mA     581.3uA
-855mV    430.7uA    824.1uA    484.6uA
-786mV    289.9uA    439.4uA    366uA
-671mV    155.9uA    155.9uA    203.6uA
-441mV    13.2uA     12.79uA    15.03uA
1.1V      0A         0A         0A
[Ramp]
| variable   typ   min   max
dV/dt_r   0.228/26.116p   0.221/33.936p   0.239/20.562p
dV/dt_f   75.974m/48.444p   73.034m/67.791p   79.780m/37.886p
R_load = 50.000
[Rising Waveform]
R_fixture= 50.000
V_fixture= 1.100
V_fixture_min= 1.060
V_fixture_max= 1.170
|time   V(typ)   V(min)   V(max)
0s        973.4mV    938.3mV    1.037V
139ps     973.7mV    938.5mV    1.037V
190ps     969.4mV    938.6mV    1.121V
205ps     981.5mV    937.7mV    1.135V
238ps     1.046V     933mV      1.153V
262ps     1.071V     932.6mV    1.16V
284ps     1.083V     953.6mV    1.159V
330ps     1.094V     1.029V     1.16V
405ps     1.091V     1.055V     1.168V
3ns       1.1V       1.06V      1.17V
[Rising Waveform]
R_fixture= 50.000
V_fixture= 0.0
V_fixture_min= 0.0
V_fixture_max= 0.0
|time   V(typ)   V(min)   V(max)
0s        5.206uV    18.91uV    1.225uV
152ps     -415.6uV   95.99uV    16.31mV
189ps     374.5uV    -60.08uV   378.5mV
212ps     13.5mV     -529.8uV   468.5mV
262ps     358mV      1.397mV    500.3mV
300ps     432.1mV    43.41mV    415.8mV
363ps     448.4mV    370.6mV    397.5mV
483ps     379.5mV    415.3mV    397.7mV
568ps     379.9mV    364.9mV    397.7mV
3ns       379.9mV    368.5mV    397.7mV
[Falling Waveform]
R_fixture= 50.000
V_fixture= 1.100
V_fixture_min= 1.060
V_fixture_max= 1.170
|time   V(typ)   V(min)   V(max)
0s        1.1V       1.06V      1.17V
155ps     1.1V       1.06V      1.165V
221ps     1.09V      1.061V     1.043V
269ps     1.018V     1.056V     995.7mV
324ps     959mV      1.034V     1.022V
360ps     940.8mV    995.4mV    1.03V
420ps     959.1mV    939.3mV    1.035V
497ps     970.8mV    913mV      1.037V
687ps     973.3mV    937.7mV    1.037V
3ns       973.4mV    938.3mV    1.037V
[Falling Waveform]
R_fixture= 50.000
V_fixture= 0.0
V_fixture_min= 0.0
V_fixture_max= 0.0
|time   V(typ)   V(min)   V(max)
0s        379.9mV    368.5mV    397.7mV
141ps     378.9mV    367.9mV    409.2mV
197ps     393.4mV    368.7mV    118.3mV
244ps     159.9mV    391.9mV    34.11mV
263ps     97.41mV    384.8mV    20.35mV
310ps     29.39mV    174.5mV    5.156mV
338ps     14.45mV    88.67mV    2.547mV
373ps     5.488mV    37.85mV    1.052mV
491ps     197.5uV    2.011mV    53.3uV
3ns       5.135uV    18.85uV    1.276uV
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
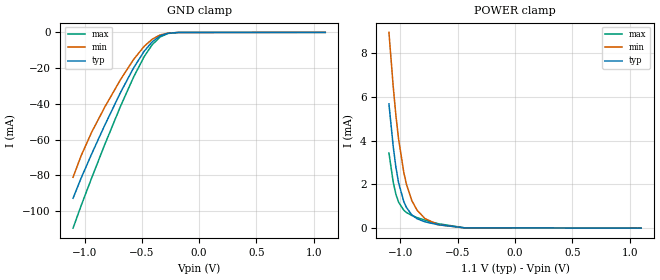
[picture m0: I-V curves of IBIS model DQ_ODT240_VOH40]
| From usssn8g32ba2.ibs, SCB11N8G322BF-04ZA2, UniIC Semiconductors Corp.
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|   Model DQ_ODT240_VOH40
[Model] DQ_ODT240_VOH40
Model_type Input
Vinl =  0.135V
Vinh =  0.305V
C_comp   1.020pF   1.010pF   1.030pF
[Model Spec]
Vinh   0.305V   0.297V   0.319V
Vinl   0.135V   0.127V   0.149V
[Add Submodel]
|  Submodel_name   Mode
ODT240_VOH40_DQDQS   Non-Driving
[Temperature Range]   25.000   0.105k   -40.000
[Voltage Range]   1.100V   1.060V   1.170V
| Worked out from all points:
|   GND clamp passes 1 mA (typ) near -0.30 V on its own axis
|   POWER clamp passes 1 mA (typ) near -0.95 V on its own axis
[GND_clamp]
|Voltage   I(typ)   I(min)   I(max)
-1.1V     -92.78mA   -81.05mA   -109.5mA
-1.031V   -81.73mA   -69.22mA   -97.17mA
-939mV    -68.18mA   -56.02mA   -81.64mA
-824mV    -52mA      -41.83mA   -62.83mA
-686mV    -33.62mA   -26.41mA   -41.32mA
-571mV    -19.76mA   -15.06mA   -24.85mA
-479mV    -10.5mA    -7.76mA    -13.5mA
-410mV    -5.313mA   -3.84mA    -6.916mA
-341mV    -2.007mA   -1.45mA    -2.59mA
-272mV    -506.9uA   -403.5uA   -609.8uA
-180mV    -45.65uA   -51.35uA   -43.55uA
1.1V      0A         0A         0A
[POWER_clamp]
|Voltage   I(typ)   I(min)   I(max)
-1.1V     5.691mA    8.967mA    3.44mA
-1.062V   3.709mA    6.444mA    2.092mA
-1.039V   2.781mA    5.152mA    1.546mA
-1.016V   2.086mA    4.085mA    1.193mA
-970mV    1.21mA     2.539mA    818.5uA
-947mV    943.7uA    2.005mA    716.7uA
-901mV    610.1uA    1.27mA     581.3uA
-855mV    430.7uA    824.1uA    484.6uA
-786mV    289.9uA    439.4uA    366uA
-671mV    155.9uA    155.9uA    203.6uA
-441mV    13.2uA     12.79uA    15.03uA
1.1V      0A         0A         0A
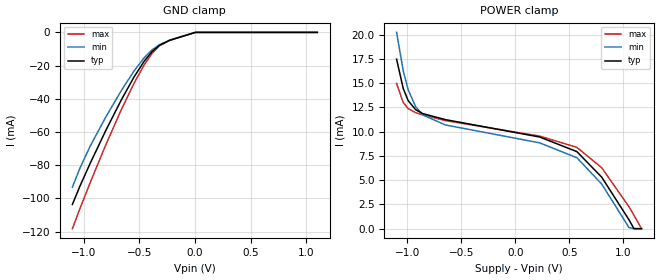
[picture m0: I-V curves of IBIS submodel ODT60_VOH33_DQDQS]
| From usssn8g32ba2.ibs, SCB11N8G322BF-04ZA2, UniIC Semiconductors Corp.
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|   Submodel ODT60_VOH33_DQDQS
[Submodel] ODT60_VOH33_DQDQS
Submodel_type Dynamic_clamp
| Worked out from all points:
|   GND clamp passes 1 mA (typ) near -0.05 V on its own axis
[GND_clamp]
|Voltage   I(typ)   I(min)   I(max)
-1.1V     -103.6mA   -93.25mA   -118.2mA
-1.031V   -92.38mA   -81.58mA   -105.9mA
-939mV    -78.66mA   -68.35mA   -90.29mA
-801mV    -59.22mA   -51.1mA    -67.89mA
-663mV    -40.96mA   -35.3mA    -46.88mA
-548mV    -27.04mA   -23.38mA   -30.86mA
-456mV    -17.45mA   -15.34mA   -19.64mA
-387mV    -11.75mA   -10.67mA   -12.84mA
-318mV    -7.765mA   -7.411mA   -8.072mA
-226mV    -4.748mA   -4.714mA   -4.752mA
4mV       0A         0A         0A
1.1V      0A         0A         0A
[POWER_clamp]
|Voltage   I(typ)   I(min)   I(max)
-1.1V     17.47mA    20.23mA    14.98mA
-1.039V   14.47mA    16.32mA    13.01mA
-993mV    13.2mA     14.32mA    12.38mA
-924mV    12.27mA    12.58mA    11.96mA
-855mV    11.85mA    11.71mA    11.72mA
-648mV    11.24mA    10.69mA    11.14mA
226mV     9.447mA    8.845mA    9.541mA
571mV     7.941mA    7.309mA    8.38mA
801mV     5.311mA    4.601mA    6.282mA
1.054V    913.3uA    118.7uA    2.256mA
1.1V      0A         0A         1.387mA
1.17V     0A         0A         0A
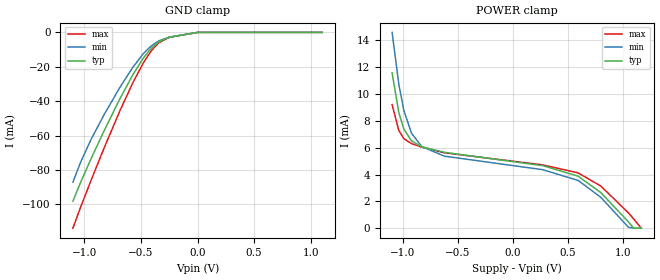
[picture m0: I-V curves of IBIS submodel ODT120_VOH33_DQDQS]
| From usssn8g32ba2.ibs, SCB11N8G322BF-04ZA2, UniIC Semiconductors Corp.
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|   Submodel ODT120_VOH33_DQDQS
[Submodel] ODT120_VOH33_DQDQS
Submodel_type Dynamic_clamp
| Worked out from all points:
|   GND clamp passes 1 mA (typ) near -0.10 V on its own axis
[GND_clamp]
|Voltage   I(typ)   I(min)   I(max)
-1.1V     -98.12mA   -87.07mA   -113.8mA
-1.031V   -86.98mA   -75.32mA   -101.4mA
-939mV    -73.35mA   -62.11mA   -85.9mA
-824mV    -57.13mA   -47.77mA   -67.13mA
-686mV    -38.7mA    -32.06mA   -45.73mA
-571mV    -24.67mA   -20.3mA    -29.33mA
-479mV    -15.04mA   -12.44mA   -17.83mA
-410mV    -9.366mA   -7.935mA   -10.88mA
-341mV    -5.438mA   -4.888mA   -5.981mA
-249mV    -2.817mA   -2.764mA   -2.853mA
4mV       0A         0A         0A
1.1V      0A         0A         0A
[POWER_clamp]
|Voltage   I(typ)   I(min)   I(max)
-1.1V     11.58mA    14.6mA     9.213mA
-1.039V   8.629mA    10.74mA    7.281mA
-993mV    7.392mA    8.776mA    6.673mA
-924mV    6.515mA    7.091mA    6.305mA
-832mV    6.069mA    6.097mA    6.048mA
-625mV    5.654mA    5.37mA     5.62mA
272mV     4.661mA    4.359mA    4.718mA
594mV     3.878mA    3.56mA     4.123mA
801mV     2.655mA    2.301mA    3.141mA
1.054V    456.6uA    59.17uA    1.128mA
1.1V      0A         0A         693.2uA
1.17V     0A         0A         0A
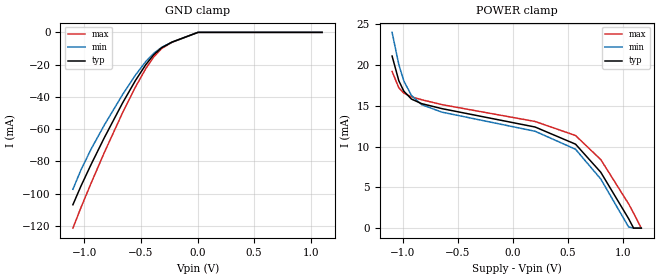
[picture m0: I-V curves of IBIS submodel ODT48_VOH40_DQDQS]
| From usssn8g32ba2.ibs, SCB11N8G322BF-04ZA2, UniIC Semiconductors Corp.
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|   Submodel ODT48_VOH40_DQDQS
[Submodel] ODT48_VOH40_DQDQS
Submodel_type Dynamic_clamp
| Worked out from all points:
|   GND clamp passes 1 mA (typ) near -0.04 V on its own axis
[GND_clamp]
|Voltage   I(typ)   I(min)   I(max)
-1.1V     -106.8mA   -97.23mA   -121.3mA
-1.031V   -95.56mA   -85.56mA   -108.9mA
-939mV    -81.77mA   -72.26mA   -93.37mA
-824mV    -65.45mA   -57.6mA    -74.65mA
-663mV    -43.92mA   -38.73mA   -50.01mA
-548mV    -29.83mA   -26.47mA   -33.88mA
-456mV    -19.94mA   -18.02mA   -22.4mA
-387mV    -13.93mA   -12.98mA   -15.28mA
-318mV    -9.572mA   -9.316mA   -10.11mA
-226mV    -6.037mA   -6.068mA   -6.212mA
4mV       0A         0A         0A
1.1V      0A         0A         0A
[POWER_clamp]
|Voltage   I(typ)   I(min)   I(max)
-1.1V     21.09mA    23.99mA    19.2mA
-1.039V   18.07mA    20.05mA    17.2mA
-993mV    16.78mA    18.03mA    16.54mA
-924mV    15.82mA    16.26mA    16.1mA
-832mV    15.26mA    15.14mA    15.74mA
-648mV    14.65mA    14.22mA    15.14mA
203mV     12.39mA    11.87mA    13.07mA
571mV     10.29mA    9.664mA    11.35mA
801mV     6.846mA    6.017mA    8.399mA
1.054V    1.172mA    154.3uA    2.986mA
1.1V      0A         0A         1.832mA
1.17V     0A         0A         0A
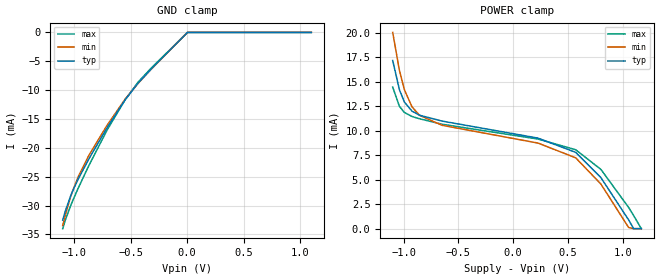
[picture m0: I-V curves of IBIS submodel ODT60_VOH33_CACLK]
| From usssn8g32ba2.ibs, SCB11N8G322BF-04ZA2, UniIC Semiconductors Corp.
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|   Submodel ODT60_VOH33_CACLK
[Submodel] ODT60_VOH33_CACLK
Submodel_type Dynamic_clamp
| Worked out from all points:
|   GND clamp passes 1 mA (typ) near -0.05 V on its own axis
[GND_clamp]
|Voltage   I(typ)   I(min)   I(max)
-1.1V     -32.52mA   -33.45mA   -33.99mA
-1.077V   -30.95mA   -31.62mA   -32.52mA
-1.031V   -28.38mA   -28.53mA   -30.07mA
-1.008V   -27.3mA    -27.22mA   -28.98mA
-962mV    -25.37mA   -24.97mA   -26.94mA
-870mV    -21.97mA   -21.35mA   -23.12mA
-709mV    -16.56mA   -16.14mA   -16.98mA
-548mV    -11.69mA   -11.57mA   -11.68mA
-433mV    -8.782mA   -8.829mA   -8.609mA
-318mV    -6.357mA   -6.401mA   -6.21mA
4mV       0A         0A         0A
1.1V      0A         0A         0A
[POWER_clamp]
|Voltage   I(typ)   I(min)   I(max)
-1.1V     17.15mA    20.02mA    14.44mA
-1.039V   14.18mA    16.15mA    12.48mA
-993mV    12.91mA    14.16mA    11.85mA
-924mV    11.99mA    12.43mA    11.44mA
-855mV    11.57mA    11.56mA    11.21mA
-648mV    10.97mA    10.54mA    10.65mA
226mV     9.239mA    8.732mA    9.14mA
571mV     7.781mA    7.226mA    8.051mA
801mV     5.205mA    4.549mA    6.042mA
1.054V    894.2uA    117.8uA    2.168mA
1.1V      0A         0A         1.332mA
1.17V     0A         0A         0A
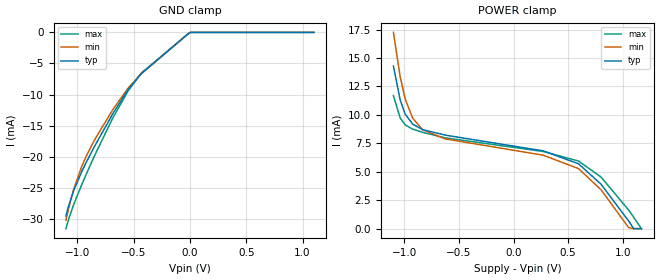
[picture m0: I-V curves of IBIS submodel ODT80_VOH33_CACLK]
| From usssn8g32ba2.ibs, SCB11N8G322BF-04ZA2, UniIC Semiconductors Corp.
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|   Submodel ODT80_VOH33_CACLK
[Submodel] ODT80_VOH33_CACLK
Submodel_type Dynamic_clamp
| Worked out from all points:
|   GND clamp passes 1 mA (typ) near -0.07 V on its own axis
[GND_clamp]
|Voltage   I(typ)   I(min)   I(max)
-1.1V     -29.53mA   -30.22mA   -31.58mA
-1.077V   -27.97mA   -28.37mA   -30.12mA
-1.031V   -25.44mA   -25.24mA   -27.69mA
-962mV    -22.49mA   -21.67mA   -24.6mA
-916mV    -20.78mA   -19.77mA   -22.67mA
-847mV    -18.37mA   -17.34mA   -19.87mA
-686mV    -13.15mA   -12.49mA   -13.84mA
-548mV    -9.204mA   -8.96mA    -9.407mA
-433mV    -6.663mA   -6.674mA   -6.573mA
-19mV     -282uA     -281.3uA   -278.5uA
4mV       0A         0A         0A
1.1V      0A         0A         0A
[POWER_clamp]
|Voltage   I(typ)   I(min)   I(max)
-1.1V     14.29mA    17.25mA    11.69mA
-1.039V   11.33mA    13.4mA     9.749mA
-993mV    10.08mA    11.42mA    9.13mA
-924mV    9.181mA    9.719mA    8.745mA
-832mV    8.706mA    8.692mA    8.464mA
-625mV    8.221mA    7.888mA    7.982mA
272mV     6.837mA    6.455mA    6.781mA
594mV     5.704mA    5.282mA    5.945mA
801mV     3.909mA    3.417mA    4.537mA
1.054V    671.8uA    88.49uA    1.629mA
1.1V      0A         0A         1.001mA
1.17V     0A         0A         0A
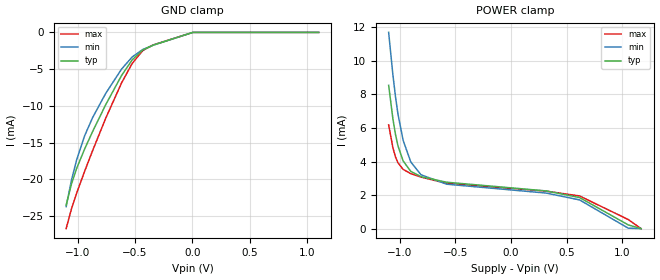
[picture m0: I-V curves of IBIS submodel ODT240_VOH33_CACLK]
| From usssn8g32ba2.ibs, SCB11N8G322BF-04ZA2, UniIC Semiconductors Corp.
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|   Submodel ODT240_VOH33_CACLK
[Submodel] ODT240_VOH33_CACLK
Submodel_type Dynamic_clamp
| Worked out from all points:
|   GND clamp passes 1 mA (typ) near -0.20 V on its own axis
[GND_clamp]
|Voltage   I(typ)   I(min)   I(max)
-1.1V     -23.51mA   -23.74mA   -26.73mA
-1.054V   -20.67mA   -20.16mA   -24.05mA
-1.008V   -18.51mA   -17.32mA   -21.86mA
-939mV    -15.88mA   -14.08mA   -18.92mA
-870mV    -13.52mA   -11.62mA   -16.12mA
-755mV    -9.838mA   -8.3mA     -11.68mA
-617mV    -5.867mA   -4.995mA   -6.877mA
-525mV    -3.749mA   -3.348mA   -4.241mA
-433mV    -2.401mA   -2.338mA   -2.48mA
-341mV    -1.731mA   -1.741mA   -1.697mA
4mV       0A         0A         0A
1.1V      0A         0A         0A
[POWER_clamp]
|Voltage   I(typ)   I(min)   I(max)
-1.1V     8.546mA    11.7mA     6.188mA
-1.062V   6.562mA    9.187mA    4.834mA
-1.039V   5.631mA    7.895mA    4.282mA
-1.016V   4.931mA    6.825mA    3.923mA
-970mV    4.039mA    5.268mA    3.536mA
-901mV    3.416mA    3.975mA    3.279mA
-809mV    3.1mA      3.212mA    3.073mA
-579mV    2.768mA    2.651mA    2.702mA
318mV     2.248mA    2.12mA     2.236mA
617mV     1.854mA    1.712mA    1.948mA
1.054V    224.4uA    29.56uA    543.9uA
1.17V     0A         0A         0A
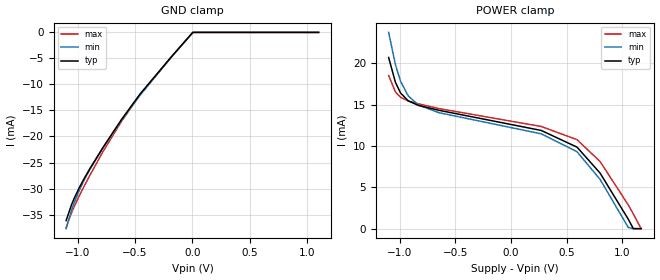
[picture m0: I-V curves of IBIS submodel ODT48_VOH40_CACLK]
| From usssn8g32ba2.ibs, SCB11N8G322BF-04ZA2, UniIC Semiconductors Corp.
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|   Submodel ODT48_VOH40_CACLK
[Submodel] ODT48_VOH40_CACLK
Submodel_type Dynamic_clamp
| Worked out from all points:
|   GND clamp passes 1 mA (typ) near -0.04 V on its own axis
[GND_clamp]
|Voltage   I(typ)   I(min)   I(max)
-1.1V     -36.16mA   -37.71mA   -37.47mA
-1.054V   -33.17mA   -34.26mA   -34.69mA
-1.031V   -31.94mA   -32.8mA    -33.52mA
-985mV    -29.8mA    -30.3mA    -31.37mA
-939mV    -27.92mA   -28.18mA   -29.37mA
-893mV    -26.17mA   -26.31mA   -27.44mA
-778mV    -22.08mA   -22.16mA   -22.87mA
-617mV    -16.72mA   -16.88mA   -17.07mA
-456mV    -11.84mA   -12.07mA   -11.96mA
-180mV    -4.6mA     -4.668mA   -4.662mA
4mV       0A         0A         0A
1.1V      0A         0A         0A
[POWER_clamp]
|Voltage   I(typ)   I(min)   I(max)
-1.1V     20.72mA    23.76mA    18.54mA
-1.039V   17.71mA    19.85mA    16.55mA
-993mV    16.43mA    17.84mA    15.9mA
-924mV    15.47mA    16.07mA    15.46mA
-832mV    14.92mA    14.96mA    15.11mA
-648mV    14.33mA    14.04mA    14.54mA
272mV     11.89mA    11.48mA    12.37mA
594mV     9.865mA    9.312mA    10.77mA
801mV     6.726mA    5.965mA    8.122mA
1.054V    1.151mA    153.4uA    2.887mA
1.1V      0A         0A         1.772mA
1.17V     0A         0A         0A
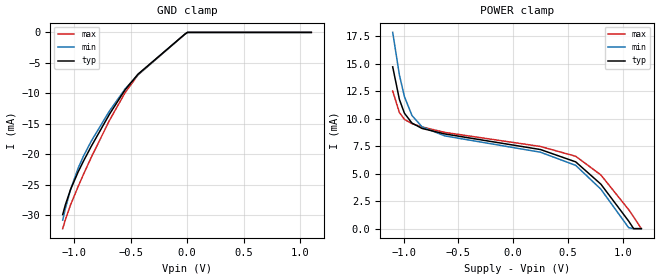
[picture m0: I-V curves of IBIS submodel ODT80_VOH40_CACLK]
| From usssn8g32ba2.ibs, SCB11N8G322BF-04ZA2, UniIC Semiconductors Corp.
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|   Submodel ODT80_VOH40_CACLK
[Submodel] ODT80_VOH40_CACLK
Submodel_type Dynamic_clamp
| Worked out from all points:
|   GND clamp passes 1 mA (typ) near -0.07 V on its own axis
[GND_clamp]
|Voltage   I(typ)   I(min)   I(max)
-1.1V     -29.91mA   -30.82mA   -32.21mA
-1.077V   -28.34mA   -28.96mA   -30.76mA
-1.031V   -25.8mA    -25.82mA   -28.33mA
-962mV    -22.84mA   -22.21mA   -25.23mA
-916mV    -21.12mA   -20.3mA    -23.29mA
-847mV    -18.69mA   -17.83mA   -20.49mA
-686mV    -13.42mA   -12.89mA   -14.43mA
-548mV    -9.424mA   -9.284mA   -9.896mA
-433mV    -6.839mA   -6.932mA   -6.963mA
-19mV     -290.1uA   -292.8uA   -295.7uA
4mV       0A         0A         0A
1.1V      0A         0A         0A
[POWER_clamp]
|Voltage   I(typ)   I(min)   I(max)
-1.1V     14.7mA     17.83mA    12.5mA
-1.039V   11.74mA    13.97mA    10.55mA
-993mV    10.49mA    11.99mA    9.929mA
-924mV    9.587mA    10.28mA    9.537mA
-832mV    9.105mA    9.248mA    9.247mA
-625mV    8.606mA    8.428mA    8.744mA
249mV     7.188mA    6.945mA    7.467mA
571mV     6.067mA    5.748mA    6.576mA
801mV     4.04mA     3.583mA    4.878mA
1.054V    691.6uA    92.16uA    1.735mA
1.1V      0A         0A         1.065mA
1.17V     0A         0A         0A
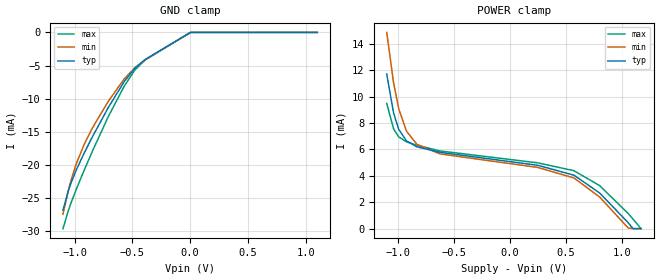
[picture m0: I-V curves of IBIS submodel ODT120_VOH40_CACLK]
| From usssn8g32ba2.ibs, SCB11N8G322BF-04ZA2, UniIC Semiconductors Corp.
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|   Submodel ODT120_VOH40_CACLK
[Submodel] ODT120_VOH40_CACLK
Submodel_type Dynamic_clamp
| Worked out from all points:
|   GND clamp passes 1 mA (typ) near -0.10 V on its own axis
[GND_clamp]
|Voltage   I(typ)   I(min)   I(max)
-1.1V     -26.78mA   -27.4mA    -29.59mA
-1.054V   -23.9mA    -23.84mA   -26.88mA
-1.031V   -22.73mA   -22.34mA   -25.74mA
-985mV    -20.74mA   -19.81mA   -23.65mA
-916mV    -18.17mA   -16.85mA   -20.75mA
-847mV    -15.79mA   -14.46mA   -17.97mA
-709mV    -11.35mA   -10.42mA   -12.73mA
-571mV    -7.432mA   -7.031mA   -8.131mA
-479mV    -5.407mA   -5.338mA   -5.694mA
-387mV    -4.054mA   -4.119mA   -4.114mA
4mV       0A         0A         0A
1.1V      0A         0A         0A
[POWER_clamp]
|Voltage   I(typ)   I(min)   I(max)
-1.1V     11.7mA     14.86mA    9.481mA
-1.039V   8.759mA    11.03mA    7.555mA
-993mV    7.524mA    9.073mA    6.946mA
-924mV    6.647mA    7.391mA    6.577mA
-832mV    6.199mA    6.394mA    6.318mA
-625mV    5.78mA     5.66mA     5.884mA
249mV     4.796mA    4.634mA    4.982mA
571mV     4.049mA    3.837mA    4.389mA
801mV     2.698mA    2.393mA    3.257mA
1.054V    462uA      61.57uA    1.159mA
1.1V      0A         0A         711.2uA
1.17V     0A         0A         0A
